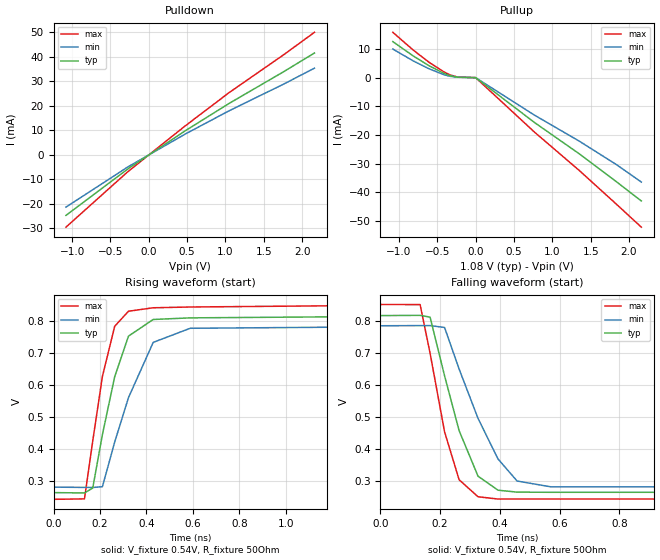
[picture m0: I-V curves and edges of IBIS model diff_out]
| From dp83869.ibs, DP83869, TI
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|   diff_out Model
[Model]   diff_out
Model_type   Output
Polarity   Non-Inverting
Vmeas = 0.54
Vref = 0.54
Cref = 2pF
Rref = 50
|   typ   min   max
C_comp   0.081pF   0.075pF   0.098pF
| Where Nom  PVT is Nominal Process, 1.08V,  27C
|   Fast PVT is Strong Process,  1.09V, -55C
|   Slow PVT is Weak Process,   1.07V, 135C
[Voltage Range]   1.08   1.07   1.09
|Junction Temperature
[Temperature Range]   27   135   -55
[Pullup Reference]   1.08   1.07   1.09
[Pulldown Reference]   0   -0   -0
[Power Clamp Reference]   1.08   1.07   1.09
[GND Clamp Reference]   0   0   0
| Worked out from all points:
|   slope of the pulldown table from 0 to 0.162 V, typ, clamps not added: 48.8 ohm
|   slope of the pullup table from 0 to 0.162 V, typ, clamps not added: 48.7 ohm
|   falling waveform, V_fixture 0.54V, R_fixture 50Ohm: 20-80 % time 100ps typ, 128ps min, 80.9ps max; typ from 0.816 V to 0.265 V
|   rising waveform, V_fixture 0.54V, R_fixture 50Ohm: 20-80 % time 107ps typ, 138ps min, 85.8ps max; typ from 0.265 V to 0.816 V
[Pulldown]
|   Voltage   I(typ)   I(min)   I(max)
-1.08V    -24.73mA   -21.35mA   -29.52mA
-269.8mV  -5.716mA   -4.92mA    -6.83mA
479.9mV   9.828mA    8.49mA     11.85mA
1.046V    20.87mA    17.87mA    25.27mA
1.753V    33.72mA    28.68mA    40.6mA
2.16V     41.43mA    35.26mA    49.86mA
[Pullup]
|   Voltage   I(typ)   I(min)   I(max)
-1.08V    12.65mA    10.05mA    15.9mA
-815.1mV  7.658mA    5.926mA    9.721mA
-607.7mV  4.22mA     3.144mA    5.419mA
-409.5mV  1.486mA    1.026mA    2mA
-333.6mV  729.9uA    520.3uA    998.9uA
-232.6mV  202.8uA    195.3uA    237.1uA
-569.9uV  57.3uA     57.64uA    64.98uA
767mV     -15.63mA   -13.06mA   -18.99mA
1.351V    -26.58mA   -22.15mA   -32.41mA
1.833V    -36.29mA   -30.31mA   -44.14mA
2.16V     -43.07mA   -36.45mA   -52.22mA
[Ramp]
R_load = 50
|   typ   min   max
dV/dt_r   0.330531/1.06843e-10   0.301374/1.36477e-10   0.363763/8.59245e-11
dV/dt_f   0.330531/9.98239e-11   0.301374/1.28638e-10   0.363764/8.10318e-11
[Falling Waveform]
V_fixture = 0.54V
V_fixture_min = 0.533V
V_fixture_max = 0.547V
R_fixture = 50Ohm
C_fixture = 0F
|   Time   V(typ)   V(min)   V(max)
0s        815.8mV    784.2mV    850.3mV
132.9ps   816.5mV    784.6mV    850mV
166.3ps   811mV      784.7mV    698.7mV
214.8ps   628.3mV    778.8mV    454mV
263.5ps   457.7mV    649.4mV    304.9mV
326.8ps   316mV      495.9mV    252mV
393.7ps   272.4mV    369.6mV    244.9mV
457.5ps   266.4mV    301mV      244.9mV
570.4ps   265.9mV    282.9mV    244.9mV
20ns      264.9mV    281.9mV    244mV
[Rising Waveform]
V_fixture = 0.54V
V_fixture_min = 0.533V
V_fixture_max = 0.547V
R_fixture = 50Ohm
C_fixture = 0F
|   Time   V(typ)   V(min)   V(max)
0s        264.9mV    281.9mV    244mV
133.3ps   263.9mV    281.1mV    245.4mV
169ps     279.1mV    280.9mV    426mV
210.6ps   445.5mV    283.3mV    626.5mV
263.5ps   625.5mV    422.3mV    782.5mV
322.9ps   751.9mV    560.4mV    829.4mV
429.4ps   803.7mV    732.4mV    840.1mV
588.8ps   808.7mV    776.3mV    842.5mV
1.596ns   814mV      781.8mV    848.8mV
20ns      815.8mV    784.2mV    850.3mV
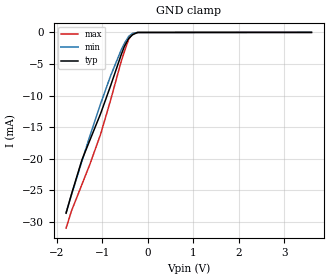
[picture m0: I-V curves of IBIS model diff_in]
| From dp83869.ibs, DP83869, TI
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|   diff_in Model
[Model]   diff_in
Model_type   Input
Vinl = 1.05
Vinh = 1.35
|   typ   min   max
C_comp   0.6913pF   0.5645pF   0.8047pF
| Where Nom  PVT is Nominal Process, 1.8V,  27C
|   Fast PVT is Strong Process,  1.98V, -55C
|   Slow PVT is Weak Process,   1.62V, 135C
[Voltage Range]   1.8   1.62   1.98
|Junction Temperature
[Temperature Range]   27   135   -55
[Power Clamp Reference]   1.8   1.62   1.98
[GND Clamp Reference]   0   0   0
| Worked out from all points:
|   GND clamp passes 1 mA (typ) near -0.43 V on its own axis
[GND Clamp]
|   Voltage   I(typ)   I(min)   I(max)
-1.8V     -28.65mA   -28.51mA   -31.01mA
-1.682V   -25.64mA   -25.76mA   -28.3mA
-1.451V   -20.19mA   -20.38mA   -24.08mA
-1.28V    -17.14mA   -16.49mA   -20.96mA
-1.042V   -12.9mA    -11.33mA   -16.17mA
-820.4mV  -8.452mA   -6.879mA   -10.73mA
-590mV    -3.59mA    -2.819mA   -4.663mA
-518.3mV  -2.241mA   -1.756mA   -3.076mA
-424.8mV  -985.2uA   -662.5uA   -1.126mA
-337.8mV  -382.5uA   -167.5uA   -177uA
-226.8mV  -13.64uA   -22.88uA   -10.64uA
3.6V      0A         0A         0A
[POWER Clamp]
|   Voltage   I(typ)   I(min)   I(max)
-1.8V     0A         0A         0A
0V        0A         0A         0A
3.6V      0A         0A         0A
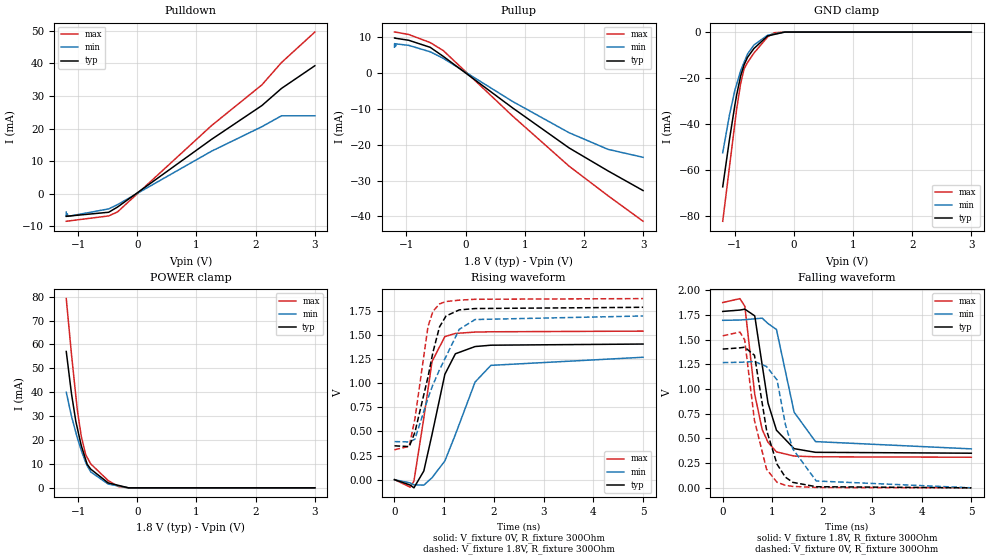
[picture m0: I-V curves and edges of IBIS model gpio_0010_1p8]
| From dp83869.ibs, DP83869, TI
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|   gpio_0010_p8 Model
[Model]   gpio_0010_1p8
Model_type   I/O
Polarity   Non-Inverting
Enable   Active-Low
Vinl = 0.344
Vinh = 1.204
Vmeas = 0.9
Vref = 0
Cref = 2pF
Rref = 100000
|   typ   min   max
C_comp   1.311pF   1.163pF   1.492pF
| Where Nom  PVT is Nominal Process, 1.8V,  27C
|   Fast PVT is Strong Process,  1.89V, -40C
|   Slow PVT is Weak Process,   1.71V, 125C
[Voltage Range]   1.8   1.71   1.89
|Junction Temperature
[Temperature Range]   27   125   -40
[Pullup Reference]   1.8   1.71   1.89
[Pulldown Reference]   0   -0   0
[Power Clamp Reference]   1.8   1.71   1.89
[GND Clamp Reference]   0   0   0
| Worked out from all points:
|   slope of the pulldown table from 0 to 0.27 V, typ, clamps not added: 73.5 ohm
|   slope of the pullup table from 0 to 0.27 V, typ, clamps not added: 80.4 ohm
|   GND clamp passes 1 mA (typ) near -0.32 V on its own axis
|   POWER clamp passes 1 mA (typ) near -0.31 V on its own axis
|   falling waveform, V_fixture 1.8V, R_fixture 300Ohm: 20-80 % time 304ps typ, 372ps min, 261ps max; typ from 1.79 V to 0.351 V
|   rising waveform, V_fixture 0V, R_fixture 300Ohm: 20-80 % time 351ps typ, 556ps min, 255ps max; typ from 0 V to 1.41 V
|   rising waveform, V_fixture 1.8V, R_fixture 300Ohm: 20-80 % time 371ps typ, 611ps min, 256ps max; typ from 0.351 V to 1.79 V
|   falling waveform, V_fixture 0V, R_fixture 300Ohm: 20-80 % time 337ps typ, 409ps min, 287ps max; typ from 1.41 V to 0 V
[Pulldown]
|   Voltage   I(typ)   I(min)   I(max)
-1.2V     -6.882mA   -5.603mA   -8.407mA
-1.2V     -6.882mA   -6.645mA   -8.407mA
-1.199V   -6.881mA   -6.942mA   -8.406mA
-1.18V    -6.847mA   -6.135mA   -8.362mA
-1.177V   -6.842mA   -6.895mA   -8.354mA
-1.163V   -6.817mA   -6.884mA   -8.322mA
-483.5mV  -5.644mA   -4.611mA   -6.772mA
-334.2mV  -4.049mA   -3.307mA   -5.542mA
1.25V     16.65mA    13.04mA    20.86mA
2.105V    27.07mA    20.59mA    33.41mA
2.436V    32.32mA    23.93mA    40.25mA
3V        39.28mA    23.92mA    49.61mA
[GND Clamp]
|   Voltage   I(typ)   I(min)   I(max)
-1.2V     -67.24mA   -52.42mA   -82.2mA
-1.087V   -46.84mA   -36.18mA   -58.78mA
-994.8mV  -31.76mA   -25.29mA   -39.68mA
-965.1mV  -27.37mA   -22.71mA   -33.52mA
-896.4mV  -19mA      -16.77mA   -22.28mA
-837.9mV  -14.15mA   -13.09mA   -15.9mA
-780.3mV  -10.96mA   -9.507mA   -13.2mA
-671.8mV  -7.121mA   -5.608mA   -9.106mA
-441.2mV  -1.683mA   -1.371mA   -2.11mA
-326mV    -1.018mA   -830.8uA   -284.2uA
-149.7mV  -2.225uA   -4.171uA   -2.272uA
3V        0A         0A         0A
[Pullup]
|   Voltage   I(typ)   I(min)   I(max)
-1.2V     9.812mA    7.256mA    11.5mA
-1.2V     9.811mA    8.028mA    11.5mA
-1.199V   9.81mA     8.276mA    11.5mA
-1.18V    9.761mA    7.582mA    11.47mA
-1.176V   9.752mA    8.197mA    11.47mA
-961.2mV  9.21mA     7.789mA    10.82mA
-596.7mV  7.232mA    5.979mA    8.559mA
-375mV    4.688mA    4.146mA    6.315mA
794.3mV   -9.681mA   -7.884mA   -11.95mA
1.75V     -20.88mA   -16.63mA   -25.97mA
2.409V    -27.31mA   -21.28mA   -34.25mA
3V        -32.79mA   -23.5mA    -41.37mA
[POWER Clamp]
|   Voltage   I(typ)   I(min)   I(max)
-1.2V     57.06mA    40.03mA    79.18mA
-1.112V   39.45mA    29.98mA    55.97mA
-1.038V   27.78mA    23.2mA     38.38mA
-1.012V   24.88mA    20.8mA     32.43mA
-946.8mV  17.71mA    15.75mA    21.64mA
-872.4mV  11.86mA    10.61mA    13.9mA
-845.6mV  9.826mA    9.2mA      12.69mA
-786.3mV  7.824mA    6.665mA    10.02mA
-492.1mV  2.079mA    1.585mA    3.05mA
-321.3mV  1.044mA    798.3uA    550.5uA
-149.7mV  3.256uA    7.598uA    3.487uA
3V        0A         0A         0A
[Ramp]
R_load = 300
|   typ   min   max
dV/dt_r   0.843678/3.50311e-10   0.760981/5.54332e-10   0.924201/2.5399e-10
dV/dt_f   0.861703/3.02041e-10   0.781303/3.71472e-10   0.939826/2.58127e-10
[Falling Waveform]
V_fixture = 1.8V
V_fixture_min = 1.71V
V_fixture_max = 1.89V
R_fixture = 300Ohm
C_fixture = 0F
|   Time   V(typ)   V(min)   V(max)
0s        1.787V     1.697V     1.877V
346.1ps   1.801V     1.7V       1.917V
445.4ps   1.81V      1.704V     1.838V
644.3ps   1.742V     1.712V     945.9mV
794.1ps   1.243V     1.719V     590.3mV
911.2ps   858.3mV    1.664V     461.5mV
1.081ns   583.8mV    1.604V     364.2mV
1.436ns   397.1mV    766.7mV    322.1mV
1.866ns   359.9mV    468.4mV    314.5mV
5ns       350.9mV    394.8mV    310.1mV
[Rising Waveform]
V_fixture = 0V
V_fixture_min = 0V
V_fixture_max = 0V
R_fixture = 300Ohm
C_fixture = 0F
|   Time   V(typ)   V(min)   V(max)
0s        142.8uV    347.4uV    103.5uV
314.9ps   -56mV      -33.82mV   -77.08mV
390.9ps   -84.63mV   -53.95mV   -14.92mV
590.1ps   90.29mV    -56.41mV   639.5mV
755.5ps   469.5mV    20.39mV    1.226V
1.013ns   1.092V     194.1mV    1.483V
1.225ns   1.305V     467.7mV    1.516V
1.621ns   1.38V      1.012V     1.53V
1.939ns   1.394V     1.185V     1.533V
5ns       1.406V     1.269V     1.54V
[Rising Waveform]
V_fixture = 1.8V
V_fixture_min = 1.71V
V_fixture_max = 1.89V
R_fixture = 300Ohm
C_fixture = 0F
|   Time   V(typ)   V(min)   V(max)
0s        350.9mV    394.9mV    310.1mV
296.8ps   343mV      391.2mV    345.3mV
411ps     491.2mV    419.6mV    631.7mV
674.3ps   1.066V     845.4mV    1.588V
772.2ps   1.318V     983mV      1.744V
905.7ps   1.584V     1.139V     1.822V
1.037ns   1.697V     1.277V     1.847V
1.303ns   1.76V      1.559V     1.861V
1.621ns   1.774V     1.66V      1.87V
5ns       1.787V     1.697V     1.877V
[Falling Waveform]
|Gnd
V_fixture = 0V
V_fixture_min = 0V
V_fixture_max = 0V
R_fixture = 300Ohm
C_fixture = 0F
|   Time   V(typ)   V(min)   V(max)
0s        1.406V     1.269V     1.54V
344.8ps   1.418V     1.272V     1.578V
441.5ps   1.425V     1.274V     1.499V
638.5ps   1.343V     1.28V      682.3mV
881.7ps   584.1mV    1.229V     188.1mV
1.093ns   239.1mV    1.093V     56.01mV
1.259ns   108.8mV    644.5mV    25.59mV
1.409ns   55.68mV    393.8mV    14.67mV
1.881ns   11.4mV     69.5mV     3.683mV
5ns       142.7uV    344.1uV    103.4uV
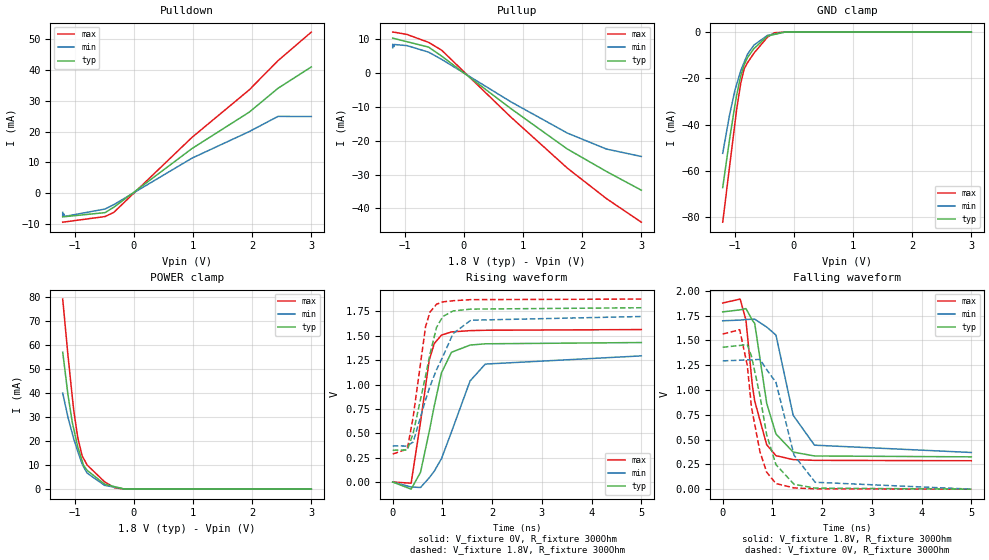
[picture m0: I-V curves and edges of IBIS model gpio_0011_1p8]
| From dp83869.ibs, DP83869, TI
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|   gpio_0011_1p8 Model
[Model]   gpio_0011_1p8
Model_type   I/O
Polarity   Non-Inverting
Enable   Active-Low
Vinl = 0.344
Vinh = 1.204
Vmeas = 0.9
Vref = 0
Cref = 2pF
Rref = 100000
|   typ   min   max
C_comp   1.311pF   1.163pF   1.492pF
| Where Nom  PVT is Nominal Process, 1.8V,  27C
|   Fast PVT is Strong Process,  1.89V, -40C
|   Slow PVT is Weak Process,   1.71V, 125C
[Voltage Range]   1.8   1.71   1.89
|Junction Temperature
[Temperature Range]   27   125   -40
[Pullup Reference]   1.8   1.71   1.89
[Pulldown Reference]   0   -0   0
[Power Clamp Reference]   1.8   1.71   1.89
[GND Clamp Reference]   0   0   0
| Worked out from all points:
|   slope of the pulldown table from 0 to 0.27 V, typ, clamps not added: 66.5 ohm
|   slope of the pullup table from 0 to 0.27 V, typ, clamps not added: 73.4 ohm
|   GND clamp passes 1 mA (typ) near -0.32 V on its own axis
|   POWER clamp passes 1 mA (typ) near -0.31 V on its own axis
|   falling waveform, V_fixture 1.8V, R_fixture 300Ohm: 20-80 % time 310ps typ, 381ps min, 265ps max; typ from 1.79 V to 0.326 V
|   rising waveform, V_fixture 0V, R_fixture 300Ohm: 20-80 % time 349ps typ, 556ps min, 253ps max; typ from 0 V to 1.43 V
|   rising waveform, V_fixture 1.8V, R_fixture 300Ohm: 20-80 % time 366ps typ, 585ps min, 256ps max; typ from 0.326 V to 1.79 V
|   falling waveform, V_fixture 0V, R_fixture 300Ohm: 20-80 % time 345ps typ, 425ps min, 290ps max; typ from 1.43 V to 0 V
[Pulldown]
|   Voltage   I(typ)   I(min)   I(max)
-1.2V     -7.586mA   -6.131mA   -9.305mA
-1.2V     -7.586mA   -7.216mA   -9.305mA
-1.199V   -7.584mA   -7.47mA    -9.302mA
-1.18V    -7.548mA   -6.664mA   -9.254mA
-1.177V   -7.542mA   -7.424mA   -9.246mA
-1.154V   -7.498mA   -7.397mA   -9.187mA
-484.9mV  -6.212mA   -5.046mA   -7.479mA
-335.7mV  -4.459mA   -3.622mA   -6.114mA
983.3mV   14.49mA    11.39mA    18.1mA
1.951V    26.27mA    19.99mA    33.47mA
2.437V    33.98mA    24.89mA    42.91mA
3V        40.89mA    24.85mA    52.15mA
[GND Clamp]
|   Voltage   I(typ)   I(min)   I(max)
-1.2V     -67.24mA   -52.42mA   -82.2mA
-1.087V   -46.86mA   -36.19mA   -58.8mA
-994.9mV  -31.78mA   -25.3mA    -39.7mA
-964.9mV  -27.35mA   -22.7mA    -33.49mA
-896.2mV  -18.98mA   -16.75mA   -22.25mA
-837.6mV  -14.13mA   -13.08mA   -15.89mA
-780.4mV  -10.96mA   -9.512mA   -13.2mA
-671.9mV  -7.122mA   -5.611mA   -9.107mA
-441mV    -1.68mA    -1.371mA   -2.105mA
-326mV    -1.017mA   -831.5uA   -284.7uA
-149.9mV  -2.239uA   -4.739uA   -2.288uA
3V        0A         0A         0A
[Pullup]
|   Voltage   I(typ)   I(min)   I(max)
-1.2V     10.26mA    7.441mA    12.05mA
-1.2V     10.26mA    8.244mA    12.05mA
-1.199V   10.26mA    8.456mA    12.05mA
-1.18V    10.18mA    7.771mA    12.02mA
-1.177V   10.16mA    8.388mA    12.02mA
-960mV    9.218mA    8.065mA    11.36mA
-594.5mV  7.629mA    6.137mA    9.026mA
-371.4mV  4.938mA    3.988mA    6.676mA
799.1mV   -10.56mA   -8.548mA   -13.08mA
1.75V     -22.45mA   -17.74mA   -28.08mA
2.409V    -29.05mA   -22.45mA   -37.06mA
3V        -34.6mA    -24.65mA   -44.04mA
[POWER Clamp]
|   Voltage   I(typ)   I(min)   I(max)
-1.2V     57.06mA    40.03mA    79.18mA
-1.112V   39.47mA    29.99mA    56mA
-1.038V   27.78mA    23.2mA     38.37mA
-1.012V   24.91mA    20.83mA    32.49mA
-946.5mV  17.69mA    15.73mA    21.61mA
-872.7mV  11.88mA    10.62mA    13.93mA
-845.3mV  9.809mA    9.183mA    12.69mA
-786.5mV  7.83mA     6.671mA    10.03mA
-492.1mV  2.077mA    1.586mA    3.051mA
-321.6mV  1.043mA    799.4uA    552.5uA
-149.9mV  3.279uA    8.166uA    3.532uA
3V        0A         0A         0A
[Ramp]
R_load = 300
|   typ   min   max
dV/dt_r   0.858578/3.47247e-10   0.776076/5.53587e-10   0.938429/2.53122e-10
dV/dt_f   0.877046/3.08069e-10   0.796646/3.7984e-10   0.954465/2.62352e-10
[Falling Waveform]
V_fixture = 1.8V
V_fixture_min = 1.71V
V_fixture_max = 1.89V
R_fixture = 300Ohm
C_fixture = 0F
|   Time   V(typ)   V(min)   V(max)
0s        1.788V     1.698V     1.877V
350.9ps   1.808V     1.705V     1.917V
467.2ps   1.821V     1.711V     1.706V
596.9ps   1.703V     1.714V     1.043V
643.9ps   1.671V     1.714V     888.2mV
884.5ps   866.2mV    1.635V     448.2mV
1.071ns   556.7mV    1.554V     337.9mV
1.417ns   374.1mV    745.3mV    297.9mV
1.846ns   334.8mV    443.7mV    290.7mV
5ns       326.1mV    370mV      286.7mV
[Rising Waveform]
V_fixture = 0V
V_fixture_min = 0V
V_fixture_max = 0V
R_fixture = 300Ohm
C_fixture = 0F
|   Time   V(typ)   V(min)   V(max)
0s        132.2uV    322uV      94.76uV
370.5ps   -73.43mV   -51.39mV   -12.32mV
559.2ps   99.21mV    -56.11mV   613.8mV
734.8ps   518.6mV    43.6mV     1.251V
835.7ps   779.6mV    111.1mV    1.421V
980.4ps   1.12V      239.4mV    1.507V
1.182ns   1.331V     513.9mV    1.54V
1.556ns   1.405V     1.037V     1.553V
1.862ns   1.418V     1.21V      1.557V
5ns       1.431V     1.294V     1.564V
[Rising Waveform]
V_fixture = 1.8V
V_fixture_min = 1.71V
V_fixture_max = 1.89V
R_fixture = 300Ohm
C_fixture = 0F
|   Time   V(typ)   V(min)   V(max)
0s        326.1mV    370mV      286.7mV
294.2ps   328.7mV    369.2mV    338.4mV
412.3ps   501mV      411.2mV    670.3mV
660.9ps   1.088V     842.9mV    1.594V
748.9ps   1.311V     980.1mV    1.743V
881.5ps   1.586V     1.152V     1.824V
1.007ns   1.698V     1.286V     1.848V
1.215ns   1.755V     1.523V     1.86V
1.571ns   1.774V     1.66V      1.871V
5ns       1.788V     1.698V     1.877V
[Falling Waveform]
|Gnd
V_fixture = 0V
V_fixture_min = 0V
V_fixture_max = 0V
R_fixture = 300Ohm
C_fixture = 0F
|   Time   V(typ)   V(min)   V(max)
0s        1.431V     1.294V     1.564V
341.4ps   1.449V     1.3V       1.608V
494.2ps   1.457V     1.305V     1.249V
578.3ps   1.341V     1.303V     826.6mV
748.9ps   942.7mV    1.309V     377mV
884.5ps   547.2mV    1.205V     170.7mV
1.071ns   247.3mV    1.077V     56.64mV
1.435ns   49.01mV    342.3mV    12.73mV
1.86ns    10.73mV    69.58mV    3.682mV
5ns       131.9uV    318.6uV    94.58uV
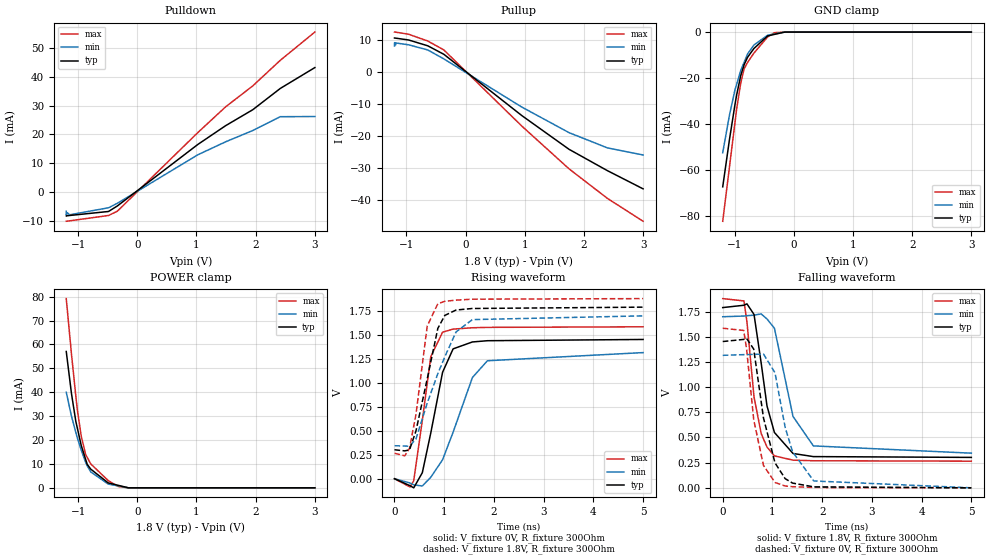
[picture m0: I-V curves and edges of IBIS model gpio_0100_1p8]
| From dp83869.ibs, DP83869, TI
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|   gpio_0100_1p8 Model
[Model]   gpio_0100_1p8
Model_type   I/O
Polarity   Non-Inverting
Enable   Active-Low
Vinl = 0.344
Vinh = 1.204
Vmeas = 0.9
Vref = 0
Cref = 2pF
Rref = 100000
|   typ   min   max
C_comp   1.311pF   1.163pF   1.492pF
| Where Nom  PVT is Nominal Process, 1.8V,  27C
|   Fast PVT is Strong Process,  1.89V, -40C
|   Slow PVT is Weak Process,   1.71V, 125C
[Voltage Range]   1.8   1.71   1.89
|Junction Temperature
[Temperature Range]   27   125   -40
[Pullup Reference]   1.8   1.71   1.89
[Pulldown Reference]   0   0   0
[Power Clamp Reference]   1.8   1.71   1.89
[GND Clamp Reference]   0   0   0
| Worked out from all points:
|   slope of the pulldown table from 0 to 0.27 V, typ, clamps not added: 60.7 ohm
|   slope of the pullup table from 0 to 0.27 V, typ, clamps not added: 68.1 ohm
|   GND clamp passes 1 mA (typ) near -0.32 V on its own axis
|   POWER clamp passes 1 mA (typ) near -0.31 V on its own axis
|   falling waveform, V_fixture 1.8V, R_fixture 300Ohm: 20-80 % time 290ps typ, 366ps min, 244ps max; typ from 1.79 V to 0.302 V
|   rising waveform, V_fixture 0V, R_fixture 300Ohm: 20-80 % time 329ps typ, 541ps min, 234ps max; typ from 0 V to 1.45 V
|   rising waveform, V_fixture 1.8V, R_fixture 300Ohm: 20-80 % time 353ps typ, 585ps min, 238ps max; typ from 0.302 V to 1.79 V
|   falling waveform, V_fixture 0V, R_fixture 300Ohm: 20-80 % time 315ps typ, 396ps min, 263ps max; typ from 1.45 V to 0 V
[Pulldown]
|   Voltage   I(typ)   I(min)   I(max)
-1.2V     -8.344mA   -6.739mA   -10.24mA
-1.2V     -8.343mA   -7.775mA   -10.24mA
-1.199V   -8.341mA   -8.078mA   -10.24mA
-1.18V    -8.301mA   -7.271mA   -10.19mA
-1.144V   -8.225mA   -7.984mA   -10.09mA
-485.8mV  -6.829mA   -5.539mA   -8.224mA
-336.6mV  -4.904mA   -3.978mA   -6.725mA
1.025V    16.53mA    12.92mA    20.68mA
1.492V    23.03mA    17.42mA    29.59mA
1.951V    28.59mA    21.35mA    36.88mA
2.417V    36.01mA    26.17mA    45.81mA
3V        43.26mA    26.21mA    55.63mA
[GND Clamp]
|   Voltage   I(typ)   I(min)   I(max)
-1.2V     -67.24mA   -52.42mA   -82.2mA
-1.087V   -46.85mA   -36.19mA   -58.79mA
-994.8mV  -31.77mA   -25.29mA   -39.69mA
-964.9mV  -27.35mA   -22.7mA    -33.49mA
-896.3mV  -18.98mA   -16.75mA   -22.26mA
-837.7mV  -14.13mA   -13.08mA   -15.89mA
-780.3mV  -10.96mA   -9.509mA   -13.2mA
-671.9mV  -7.12mA    -5.609mA   -9.106mA
-441mV    -1.677mA   -1.371mA   -2.106mA
-326.1mV  -1.016mA   -831.5uA   -284.9uA
-149.5mV  -2.214uA   -4.045uA   -2.26uA
3V        0A         0A         0A
[Pullup]
|   Voltage   I(typ)   I(min)   I(max)
-1.2V     10.74mA    8.24mA     12.6mA
-1.2V     10.74mA    9.03mA     12.6mA
-1.199V   10.74mA    9.282mA    12.59mA
-1.18V    10.69mA    8.576mA    12.57mA
-1.177V   10.68mA    9.188mA    12.56mA
-961.2mV  10.12mA    8.61mA     11.91mA
-637.6mV  8.297mA    6.996mA    9.791mA
-366.1mV  5.643mA    4.204mA    7.004mA
949.3mV   -13.49mA   -10.84mA   -16.77mA
1.749V    -24.06mA   -18.85mA   -30.17mA
2.397V    -30.73mA   -23.62mA   -39.4mA
3V        -36.42mA   -25.83mA   -46.56mA
[POWER Clamp]
|   Voltage   I(typ)   I(min)   I(max)
-1.2V     57.06mA    40.03mA    79.18mA
-1.112V   39.47mA    29.99mA    56.02mA
-1.038V   27.76mA    23.19mA    38.34mA
-1.012V   24.91mA    20.83mA    32.49mA
-946.6mV  17.69mA    15.74mA    21.62mA
-872.7mV  11.89mA    10.63mA    13.93mA
-845.3mV  9.812mA    9.186mA    12.69mA
-786.5mV  7.832mA    6.672mA    10.03mA
-492.1mV  2.078mA    1.585mA    3.051mA
-321.6mV  1.045mA    799.6uA    552.7uA
-149.5mV  3.236uA    7.435uA    3.475uA
3V        0A         0A         0A
[Ramp]
R_load = 300
|   typ   min   max
dV/dt_r   0.871267/3.27771e-10   0.788734/5.38836e-10   0.950576/2.32924e-10
dV/dt_f   0.891835/2.8772e-10   0.812532/3.63371e-10   0.968032/2.42051e-10
[Falling Waveform]
V_fixture = 1.8V
V_fixture_min = 1.71V
V_fixture_max = 1.89V
R_fixture = 300Ohm
C_fixture = 0F
|   Time   V(typ)   V(min)   V(max)
0s        1.789V     1.698V     1.878V
426.8ps   1.812V     1.705V     1.855V
487.1ps   1.826V     1.708V     1.647V
629.6ps   1.721V     1.714V     902.7mV
773.1ps   1.24V      1.726V     539.6mV
890.1ps   813.7mV    1.676V     405.3mV
1.04ns    549.2mV    1.584V     317mV
1.414ns   341mV      708.3mV    274.9mV
1.823ns   310.1mV    416.2mV    268.8mV
5ns       302.1mV    344.1mV    264.8mV
[Rising Waveform]
V_fixture = 0V
V_fixture_min = 0V
V_fixture_max = 0V
R_fixture = 300Ohm
C_fixture = 0F
|   Time   V(typ)   V(min)   V(max)
0s        120.5uV    296.1uV    87.45uV
311.9ps   -72.87mV   -44.38mV   -85.96mV
386.9ps   -95.02mV   -64.21mV   -21.56mV
560ps     62.98mV    -75.57mV   608.7mV
730ps     477.3mV    15.12mV    1.273V
967.2ps   1.11V      197.7mV    1.528V
1.179ns   1.354V     485.1mV    1.56V
1.567ns   1.426V     1.055V     1.574V
1.869ns   1.439V     1.23V      1.578V
5ns       1.452V     1.315V     1.584V
[Rising Waveform]
V_fixture = 1.8V
V_fixture_min = 1.71V
V_fixture_max = 1.89V
R_fixture = 300Ohm
C_fixture = 0F
|   Time   V(typ)   V(min)   V(max)
0s        302.1mV    344.1mV    264.8mV
206.1ps   290.4mV    341mV      239.1mV
301.8ps   300.1mV    338.3mV    316.4mV
431.6ps   497.4mV    414.4mV    668.7mV
658.4ps   1.041V     788mV      1.592V
872ps     1.568V     1.096V     1.825V
1.013ns   1.703V     1.272V     1.85V
1.239ns   1.759V     1.531V     1.862V
1.567ns   1.775V     1.659V     1.872V
5ns       1.789V     1.698V     1.878V
[Falling Waveform]
|Gnd
V_fixture = 0V
V_fixture_min = 0V
V_fixture_max = 0V
R_fixture = 300Ohm
C_fixture = 0F
|   Time   V(typ)   V(min)   V(max)
0s        1.452V     1.315V     1.584V
422.2ps   1.473V     1.322V     1.562V
479.6ps   1.483V     1.322V     1.381V
623.3ps   1.377V     1.325V     674.7mV
819.6ps   694.5mV    1.328V     223.1mV
1.051ns   248.1mV    1.142V     53.2mV
1.256ns   91.25mV    599.4mV    18.38mV
1.405ns   47.1mV     357.7mV    11.53mV
1.831ns   9.793mV    68.2mV     3.539mV
5ns       119.6uV    292.5uV    87.41uV
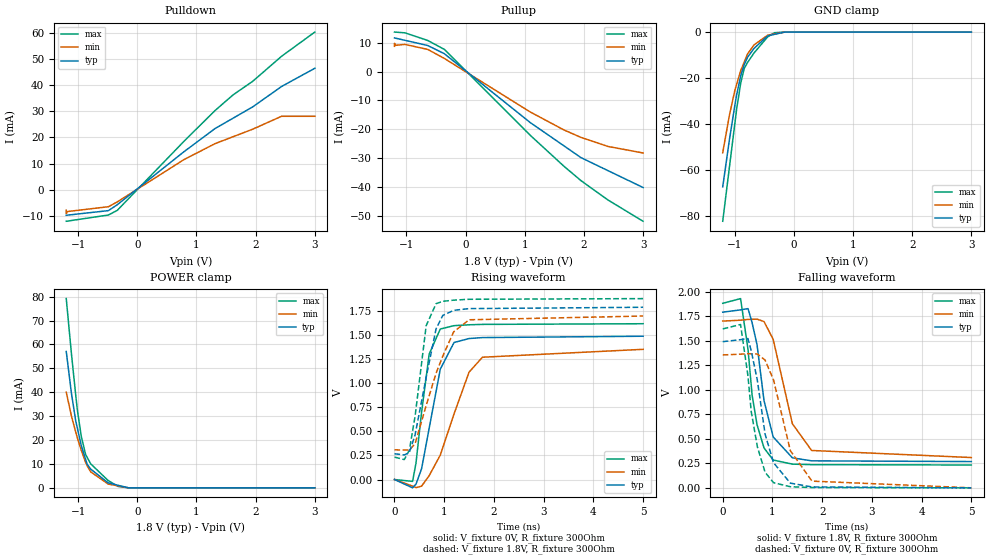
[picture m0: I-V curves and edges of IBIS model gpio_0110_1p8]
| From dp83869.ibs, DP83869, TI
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|   gpio_0110_1p8 Model
[Model]   gpio_0110_1p8
Model_type   I/O
Polarity   Non-Inverting
Enable   Active-Low
Vinl = 0.344
Vinh = 1.204
Vmeas = 0.9
Vref = 0
Cref = 2pF
Rref = 100000
|   typ   min   max
C_comp   1.311pF   1.163pF   1.492pF
| Where Nom  PVT is Nominal Process, 1.8V,  27C
|   Fast PVT is Strong Process,  1.89V, -40C
|   Slow PVT is Weak Process,   1.71V, 125C
[Voltage Range]   1.8   1.71   1.89
|Junction Temperature
[Temperature Range]   27   125   -40
[Pullup Reference]   1.8   1.71   1.89
[Pulldown Reference]   -0   0   -0
[Power Clamp Reference]   1.8   1.71   1.89
[GND Clamp Reference]   0   0   0
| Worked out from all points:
|   slope of the pulldown table from 0 to 0.27 V, typ, clamps not added: 53.5 ohm
|   slope of the pullup table from 0 to 0.27 V, typ, clamps not added: 60.3 ohm
|   GND clamp passes 1 mA (typ) near -0.32 V on its own axis
|   POWER clamp passes 1 mA (typ) near -0.31 V on its own axis
|   falling waveform, V_fixture 1.8V, R_fixture 300Ohm: 20-80 % time 295ps typ, 376ps min, 247ps max; typ from 1.79 V to 0.268 V
|   rising waveform, V_fixture 0V, R_fixture 300Ohm: 20-80 % time 320ps typ, 536ps min, 228ps max; typ from 0 V to 1.49 V
|   rising waveform, V_fixture 1.8V, R_fixture 300Ohm: 20-80 % time 338ps typ, 546ps min, 234ps max; typ from 0.268 V to 1.79 V
|   falling waveform, V_fixture 0V, R_fixture 300Ohm: 20-80 % time 321ps typ, 422ps min, 265ps max; typ from 1.49 V to 0 V
[Pulldown]
|   Voltage   I(typ)   I(min)   I(max)
-1.2V     -9.726mA   -7.769mA   -12.01mA
-1.2V     -9.726mA   -8.965mA   -12.01mA
-1.198V   -9.722mA   -9.107mA   -12.01mA
-1.181V   -9.679mA   -8.301mA   -11.95mA
-488.2mV  -7.948mA   -6.456mA   -9.617mA
-338.6mV  -5.709mA   -4.627mA   -7.852mA
788.9mV   14.53mA    11.53mA    18.51mA
1.315V    23.39mA    17.62mA    30.26mA
1.616V    27.29mA    20.23mA    36.18mA
1.951V    31.65mA    23.13mA    41.41mA
2.437V    39.41mA    28.05mA    50.93mA
3V        46.37mA    28.05mA    60.19mA
[GND Clamp]
|   Voltage   I(typ)   I(min)   I(max)
-1.2V     -67.24mA   -52.42mA   -82.2mA
-1.087V   -46.8mA    -36.15mA   -58.73mA
-994.6mV  -31.73mA   -25.27mA   -39.64mA
-964.9mV  -27.34mA   -22.69mA   -33.48mA
-896.2mV  -18.97mA   -16.75mA   -22.25mA
-837.6mV  -14.13mA   -13.08mA   -15.89mA
-780mV    -10.95mA   -9.494mA   -13.19mA
-671.2mV  -7.103mA   -5.592mA   -9.086mA
-441mV    -1.675mA   -1.368mA   -2.104mA
-326mV    -1.014mA   -829.7uA   -284.5uA
-149.9mV  -2.237uA   -5.374uA   -2.286uA
3V        0A         0A         0A
[Pullup]
|   Voltage   I(typ)   I(min)   I(max)
-1.2V     11.66mA    8.759mA    13.7mA
-1.2V     11.66mA    9.676mA    13.7mA
-1.199V   11.65mA    9.795mA    13.69mA
-1.181V   11.57mA    9.104mA    13.67mA
-1.024V   10.84mA    9.409mA    13.43mA
-638.6mV  9.032mA    7.68mA     10.78mA
-358.1mV  6.195mA    4.551mA    7.687mA
1.093V    -17.69mA   -14.02mA   -22.1mA
1.661V    -25.74mA   -20.23mA   -32.81mA
1.95V     -29.85mA   -22.84mA   -37.82mA
2.407V    -34.37mA   -25.98mA   -44.55mA
3V        -40.22mA   -28.24mA   -51.93mA
[POWER Clamp]
|   Voltage   I(typ)   I(min)   I(max)
-1.2V     57.06mA    40.03mA    79.18mA
-1.112V   39.46mA    29.98mA    55.99mA
-1.038V   27.76mA    23.19mA    38.34mA
-1.012V   24.9mA     20.83mA    32.48mA
-946.5mV  17.68mA    15.73mA    21.61mA
-872.7mV  11.88mA    10.63mA    13.92mA
-845.2mV  9.806mA    9.182mA    12.68mA
-786.5mV  7.83mA     6.673mA    10.03mA
-492.1mV  2.077mA    1.586mA    3.05mA
-321.5mV  1.043mA    799.8uA    552.3uA
-149.9mV  3.275uA    8.764uA    3.528uA
3V        0A         0A         0A
[Ramp]
R_load = 300
|   typ   min   max
dV/dt_r   0.893424/3.18195e-10   0.81186/5.33659e-10   0.971265/2.27143e-10
dV/dt_f   0.913151/2.92741e-10   0.834389/3.73963e-10   0.988038/2.43813e-10
[Falling Waveform]
V_fixture = 1.8V
V_fixture_min = 1.71V
V_fixture_max = 1.89V
R_fixture = 300Ohm
C_fixture = 0F
|   Time   V(typ)   V(min)   V(max)
0s        1.79V      1.699V     1.88V
358.8ps   1.813V     1.708V     1.928V
509ps     1.826V     1.716V     1.409V
591.6ps   1.681V     1.717V     943.3mV
690.1ps   1.458V     1.719V     643.5mV
830.7ps   888.2mV    1.694V     406.4mV
1.015ns   518.5mV    1.513V     283.5mV
1.401ns   305.9mV    653mV      241.6mV
1.788ns   275mV      380.7mV    236.3mV
5ns       267.8mV    308.8mV    232.8mV
[Rising Waveform]
V_fixture = 0V
V_fixture_min = 0V
V_fixture_max = 0V
R_fixture = 300Ohm
C_fixture = 0F
|   Time   V(typ)   V(min)   V(max)
0s        105.5uV    261.5uV    75.99uV
363.5ps   -86.25mV   -68.14mV   -19.38mV
432.7ps   -47.7mV    -84.3mV    171.1mV
545.1ps   112.1mV    -68.47mV   700.2mV
697.7ps   533.3mV    40.17mV    1.304V
921.2ps   1.147V     254.1mV    1.564V
1.198ns   1.424V     682.1mV    1.599V
1.5ns     1.465V     1.116V     1.608V
1.769ns   1.475V     1.271V     1.612V
5ns       1.489V     1.353V     1.619V
[Rising Waveform]
V_fixture = 1.8V
V_fixture_min = 1.71V
V_fixture_max = 1.89V
R_fixture = 300Ohm
C_fixture = 0F
|   Time   V(typ)   V(min)   V(max)
0s        267.8mV    308.8mV    232.8mV
196.7ps   255.5mV    306.1mV    207.4mV
298.5ps   280.1mV    306.6mV    304.4mV
413.6ps   462.7mV    370.9mV    654.4mV
637.5ps   1.062V     769.9mV    1.599V
836.2ps   1.566V     1.104V     1.827V
972.7ps   1.706V     1.284V     1.852V
1.191ns   1.758V     1.535V     1.864V
1.5ns     1.776V     1.66V      1.873V
5ns       1.79V      1.699V     1.88V
[Falling Waveform]
|Gnd
V_fixture = 0V
V_fixture_min = 0V
V_fixture_max = 0V
R_fixture = 300Ohm
C_fixture = 0F
|   Time   V(typ)   V(min)   V(max)
0s        1.489V     1.354V     1.619V
358.8ps   1.51V      1.362V     1.664V
506.4ps   1.521V     1.367V     1.144V
573.6ps   1.396V     1.366V     777mV
697.7ps   1.092V     1.364V     416.5mV
852.5ps   546.2mV    1.301V     158.6mV
1.022ns   255.8mV    1.1V       52.45mV
1.36ns    47.9mV     378.3mV    11.25mV
1.795ns   9.089mV    68.42mV    3.12mV
5ns       105uV      258.1uV    75.94uV
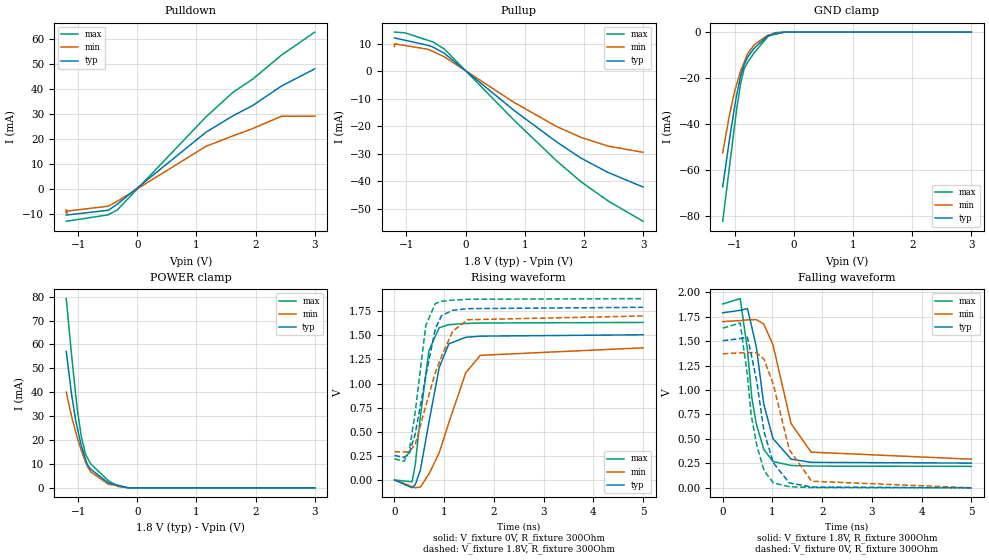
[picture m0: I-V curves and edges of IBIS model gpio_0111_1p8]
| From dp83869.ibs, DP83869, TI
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|   gpio_0111_1p8 Model
[Model]   gpio_0111_1p8
Model_type   I/O
Polarity   Non-Inverting
Enable   Active-Low
Vinl = 0.344
Vinh = 1.204
Vmeas = 0.9
Vref = 0
Cref = 2pF
Rref = 100000
|   typ   min   max
C_comp   1.311pF   1.163pF   1.492pF
| Where Nom  PVT is Nominal Process, 1.8V,  27C
|   Fast PVT is Strong Process,  1.89V, -40C
|   Slow PVT is Weak Process,   1.71V, 125C
[Voltage Range]   1.8   1.71   1.89
|Junction Temperature
[Temperature Range]   27   125   -40
[Pullup Reference]   1.8   1.71   1.89
[Pulldown Reference]   0   0   0
[Power Clamp Reference]   1.8   1.71   1.89
[GND Clamp Reference]   0   0   0
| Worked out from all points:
|   slope of the pulldown table from 0 to 0.27 V, typ, clamps not added: 50.2 ohm
|   slope of the pullup table from 0 to 0.27 V, typ, clamps not added: 56.9 ohm
|   GND clamp passes 1 mA (typ) near -0.32 V on its own axis
|   POWER clamp passes 1 mA (typ) near -0.31 V on its own axis
|   falling waveform, V_fixture 1.8V, R_fixture 300Ohm: 20-80 % time 306ps typ, 396ps min, 254ps max; typ from 1.79 V to 0.253 V
|   rising waveform, V_fixture 0V, R_fixture 300Ohm: 20-80 % time 316ps typ, 528ps min, 228ps max; typ from 0 V to 1.5 V
|   rising waveform, V_fixture 1.8V, R_fixture 300Ohm: 20-80 % time 331ps typ, 525ps min, 233ps max; typ from 0.253 V to 1.79 V
|   falling waveform, V_fixture 0V, R_fixture 300Ohm: 20-80 % time 335ps typ, 461ps min, 272ps max; typ from 1.5 V to 0 V
[Pulldown]
|   Voltage   I(typ)   I(min)   I(max)
-1.2V     -10.43mA   -8.298mA   -12.91mA
-1.2V     -10.43mA   -9.44mA    -12.91mA
-1.2V     -10.43mA   -9.632mA   -12.91mA
-1.187V   -10.4mA    -9.619mA   -12.86mA
-1.181V   -10.38mA   -8.829mA   -12.84mA
-489.5mV  -8.521mA   -6.903mA   -10.33mA
-339.1mV  -6.112mA   -4.94mA    -8.42mA
1.157V    22.56mA    16.95mA    28.64mA
1.613V    29.12mA    21.14mA    38.47mA
1.951V    33.29mA    24.08mA    43.83mA
2.436V    41.04mA    29mA       53.38mA
3V        47.92mA    29.01mA    62.58mA
[GND Clamp]
|   Voltage   I(typ)   I(min)   I(max)
-1.2V     -67.24mA   -52.42mA   -82.2mA
-1.087V   -46.79mA   -36.15mA   -58.72mA
-994.6mV  -31.73mA   -25.27mA   -39.64mA
-964.9mV  -27.35mA   -22.7mA    -33.49mA
-896.3mV  -18.98mA   -16.76mA   -22.26mA
-837.7mV  -14.14mA   -13.09mA   -15.89mA
-780mV    -10.94mA   -9.493mA   -13.18mA
-671.2mV  -7.104mA   -5.592mA   -9.087mA
-441.1mV  -1.681mA   -1.368mA   -2.107mA
-326.1mV  -1.018mA   -830.1uA   -285.3uA
-149.6mV  -2.223uA   -4.071uA   -2.264uA
3V        0A         0A         0A
[Pullup]
|   Voltage   I(typ)   I(min)   I(max)
-1.2V     12.11mA    8.943mA    14.25mA
-1.2V     12.11mA    9.861mA    14.25mA
-1.199V   12.1mA     9.976mA    14.24mA
-1.021V   11.26mA    9.352mA    13.96mA
-638.6mV  9.442mA    8.012mA    11.26mA
-545.5mV  8.769mA    7.186mA    10.61mA
-354.1mV  6.463mA    5.205mA    8.021mA
825.2mV   -14.3mA    -11.38mA   -17.87mA
1.54V     -25.67mA   -20.07mA   -32.55mA
1.951V    -31.54mA   -24mA      -40.11mA
2.407V    -36.73mA   -27.16mA   -47.07mA
3V        -42.03mA   -29.43mA   -54.47mA
[POWER Clamp]
|   Voltage   I(typ)   I(min)   I(max)
-1.2V     57.06mA    40.03mA    79.18mA
-1.112V   39.46mA    29.99mA    56mA
-1.038V   27.77mA    23.2mA     38.37mA
-1.012V   24.91mA    20.83mA    32.49mA
-946.6mV  17.7mA     15.74mA    21.63mA
-872.8mV  11.89mA    10.63mA    13.93mA
-845.2mV  9.808mA    9.184mA    12.69mA
-786.2mV  7.82mA     6.665mA    10.02mA
-491.4mV  2.072mA    1.582mA    3.036mA
-321.2mV  1.041mA    798.4uA    549.5uA
-149.6mV  3.246uA    7.478uA    3.484uA
3V        0A         0A         0A
[Ramp]
R_load = 300
|   typ   min   max
dV/dt_r   0.902938/3.14249e-10   0.821981/5.26547e-10   0.980021/2.26343e-10
dV/dt_f   0.922308/3.03975e-10   0.844022/3.93294e-10   0.996494/2.51243e-10
[Falling Waveform]
V_fixture = 1.8V
V_fixture_min = 1.71V
V_fixture_max = 1.89V
R_fixture = 300Ohm
C_fixture = 0F
|   Time   V(typ)   V(min)   V(max)
0s        1.79V      1.7V       1.88V
351.9ps   1.815V     1.71V      1.935V
497ps     1.834V     1.718V     1.412V
586.6ps   1.64V      1.719V     915.9mV
675.2ps   1.442V     1.72V      655.1mV
825.9ps   854.2mV    1.675V     393.3mV
1.011ns   503.2mV    1.462V     268.8mV
1.375ns   293.6mV    656.8mV    228.5mV
1.779ns   260.6mV    365mV      222.6mV
5ns       253.1mV    293.2mV    219.3mV
[Rising Waveform]
V_fixture = 0V
V_fixture_min = 0V
V_fixture_max = 0V
R_fixture = 300Ohm
C_fixture = 0F
|   Time   V(typ)   V(min)   V(max)
0s        99.55uV    247uV      71.36uV
353.8ps   -80.74mV   -68.81mV   -19.52mV
418.1ps   -48.56mV   -81.52mV   160.2mV
520.9ps   102.5mV    -73.61mV   657mV
692.3ps   596.8mV    61.18mV    1.34V
899.7ps   1.166V     282.1mV    1.578V
1.094ns   1.411V     594.4mV    1.61V
1.432ns   1.479V     1.11V      1.622V
1.726ns   1.491V     1.292V     1.627V
5ns       1.505V     1.37V      1.633V
[Rising Waveform]
V_fixture = 1.8V
V_fixture_min = 1.71V
V_fixture_max = 1.89V
R_fixture = 300Ohm
C_fixture = 0F
|   Time   V(typ)   V(min)   V(max)
0s        253.1mV    293.2mV    219.3mV
192.7ps   234.9mV    290mV      193.7mV
295ps     269.5mV    292.3mV    296.4mV
416.9ps   476.7mV    368.6mV    701.6mV
628.8ps   1.077V     766.5mV    1.601V
821.5ps   1.568V     1.113V     1.829V
947.2ps   1.704V     1.285V     1.852V
1.17ns    1.759V     1.541V     1.864V
1.467ns   1.776V     1.661V     1.873V
5ns       1.79V      1.7V       1.88V
[Falling Waveform]
|Gnd
V_fixture = 0V
V_fixture_min = 0V
V_fixture_max = 0V
R_fixture = 300Ohm
C_fixture = 0F
|   Time   V(typ)   V(min)   V(max)
0s        1.505V     1.371V     1.633V
351.9ps   1.526V     1.38V      1.685V
495.7ps   1.542V     1.384V     1.153V
573.2ps   1.364V     1.383V     744mV
684.5ps   1.088V     1.38V      435.9mV
832.7ps   569.9mV    1.314V     174.4mV
1.019ns   255.2mV    1.055V     51.04mV
1.339ns   50.14mV    390.2mV    11.54mV
1.788ns   8.181mV    67.79mV    2.938mV
5ns       99.75uV    243.1uV    71.19uV
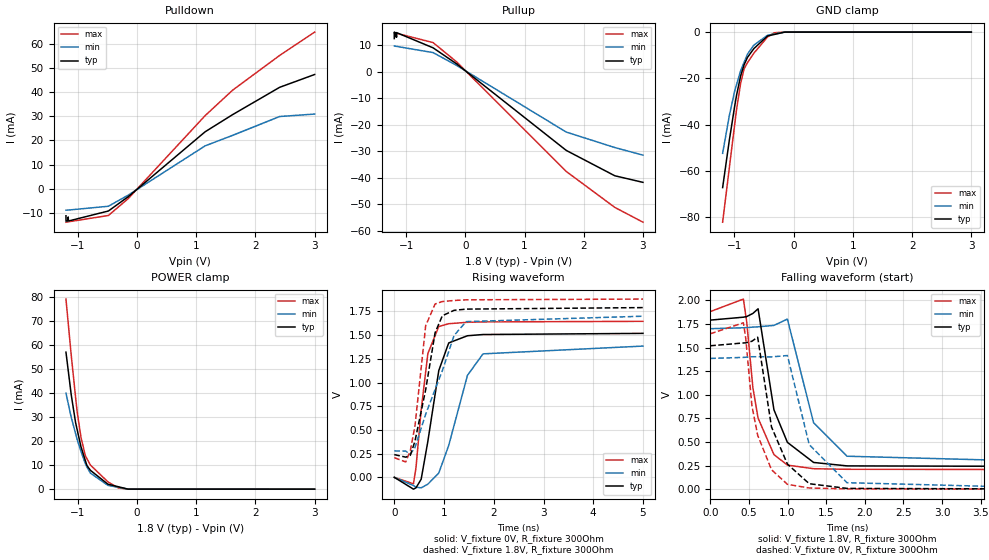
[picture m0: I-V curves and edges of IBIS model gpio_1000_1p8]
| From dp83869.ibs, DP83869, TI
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|   gpio_1000_1p8 Model
[Model]   gpio_1000_1p8
Model_type   I/O
Polarity   Non-Inverting
Enable   Active-Low
Vinl = 0.344
Vinh = 1.204
Vmeas = 0.9
Vref = 0
Cref = 2pF
Rref = 100000
|   typ   min   max
C_comp   1.311pF   1.163pF   1.492pF
| Where Nom  PVT is Nominal Process, 1.8V,  27C
|   Fast PVT is Strong Process,  1.89V, -40C
|   Slow PVT is Weak Process,   1.71V, 125C
[Voltage Range]   1.8   1.71   1.89
|Junction Temperature
[Temperature Range]   27   125   -40
[Pullup Reference]   1.8   1.71   1.89
[Pulldown Reference]   0   0   -0
[Power Clamp Reference]   1.8   1.71   1.89
[GND Clamp Reference]   0   0   0
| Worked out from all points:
|   slope of the pulldown table from 0 to 0.27 V, typ, clamps not added: 47.3 ohm
|   slope of the pullup table from 0 to 0.27 V, typ, clamps not added: 54 ohm
|   GND clamp passes 1 mA (typ) near -0.32 V on its own axis
|   POWER clamp passes 1 mA (typ) near -0.31 V on its own axis
|   falling waveform, V_fixture 1.8V, R_fixture 300Ohm: 20-80 % time 248ps typ, 310ps min, 211ps max; typ from 1.79 V to 0.24 V
|   rising waveform, V_fixture 0V, R_fixture 300Ohm: 20-80 % time 275ps typ, 430ps min, 201ps max; typ from 0 V to 1.52 V
|   rising waveform, V_fixture 1.8V, R_fixture 300Ohm: 20-80 % time 304ps typ, 578ps min, 199ps max; typ from 0.24 V to 1.79 V
|   falling waveform, V_fixture 0V, R_fixture 300Ohm: 20-80 % time 277ps typ, 340ps min, 231ps max; typ from 1.52 V to 0 V
[Pulldown]
|   Voltage   I(typ)   I(min)   I(max)
-1.2V     -11.13mA   -8.839mA   -13.79mA
-1.199V   -13.31mA   -8.837mA   -13.78mA
-1.172V   -13.25mA   -8.788mA   -13.68mA
-1.162V   -11.63mA   -8.768mA   -13.64mA
-1.159V   -13.22mA   -8.764mA   -13.63mA
-1.133V   -13.15mA   -8.715mA   -13.53mA
-483.5mV  -9.168mA   -7.199mA   -11.02mA
-149.8mV  -3.275mA   -2.624mA   -4.066mA
1.15V     23.58mA    17.76mA    30.25mA
1.614V    30.67mA    22.1mA     40.78mA
2.409V    41.97mA    29.9mA     55.15mA
3V        47.27mA    30.91mA    64.8mA
[GND Clamp]
|   Voltage   I(typ)   I(min)   I(max)
-1.2V     -67.24mA   -52.42mA   -82.2mA
-1.087V   -46.79mA   -36.14mA   -58.72mA
-994.6mV  -31.72mA   -25.27mA   -39.63mA
-965mV    -27.36mA   -22.7mA    -33.5mA
-896.4mV  -19mA      -16.77mA   -22.28mA
-837.5mV  -14.12mA   -13.07mA   -15.88mA
-780.1mV  -10.95mA   -9.497mA   -13.19mA
-671.2mV  -7.105mA   -5.592mA   -9.084mA
-440.9mV  -1.679mA   -1.367mA   -2.102mA
-325.9mV  -1.016mA   -828.5uA   -283.5uA
-149.8mV  -2.234uA   -4.072uA   -2.282uA
3V        0A         0A         0A
[Pullup]
|   Voltage   I(typ)   I(min)   I(max)
-1.2V     12.58mA    9.738mA    14.79mA
-1.2V     14.69mA    9.737mA    14.79mA
-1.198V   15.04mA    9.734mA    14.78mA
-1.173V   13.27mA    9.664mA    14.64mA
-1.172V   14.9mA     9.661mA    14.63mA
-1.162V   13.09mA    9.633mA    14.57mA
-1.159V   14.81mA    9.624mA    14.56mA
-545.1mV  9.098mA    7.293mA    11.08mA
-149.8mV  3.07mA     2.479mA    3.818mA
1.704V    -29.66mA   -22.73mA   -37.61mA
2.524V    -39.24mA   -28.58mA   -51.19mA
3V        -41.73mA   -31.45mA   -56.78mA
[POWER Clamp]
|   Voltage   I(typ)   I(min)   I(max)
-1.2V     57.06mA    40.03mA    79.18mA
-1.112V   39.49mA    30mA       56.04mA
-1.038V   27.79mA    23.21mA    38.39mA
-1.012V   24.88mA    20.81mA    32.44mA
-946.5mV  17.67mA    15.73mA    21.6mA
-873.1mV  11.91mA    10.65mA    13.96mA
-845.4mV  9.817mA    9.192mA    12.7mA
-786.4mV  7.83mA     6.672mA    10.03mA
-492mV    2.077mA    1.584mA    3.048mA
-321.4mV  1.043mA    798.3uA    551.2uA
-149.8mV  3.271uA    7.517uA    3.516uA
3V        0A         0A         0A
[Ramp]
R_load = 300
|   typ   min   max
dV/dt_r   0.911232/2.74642e-10   0.830825/4.2935e-10   0.987648/2.0096e-10
dV/dt_f   0.930418/2.47277e-10   0.85287/3.09756e-10   1.00387/2.10443e-10
[Falling Waveform]
V_fixture = 1.8V
V_fixture_min = 1.71V
V_fixture_max = 1.89V
R_fixture = 300Ohm
C_fixture = 0F
|   Time   V(typ)   V(min)   V(max)
0s        1.791V     1.7V       1.881V
429.3ps   1.822V     1.71V      2.014V
473ps     1.829V     1.712V     1.768V
552.4ps   1.862V     1.717V     1.073V
619.4ps   1.911V     1.72V      752.9mV
824.5ps   841mV      1.735V     366.2mV
998.6ps   495.8mV    1.802V     255.1mV
1.337ns   283.1mV    705mV      216.8mV
1.769ns   246.7mV    349.1mV    210.5mV
5ns       240mV      278.9mV    207.5mV
[Rising Waveform]
V_fixture = 0V
V_fixture_min = 0V
V_fixture_max = 0V
R_fixture = 300Ohm
C_fixture = 0F
|   Time   V(typ)   V(min)   V(max)
0s        93.16uV    233.5uV    66.63uV
385.7ps   -124.6mV   -86.82mV   -68.24mV
436.5ps   -110mV     -103.9mV   104.1mV
540.3ps   -19.93mV   -110.6mV   711.3mV
674.8ps   380.3mV    -71.89mV   1.306V
894.1ps   1.126V     45.44mV    1.591V
1.094ns   1.418V     336.6mV    1.621V
1.471ns   1.494V     1.076V     1.636V
1.784ns   1.507V     1.303V     1.64V
5ns       1.519V     1.385V     1.646V
[Rising Waveform]
V_fixture = 1.8V
V_fixture_min = 1.71V
V_fixture_max = 1.89V
R_fixture = 300Ohm
C_fixture = 0F
|   Time   V(typ)   V(min)   V(max)
0s        240mV      278.9mV    207.5mV
229.7ps   213.1mV    276.7mV    162.3mV
321.9ps   233.2mV    243.6mV    281.1mV
415.9ps   382.4mV    315.2mV    543.1mV
630.8ps   924.5mV    665.7mV    1.599V
820.3ps   1.526V     928mV      1.829V
965.7ps   1.705V     1.124V     1.855V
1.201ns   1.762V     1.496V     1.866V
1.444ns   1.775V     1.643V     1.873V
5ns       1.791V     1.7V       1.881V
[Falling Waveform]
|Gnd
V_fixture = 0V
V_fixture_min = 0V
V_fixture_max = 0V
R_fixture = 300Ohm
C_fixture = 0F
|   Time   V(typ)   V(min)   V(max)
0s        1.519V     1.385V     1.646V
429.3ps   1.549V     1.396V     1.763V
459.6ps   1.55V      1.398V     1.6V
539.4ps   1.567V     1.403V     885mV
613.9ps   1.61V      1.403V     571.3mV
792.7ps   659.3mV    1.401V     206.1mV
998.6ps   265.6mV    1.416V     51.37mV
1.281ns   57.87mV    471.6mV    12.49mV
1.769ns   8.251mV    68.61mV    2.895mV
5ns       92.61uV    230.5uV    66.79uV
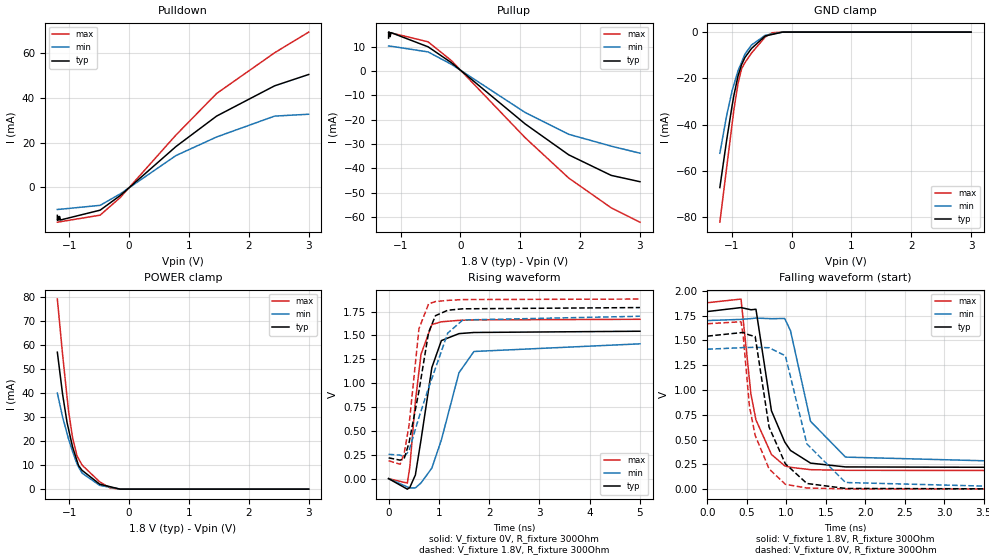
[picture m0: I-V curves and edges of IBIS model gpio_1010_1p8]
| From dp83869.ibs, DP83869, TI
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|   gpio_1010_1p8 Model
[Model]   gpio_1010_1p8
Model_type   I/O
Polarity   Non-Inverting
Enable   Active-Low
Vinl = 0.344
Vinh = 1.204
Vmeas = 0.9
Vref = 0
Cref = 2pF
Rref = 100000
|   typ   min   max
C_comp   1.311pF   1.163pF   1.492pF
| Where Nom  PVT is Nominal Process, 1.8V,  27C
|   Fast PVT is Strong Process,  1.89V, -40C
|   Slow PVT is Weak Process,   1.71V, 125C
[Voltage Range]   1.8   1.71   1.89
|Junction Temperature
[Temperature Range]   27   125   -40
[Pullup Reference]   1.8   1.71   1.89
[Pulldown Reference]   0   0   -0
[Power Clamp Reference]   1.8   1.71   1.89
[GND Clamp Reference]   0   0   0
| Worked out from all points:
|   slope of the pulldown table from 0 to 0.27 V, typ, clamps not added: 41.5 ohm
|   slope of the pullup table from 0 to 0.27 V, typ, clamps not added: 47.6 ohm
|   GND clamp passes 1 mA (typ) near -0.32 V on its own axis
|   POWER clamp passes 1 mA (typ) near -0.31 V on its own axis
|   falling waveform, V_fixture 1.8V, R_fixture 300Ohm: 20-80 % time 246ps typ, 310ps min, 208ps max; typ from 1.79 V to 0.218 V
|   rising waveform, V_fixture 0V, R_fixture 300Ohm: 20-80 % time 268ps typ, 424ps min, 197ps max; typ from 0 V to 1.54 V
|   rising waveform, V_fixture 1.8V, R_fixture 300Ohm: 20-80 % time 299ps typ, 540ps min, 197ps max; typ from 0.218 V to 1.79 V
|   falling waveform, V_fixture 0V, R_fixture 300Ohm: 20-80 % time 274ps typ, 340ps min, 227ps max; typ from 1.54 V to 0 V
[Pulldown]
|   Voltage   I(typ)   I(min)   I(max)
-1.2V     -12.51mA   -9.869mA   -15.55mA
-1.199V   -14.7mA    -9.867mA   -15.55mA
-1.175V   -13.03mA   -9.819mA   -15.44mA
-1.173V   -14.63mA   -9.814mA   -15.43mA
-1.162V   -13.01mA   -9.792mA   -15.39mA
-1.147V   -14.56mA   -9.762mA   -15.32mA
-484.9mV  -10.18mA   -8.031mA   -12.41mA
-149.5mV  -3.654mA   -2.913mA   -4.549mA
782.8mV   18.23mA    14.2mA     23.37mA
1.462V    31.82mA    22.49mA    41.9mA
2.43V     45.31mA    31.8mA     60.06mA
3V        50.38mA    32.64mA    69.3mA
[GND Clamp]
|   Voltage   I(typ)   I(min)   I(max)
-1.2V     -67.24mA   -52.42mA   -82.2mA
-1.087V   -46.84mA   -36.18mA   -58.77mA
-994.8mV  -31.76mA   -25.29mA   -39.68mA
-964.7mV  -27.32mA   -22.68mA   -33.44mA
-896.6mV  -19.01mA   -16.78mA   -22.3mA
-837.6mV  -14.13mA   -13.08mA   -15.89mA
-780.3mV  -10.96mA   -9.506mA   -13.2mA
-671.4mV  -7.108mA   -5.597mA   -9.091mA
-441mV    -1.677mA   -1.369mA   -2.104mA
-326mV    -1.015mA   -830.6uA   -284.3uA
-149.5mV  -2.217uA   -4.045uA   -2.26uA
3V        0A         0A         0A
[Pullup]
|   Voltage   I(typ)   I(min)   I(max)
-1.2V     13.5mA     10.26mA    15.89mA
-1.199V   15.97mA    10.25mA    15.88mA
-1.187V   14.25mA    10.22mA    15.81mA
-1.186V   15.91mA    10.22mA    15.8mA
-1.175V   14.06mA    10.19mA    15.74mA
-1.16V    15.75mA    10.16mA    15.65mA
-539.8mV  9.924mA    7.824mA    11.98mA
-149.5mV  3.386mA    2.723mA    4.219mA
1.083V    -21.76mA   -17.07mA   -27.43mA
1.81V     -34.44mA   -26mA      -43.97mA
2.52V     -42.88mA   -30.87mA   -56.2mA
3V        -45.47mA   -33.76mA   -62.1mA
[POWER Clamp]
|   Voltage   I(typ)   I(min)   I(max)
-1.2V     57.06mA    40.03mA    79.18mA
-1.112V   39.49mA    30mA       56.03mA
-1.038V   27.79mA    23.21mA    38.39mA
-1.012V   24.89mA    20.82mA    32.46mA
-946.6mV  17.69mA    15.74mA    21.62mA
-873.2mV  11.92mA    10.66mA    13.97mA
-845.4mV  9.817mA    9.193mA    12.7mA
-786.6mV  7.832mA    6.674mA    10.03mA
-492.1mV  2.077mA    1.585mA    3.05mA
-321.5mV  1.043mA    799.2uA    552.2uA
-149.5mV  3.239uA    7.462uA    3.472uA
3V        0A         0A         0A
[Ramp]
R_load = 300
|   typ   min   max
dV/dt_r   0.926118/2.67683e-10   0.846914/4.23556e-10   1.00119/1.9663e-10
dV/dt_f   0.944256/2.45414e-10   0.86764/3.0853e-10   1.01652/2.08029e-10
[Falling Waveform]
V_fixture = 1.8V
V_fixture_min = 1.71V
V_fixture_max = 1.89V
R_fixture = 300Ohm
C_fixture = 0F
|   Time   V(typ)   V(min)   V(max)
0s        1.792V     1.701V     1.881V
427.4ps   1.832V     1.713V     1.918V
553.7ps   1.81V      1.721V     954.4mV
616.6ps   1.815V     1.726V     698.7mV
812.6ps   791.3mV    1.72V      350.6mV
980.7ps   476.6mV    1.722V     235.4mV
1.054ns   390.7mV    1.599V     220.7mV
1.308ns   262.9mV    684.8mV    196.6mV
1.751ns   224.5mV    323.5mV    190.1mV
5ns       217.8mV    255mV      187.3mV
[Rising Waveform]
V_fixture = 0V
V_fixture_min = 0V
V_fixture_max = 0V
R_fixture = 300Ohm
C_fixture = 0F
|   Time   V(typ)   V(min)   V(max)
0s        84.29uV    211.4uV    59.91uV
373ps     -110.3mV   -87.03mV   -46.47mV
421.7ps   -92.9mV    -97mV      119.7mV
532.6ps   37.75mV    -97.03mV   808.9mV
645.4ps   406.9mV    -44.76mV   1.304V
860.9ps   1.164V     110.9mV    1.614V
1.05ns    1.446V     405.8mV    1.643V
1.4ns     1.519V     1.109V     1.658V
1.698ns   1.531V     1.332V     1.663V
5ns       1.544V     1.412V     1.669V
[Rising Waveform]
V_fixture = 1.8V
V_fixture_min = 1.71V
V_fixture_max = 1.89V
R_fixture = 300Ohm
C_fixture = 0F
|   Time   V(typ)   V(min)   V(max)
0s        217.8mV    255mV      187.3mV
228.7ps   193.6mV    246.2mV    150.5mV
309.7ps   209.8mV    230.3mV    263.6mV
404.9ps   371.8mV    289.4mV    549.9mV
604ps     917.5mV    642.3mV    1.57V
795.5ps   1.533V     950mV      1.831V
932.8ps   1.707V     1.157V     1.855V
1.177ns   1.764V     1.525V     1.867V
1.477ns   1.779V     1.662V     1.876V
5ns       1.792V     1.701V     1.881V
[Falling Waveform]
|Gnd
V_fixture = 0V
V_fixture_min = 0V
V_fixture_max = 0V
R_fixture = 300Ohm
C_fixture = 0F
|   Time   V(typ)   V(min)   V(max)
0s        1.544V     1.412V     1.669V
427.4ps   1.579V     1.427V     1.689V
453.9ps   1.581V     1.429V     1.558V
533.6ps   1.555V     1.43V      839.7mV
606.6ps   1.541V     1.431V     543.1mV
782.7ps   626.3mV    1.427V     204.6mV
989.1ps   255.9mV    1.346V     48.95mV
1.262ns   57.35mV    456.2mV    11.99mV
1.751ns   7.51mV     67.24mV    2.73mV
5ns       83.67uV    208.5uV    59.61uV
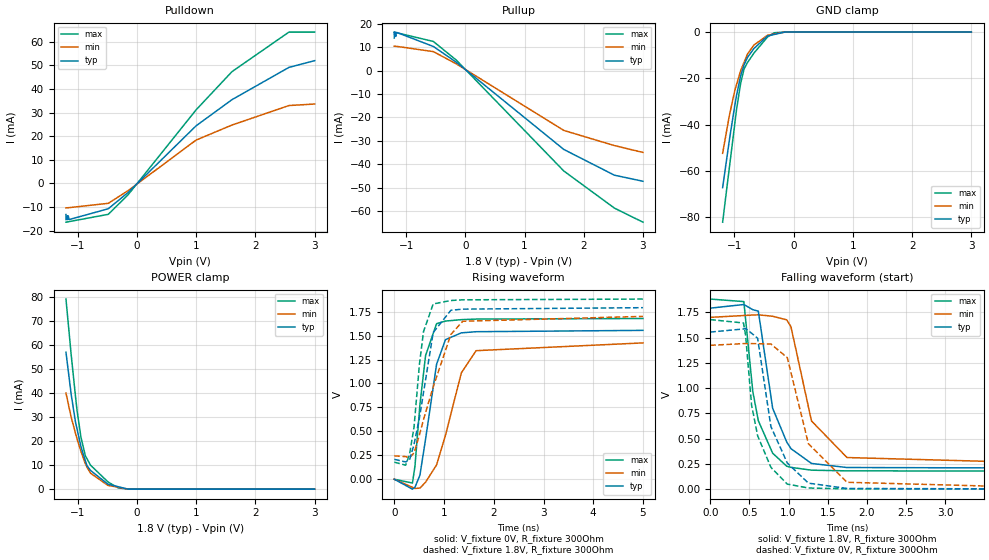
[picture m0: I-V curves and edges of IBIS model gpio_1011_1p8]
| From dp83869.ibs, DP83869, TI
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|   gpio_1011_1p8 Model
[Model]   gpio_1011_1p8
Model_type   I/O
Polarity   Non-Inverting
Enable   Active-Low
Vinl = 0.344
Vinh = 1.204
Vmeas = 0.9
Vref = 0
Cref = 2pF
Rref = 100000
|   typ   min   max
C_comp   1.311pF   1.163pF   1.492pF
| Where Nom  PVT is Nominal Process, 1.8V,  27C
|   Fast PVT is Strong Process,  1.89V, -40C
|   Slow PVT is Weak Process,   1.71V, 125C
[Voltage Range]   1.8   1.71   1.89
|Junction Temperature
[Temperature Range]   27   125   -40
[Pullup Reference]   1.8   1.71   1.89
[Pulldown Reference]   0   -0   -0
[Power Clamp Reference]   1.8   1.71   1.89
[GND Clamp Reference]   0   0   0
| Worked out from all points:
|   slope of the pulldown table from 0 to 0.27 V, typ, clamps not added: 40.4 ohm
|   slope of the pullup table from 0 to 0.27 V, typ, clamps not added: 46.3 ohm
|   GND clamp passes 1 mA (typ) near -0.32 V on its own axis
|   POWER clamp passes 1 mA (typ) near -0.31 V on its own axis
|   falling waveform, V_fixture 1.8V, R_fixture 300Ohm: 20-80 % time 250ps typ, 315ps min, 212ps max; typ from 1.79 V to 0.208 V
|   rising waveform, V_fixture 0V, R_fixture 300Ohm: 20-80 % time 266ps typ, 422ps min, 197ps max; typ from 0 V to 1.55 V
|   rising waveform, V_fixture 1.8V, R_fixture 300Ohm: 20-80 % time 295ps typ, 518ps min, 196ps max; typ from 0.208 V to 1.79 V
|   falling waveform, V_fixture 0V, R_fixture 300Ohm: 20-80 % time 279ps typ, 347ps min, 230ps max; typ from 1.55 V to 0 V
[Pulldown]
|   Voltage   I(typ)   I(min)   I(max)
-1.2V     -13.21mA   -10.4mA    -16.45mA
-1.199V   -15.44mA   -10.39mA   -16.45mA
-1.174V   -13.8mA    -10.34mA   -16.33mA
-1.172V   -15.37mA   -10.34mA   -16.32mA
-1.161V   -13.78mA   -10.31mA   -16.27mA
-1.146V   -15.33mA   -10.28mA   -16.2mA
-485.4mV  -10.76mA   -8.468mA   -13.12mA
-149.7mV  -3.855mA   -3.066mA   -4.804mA
997.6mV   24.37mA    18.33mA    31.13mA
1.604V    35.45mA    24.7mA     47.32mA
2.566V    49.12mA    32.96mA    64.07mA
3V        51.97mA    33.6mA     64.07mA
[GND Clamp]
|   Voltage   I(typ)   I(min)   I(max)
-1.2V     -67.24mA   -52.42mA   -82.2mA
-1.087V   -46.83mA   -36.17mA   -58.77mA
-994.8mV  -31.76mA   -25.29mA   -39.68mA
-964.8mV  -27.33mA   -22.69mA   -33.47mA
-896.3mV  -18.98mA   -16.76mA   -22.26mA
-837.8mV  -14.14mA   -13.09mA   -15.9mA
-780.3mV  -10.96mA   -9.506mA   -13.19mA
-671.4mV  -7.109mA   -5.597mA   -9.093mA
-441.1mV  -1.679mA   -1.37mA    -2.107mA
-326.1mV  -1.017mA   -831.2uA   -285.3uA
-149.7mV  -2.225uA   -4.33uA    -2.27uA
3V        0A         0A         0A
[Pullup]
|   Voltage   I(typ)   I(min)   I(max)
-1.2V     13.95mA    10.44mA    16.44mA
-1.199V   16.47mA    10.44mA    16.43mA
-1.189V   14.66mA    10.42mA    16.37mA
-1.186V   16.41mA    10.41mA    16.35mA
-1.175V   14.61mA    10.39mA    16.29mA
-1.172V   16.33mA    10.38mA    16.27mA
-1.146V   16.21mA    10.32mA    16.11mA
-539.9mV  10.32mA    8.123mA    12.46mA
-149.7mV  3.55mA     2.85mA     4.427mA
1.663V    -33.68mA   -25.55mA   -42.89mA
2.518V    -44.68mA   -32.03mA   -58.75mA
3V        -47.27mA   -34.95mA   -64.76mA
[POWER Clamp]
|   Voltage   I(typ)   I(min)   I(max)
-1.2V     57.06mA    40.03mA    79.18mA
-1.112V   39.5mA     30mA       56.05mA
-1.038V   27.79mA    23.21mA    38.4mA
-1.011V   24.86mA    20.79mA    32.41mA
-946.3mV  17.66mA    15.72mA    21.58mA
-872.3mV  11.85mA    10.6mA     13.9mA
-845.4mV  9.819mA    9.194mA    12.69mA
-785.8mV  7.808mA    6.656mA    10.01mA
-491.8mV  2.079mA    1.583mA    3.045mA
-321.3mV  1.043mA    797.9uA    549.8uA
-149.7mV  3.255uA    7.722uA    3.492uA
3V        0A         0A         0A
[Ramp]
R_load = 300
|   typ   min   max
dV/dt_r   0.932702/2.65029e-10   0.854128/4.20899e-10   1.00711/1.95731e-10
dV/dt_f   0.9504/2.49118e-10   0.874317/3.13461e-10   1.02206/2.10931e-10
[Falling Waveform]
V_fixture = 1.8V
V_fixture_min = 1.71V
V_fixture_max = 1.89V
R_fixture = 300Ohm
C_fixture = 0F
|   Time   V(typ)   V(min)   V(max)
0s        1.792V     1.701V     1.882V
429.4ps   1.828V     1.719V     1.857V
543.7ps   1.777V     1.724V     968mV
614.5ps   1.762V     1.726V     677.1mV
797.5ps   800.4mV    1.712V     356mV
976.9ps   467.1mV    1.676V     227.5mV
1.031ns   401.1mV    1.608V     215.8mV
1.293ns   254.6mV    675.6mV    188.1mV
1.746ns   214.4mV    313.1mV    181.3mV
5ns       207.9mV    244.3mV    178.4mV
[Rising Waveform]
V_fixture = 0V
V_fixture_min = 0V
V_fixture_max = 0V
R_fixture = 300Ohm
C_fixture = 0F
|   Time   V(typ)   V(min)   V(max)
0s        80.79uV    202uV      56.56uV
365.2ps   -103.8mV   -84.58mV   -39.87mV
416ps     -83.53mV   -96.47mV   138.3mV
515.3ps   42.14mV    -92.44mV   778.5mV
628.9ps   418.9mV    -31.02mV   1.292V
850.4ps   1.201V     150.1mV    1.625V
1.029ns   1.458V     458.9mV    1.652V
1.348ns   1.529V     1.111V     1.667V
1.645ns   1.541V     1.343V     1.673V
5ns       1.555V     1.424V     1.679V
[Rising Waveform]
V_fixture = 1.8V
V_fixture_min = 1.71V
V_fixture_max = 1.89V
R_fixture = 300Ohm
C_fixture = 0F
|   Time   V(typ)   V(min)   V(max)
0s        207.9mV    244.3mV    178.4mV
228.2ps   180.5mV    236.3mV    146.5mV
306.4ps   202.8mV    223.7mV    261.1mV
397.1ps   363.7mV    274.6mV    546mV
505ps     638.5mV    461.7mV    1.198V
587.8ps   906.8mV    624.5mV    1.543V
782.3ps   1.533V     964.4mV    1.831V
1.138ns   1.765V     1.513V     1.867V
1.377ns   1.777V     1.65V      1.874V
5ns       1.792V     1.701V     1.882V
[Falling Waveform]
|Gnd
V_fixture = 0V
V_fixture_min = 0V
V_fixture_max = 0V
R_fixture = 300Ohm
C_fixture = 0F
|   Time   V(typ)   V(min)   V(max)
0s        1.555V     1.424V     1.679V
425ps     1.586V     1.441V     1.645V
451.9ps   1.589V     1.441V     1.523V
528.1ps   1.544V     1.441V     834.4mV
605.2ps   1.494V     1.44V      529.9mV
775.1ps   619.3mV    1.437V     215.9mV
984.2ps   259.4mV    1.302V     50.23mV
1.254ns   59.57mV    449.1mV    11.58mV
1.746ns   7.214mV    68.09mV    2.779mV
5ns       80.24uV    199.1uV    56.7uV
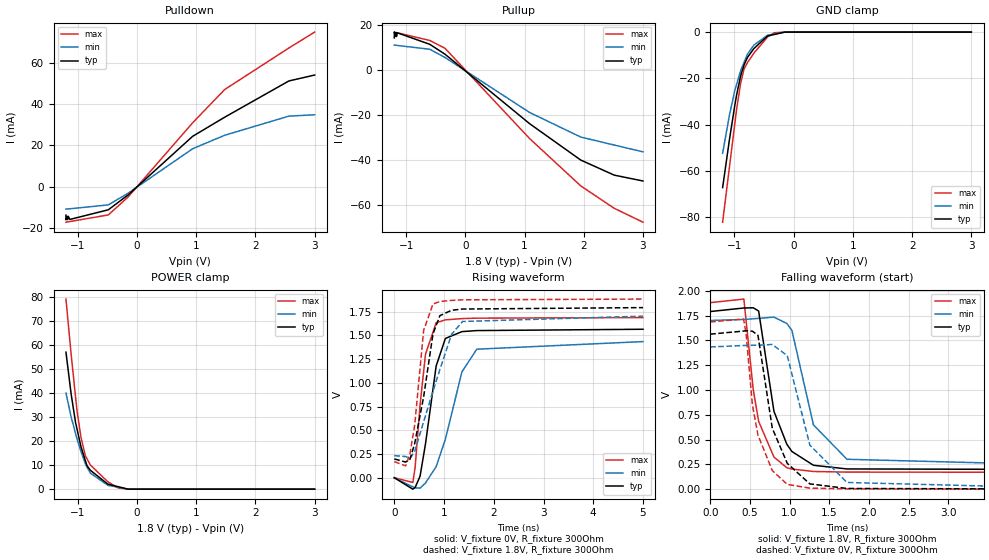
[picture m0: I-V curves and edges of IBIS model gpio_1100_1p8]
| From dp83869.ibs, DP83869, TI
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|   gpio_1100_1p8 Model
[Model]   gpio_1100_1p8
Model_type   I/O
Polarity   Non-Inverting
Enable   Active-Low
Vinl = 0.344
Vinh = 1.204
Vmeas = 0.9
Vref = 0
Cref = 2pF
Rref = 100000
|   typ   min   max
C_comp   1.311pF   1.163pF   1.492pF
| Where Nom  PVT is Nominal Process, 1.8V,  27C
|   Fast PVT is Strong Process,  1.89V, -40C
|   Slow PVT is Weak Process,   1.71V, 125C
[Voltage Range]   1.8   1.71   1.89
|Junction Temperature
[Temperature Range]   27   125   -40
[Pullup Reference]   1.8   1.71   1.89
[Pulldown Reference]   -0   -0   0
[Power Clamp Reference]   1.8   1.71   1.89
[GND Clamp Reference]   0   0   0
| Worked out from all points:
|   slope of the pulldown table from 0 to 0.27 V, typ, clamps not added: 37.2 ohm
|   slope of the pullup table from 0 to 0.27 V, typ, clamps not added: 43.2 ohm
|   GND clamp passes 1 mA (typ) near -0.32 V on its own axis
|   POWER clamp passes 1 mA (typ) near -0.31 V on its own axis
|   falling waveform, V_fixture 1.8V, R_fixture 300Ohm: 20-80 % time 239ps typ, 306ps min, 201ps max; typ from 1.79 V to 0.198 V
|   rising waveform, V_fixture 0V, R_fixture 300Ohm: 20-80 % time 255ps typ, 413ps min, 186ps max; typ from 0 V to 1.56 V
|   rising waveform, V_fixture 1.8V, R_fixture 300Ohm: 20-80 % time 285ps typ, 521ps min, 186ps max; typ from 0.198 V to 1.79 V
|   falling waveform, V_fixture 0V, R_fixture 300Ohm: 20-80 % time 262ps typ, 329ps min, 216ps max; typ from 1.56 V to 0 V
[Pulldown]
|   Voltage   I(typ)   I(min)   I(max)
-1.2V     -13.97mA   -11mA      -17.39mA
-1.199V   -16.24mA   -11mA      -17.38mA
-1.176V   -14.57mA   -10.95mA   -17.27mA
-1.173V   -16.12mA   -10.94mA   -17.25mA
-1.161V   -14.53mA   -10.92mA   -17.2mA
-1.133V   -16.04mA   -10.85mA   -17.06mA
-485.2mV  -11.35mA   -8.952mA   -13.86mA
-149.8mV  -4.077mA   -3.245mA   -5.079mA
939.1mV   24.47mA    18.41mA    31.06mA
1.481V    33.8mA     24.99mA    47.29mA
2.565V    51.47mA    34.32mA    67.54mA
3V        54.35mA    34.97mA    75.29mA
[GND Clamp]
|   Voltage   I(typ)   I(min)   I(max)
-1.2V     -67.24mA   -52.42mA   -82.2mA
-1.087V   -46.85mA   -36.19mA   -58.79mA
-994.9mV  -31.78mA   -25.3mA    -39.71mA
-965mV    -27.35mA   -22.7mA    -33.5mA
-896.4mV  -19mA      -16.77mA   -22.28mA
-837.9mV  -14.15mA   -13.1mA    -15.91mA
-780.4mV  -10.96mA   -9.514mA   -13.2mA
-671.6mV  -7.113mA   -5.601mA   -9.098mA
-441.5mV  -1.681mA   -1.373mA   -2.116mA
-326.3mV  -1.017mA   -832.4uA   -286.5uA
-149.8mV  -2.231uA   -4.067uA   -2.278uA
3V        0A         0A         0A
[Pullup]
|   Voltage   I(typ)   I(min)   I(max)
-1.2V     14.43mA    11.24mA    16.98mA
-1.199V   17.01mA    11.24mA    16.98mA
-1.176V   15.09mA    11.16mA    16.83mA
-1.173V   16.82mA    11.16mA    16.82mA
-1.163V   15.05mA    11.12mA    16.75mA
-1.147V   16.69mA    11.07mA    16.66mA
-601.3mV  11.58mA    9.378mA    13.3mA
-343.6mV  7.189mA    5.725mA    9.808mA
1.085V    -23.69mA   -18.72mA   -30.31mA
1.949V    -39.87mA   -29.64mA   -51.35mA
2.514V    -46.56mA   -33.19mA   -61.3mA
3V        -49.17mA   -36.22mA   -67.48mA
[POWER Clamp]
|   Voltage   I(typ)   I(min)   I(max)
-1.2V     57.06mA    40.03mA    79.18mA
-1.112V   39.49mA    30mA       56.04mA
-1.038V   27.79mA    23.21mA    38.39mA
-1.012V   24.88mA    20.81mA    32.44mA
-946.5mV  17.67mA    15.73mA    21.6mA
-873.1mV  11.91mA    10.65mA    13.96mA
-845.4mV  9.818mA    9.192mA    12.7mA
-786.4mV  7.828mA    6.67mA     10.03mA
-492mV    2.077mA    1.585mA    3.048mA
-321.4mV  1.043mA    798.6uA    551.2uA
-149.8mV  3.263uA    7.48uA     3.505uA
3V        0A         0A         0A
[Ramp]
R_load = 300
|   typ   min   max
dV/dt_r   0.938444/2.54378e-10   0.860272/4.12767e-10   1.01235/1.8468e-10
dV/dt_f   0.956599/2.38603e-10   0.88146/3.0254e-10   1.02749/2.00954e-10
[Falling Waveform]
V_fixture = 1.8V
V_fixture_min = 1.71V
V_fixture_max = 1.89V
R_fixture = 300Ohm
C_fixture = 0F
|   Time   V(typ)   V(min)   V(max)
0s        1.792V     1.702V     1.882V
423.7ps   1.828V     1.712V     1.918V
542ps     1.83V      1.719V     1.004V
609.9ps   1.797V     1.723V     684.2mV
802.6ps   785.5mV    1.736V     323.9mV
964.8ps   453.2mV    1.672V     216.5mV
1.029ns   380mV      1.601V     203.4mV
1.3ns     241.1mV    648.5mV    178.3mV
1.722ns   204.1mV    301.6mV    172.4mV
5ns       197.9mV    232.6mV    169.7mV
[Rising Waveform]
V_fixture = 0V
V_fixture_min = 0V
V_fixture_max = 0V
R_fixture = 300Ohm
C_fixture = 0F
|   Time   V(typ)   V(min)   V(max)
0s        76.16uV    191.2uV    53.97uV
372.7ps   -120.4mV   -96.34mV   -49.83mV
419.7ps   -102.4mV   -106.3mV   112.9mV
518.2ps   16.38mV    -109.5mV   767.7mV
627.2ps   356.2mV    -55.57mV   1.3V
842.2ps   1.178V     117.3mV    1.633V
1.027ns   1.467V     406.2mV    1.663V
1.36ns    1.539V     1.115V     1.676V
1.658ns   1.55V      1.354V     1.681V
5ns       1.564V     1.434V     1.687V
[Rising Waveform]
V_fixture = 1.8V
V_fixture_min = 1.71V
V_fixture_max = 1.89V
R_fixture = 300Ohm
C_fixture = 0F
|   Time   V(typ)   V(min)   V(max)
0s        197.9mV    232.6mV    169.7mV
228.8ps   165mV      223.2mV    125.5mV
315.8ps   195.1mV    202.9mV    255.8mV
410.3ps   360.7mV    277.2mV    555.1mV
590.3ps   854.5mV    590.9mV    1.552V
778ps     1.515V     910.9mV    1.831V
916.1ps   1.707V     1.139V     1.856V
1.151ns   1.764V     1.51V      1.868V
1.372ns   1.777V     1.646V     1.874V
5ns       1.792V     1.702V     1.882V
[Falling Waveform]
|Gnd
V_fixture = 0V
V_fixture_min = 0V
V_fixture_max = 0V
R_fixture = 300Ohm
C_fixture = 0F
|   Time   V(typ)   V(min)   V(max)
0s        1.564V     1.435V     1.687V
420.3ps   1.595V     1.449V     1.717V
451.5ps   1.598V     1.451V     1.569V
531.2ps   1.594V     1.452V     851.2mV
601.6ps   1.552V     1.452V     545.1mV
781.9ps   614.4mV    1.46V      186.9mV
970.5ps   260.3mV    1.347V     48.03mV
1.254ns   53.35mV    445.8mV    10.68mV
1.722ns   7.105mV    67.59mV    2.653mV
5ns       75.69uV    188.3uV    53.95uV
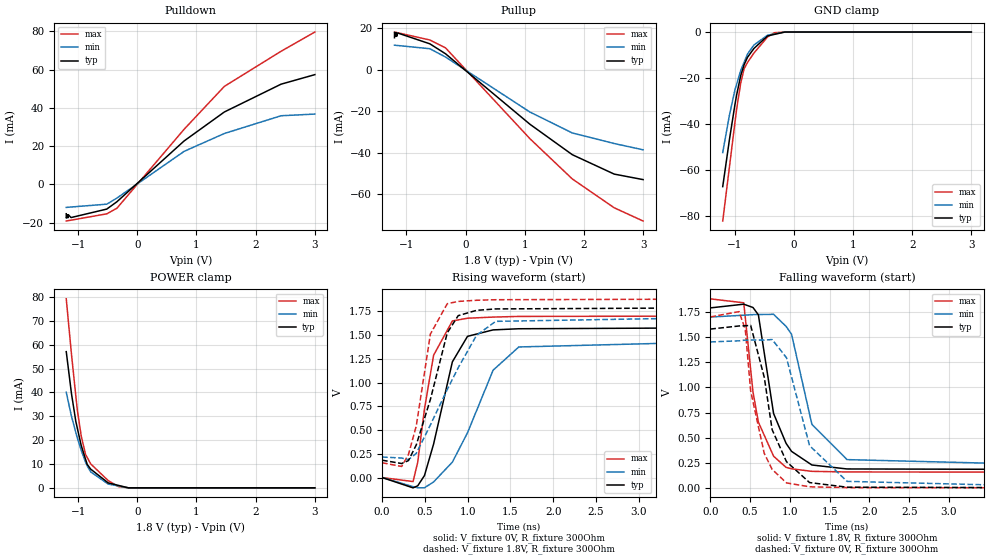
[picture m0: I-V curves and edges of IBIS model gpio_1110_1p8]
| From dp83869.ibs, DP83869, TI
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|   gpio_1110_1p8 Model
[Model]   gpio_1110_1p8
Model_type   I/O
Polarity   Non-Inverting
Enable   Active-Low
Vinl = 0.344
Vinh = 1.204
Vmeas = 0.9
Vref = 0
Cref = 2pF
Rref = 100000
|   typ   min   max
C_comp   1.311pF   1.163pF   1.492pF
| Where Nom  PVT is Nominal Process, 1.8V,  27C
|   Fast PVT is Strong Process,  1.89V, -40C
|   Slow PVT is Weak Process,   1.71V, 125C
[Voltage Range]   1.8   1.71   1.89
|Junction Temperature
[Temperature Range]   27   125   -40
[Pullup Reference]   1.8   1.71   1.89
[Pulldown Reference]   0   0   0
[Power Clamp Reference]   1.8   1.71   1.89
[GND Clamp Reference]   0   0   0
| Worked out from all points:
|   slope of the pulldown table from 0 to 0.27 V, typ, clamps not added: 34.1 ohm
|   slope of the pullup table from 0 to 0.27 V, typ, clamps not added: 39.6 ohm
|   GND clamp passes 1 mA (typ) near -0.32 V on its own axis
|   POWER clamp passes 1 mA (typ) near -0.31 V on its own axis
|   falling waveform, V_fixture 1.8V, R_fixture 300Ohm: 20-80 % time 241ps typ, 305ps min, 201ps max; typ from 1.79 V to 0.182 V
|   rising waveform, V_fixture 0V, R_fixture 300Ohm: 20-80 % time 248ps typ, 408ps min, 181ps max; typ from 0 V to 1.58 V
|   rising waveform, V_fixture 1.8V, R_fixture 300Ohm: 20-80 % time 275ps typ, 490ps min, 181ps max; typ from 0.182 V to 1.79 V
|   falling waveform, V_fixture 0V, R_fixture 300Ohm: 20-80 % time 259ps typ, 334ps min, 214ps max; typ from 1.58 V to 0 V
[Pulldown]
|   Voltage   I(typ)   I(min)   I(max)
-1.2V     -15.35mA   -12.04mA   -19.16mA
-1.199V   -17.62mA   -12.03mA   -19.15mA
-1.176V   -15.94mA   -11.98mA   -19.02mA
-1.173V   -17.5mA    -11.97mA   -19.01mA
-1.163V   -15.91mA   -11.94mA   -18.95mA
-1.12V    -17.36mA   -11.84mA   -18.72mA
-515.7mV  -12.92mA   -10.35mA   -15.41mA
-343.5mV  -9.068mA   -7.147mA   -12.45mA
791.1mV   22.72mA    17.27mA    28.83mA
1.471V    37.88mA    26.62mA    51.27mA
2.429V    52.42mA    35.9mA     69.64mA
3V        57.41mA    36.78mA    79.7mA
[GND Clamp]
|   Voltage   I(typ)   I(min)   I(max)
-1.2V     -67.24mA   -52.42mA   -82.2mA
-1.087V   -46.85mA   -36.19mA   -58.79mA
-994.9mV  -31.78mA   -25.3mA    -39.7mA
-964.9mV  -27.35mA   -22.7mA    -33.49mA
-896.4mV  -18.99mA   -16.76mA   -22.28mA
-837.9mV  -14.15mA   -13.1mA    -15.91mA
-780.4mV  -10.96mA   -9.513mA   -13.2mA
-672mV    -7.123mA   -5.611mA   -9.111mA
-441.4mV  -1.681mA   -1.374mA   -2.115mA
-326.2mV  -1.017mA   -832.4uA   -286.2uA
-149.7mV  -2.231uA   -4.065uA   -2.275uA
3V        0A         0A         0A
[Pullup]
|   Voltage   I(typ)   I(min)   I(max)
-1.2V     15.34mA    11.76mA    18.08mA
-1.199V   17.95mA    11.76mA    18.08mA
-1.176V   16.03mA    11.69mA    17.93mA
-1.173V   17.75mA    11.68mA    17.91mA
-1.163V   15.99mA    11.65mA    17.84mA
-1.147V   17.62mA    11.61mA    17.74mA
-603mV    12.42mA    10.06mA    14.26mA
-338.2mV  7.636mA    6.068mA    10.48mA
1.088V    -26.25mA   -20.38mA   -33.2mA
1.804V    -40.89mA   -30.45mA   -52.55mA
2.512V    -50.22mA   -35.52mA   -66.42mA
3V        -52.87mA   -38.54mA   -72.78mA
[POWER Clamp]
|   Voltage   I(typ)   I(min)   I(max)
-1.2V     57.06mA    40.03mA    79.18mA
-1.112V   39.5mA     30mA       56.04mA
-1.038V   27.79mA    23.21mA    38.4mA
-1.012V   24.88mA    20.8mA     32.43mA
-946.4mV  17.67mA    15.72mA    21.6mA
-873.1mV  11.91mA    10.64mA    13.95mA
-845.4mV  9.819mA    9.193mA    12.7mA
-786.4mV  7.826mA    6.668mA    10.02mA
-491.9mV  2.08mA     1.585mA    3.047mA
-321.4mV  1.044mA    798.4uA    550.8uA
-149.7mV  3.259uA    7.49uA     3.5uA
3V        0A         0A         0A
[Ramp]
R_load = 300
|   typ   min   max
dV/dt_r   0.949118/2.46752e-10   0.872091/4.07707e-10   1.02188/1.79398e-10
dV/dt_f   0.966196/2.38866e-10   0.891937/3.04372e-10   1.03613/2.00295e-10
[Falling Waveform]
V_fixture = 1.8V
V_fixture_min = 1.71V
V_fixture_max = 1.89V
R_fixture = 300Ohm
C_fixture = 0F
|   Time   V(typ)   V(min)   V(max)
0s        1.793V     1.702V     1.883V
420.6ps   1.83V      1.72V      1.844V
536.7ps   1.797V     1.726V     956.1mV
604.6ps   1.724V     1.727V     655mV
795.6ps   741.1mV    1.729V     315.5mV
952.6ps   443.8mV    1.609V     204mV
1.022ns   363.1mV    1.53V      189.9mV
1.277ns   227.8mV    633.4mV    164.5mV
1.719ns   188.3mV    281.4mV    158.4mV
5ns       182.5mV    215.7mV    155.9mV
[Rising Waveform]
V_fixture = 0V
V_fixture_min = 0V
V_fixture_max = 0V
R_fixture = 300Ohm
C_fixture = 0F
|   Time   V(typ)   V(min)   V(max)
0s        70.36uV    176.2uV    49.34uV
362ps     -108.9mV   -96.32mV   -42.86mV
416.5ps   -87.44mV   -108.5mV   160.6mV
495.1ps   20.2mV     -108.3mV   721.1mV
602ps     352.9mV    -46.49mV   1.289V
821.1ps   1.219V     162mV      1.65V
998ps     1.488V     471.6mV    1.679V
1.297ns   1.556V     1.131V     1.691V
1.597ns   1.568V     1.376V     1.698V
5ns       1.582V     1.454V     1.703V
[Rising Waveform]
V_fixture = 1.8V
V_fixture_min = 1.71V
V_fixture_max = 1.89V
R_fixture = 300Ohm
C_fixture = 0F
|   Time   V(typ)   V(min)   V(max)
0s        182.5mV    215.7mV    155.9mV
228.5ps   147.6mV    205.4mV    116.7mV
308.4ps   178.4mV    188.4mV    242.8mV
399.6ps   343.5mV    253.5mV    543mV
564.4ps   822.9mV    553.9mV    1.512V
761.7ps   1.525V     927.9mV    1.832V
889.3ps   1.706V     1.157V     1.856V
1.103ns   1.762V     1.498V     1.868V
1.327ns   1.777V     1.646V     1.874V
5ns       1.793V     1.702V     1.883V
[Falling Waveform]
|Gnd
V_fixture = 0V
V_fixture_min = 0V
V_fixture_max = 0V
R_fixture = 300Ohm
C_fixture = 0F
|   Time   V(typ)   V(min)   V(max)
0s        1.582V     1.454V     1.703V
362ps     1.613V     1.465V     1.756V
440.1ps   1.615V     1.472V     1.577V
507.6ps   1.619V     1.473V     964.9mV
678.6ps   1.101V     1.472V     342.9mV
777.6ps   579.1mV    1.478V     184.1mV
957.6ps   261.3mV    1.297V     49.4mV
1.248ns   52.6mV     420.3mV    10.35mV
1.719ns   6.547mV    64.78mV    2.459mV
5ns       69.84uV    173.4uV    49.36uV
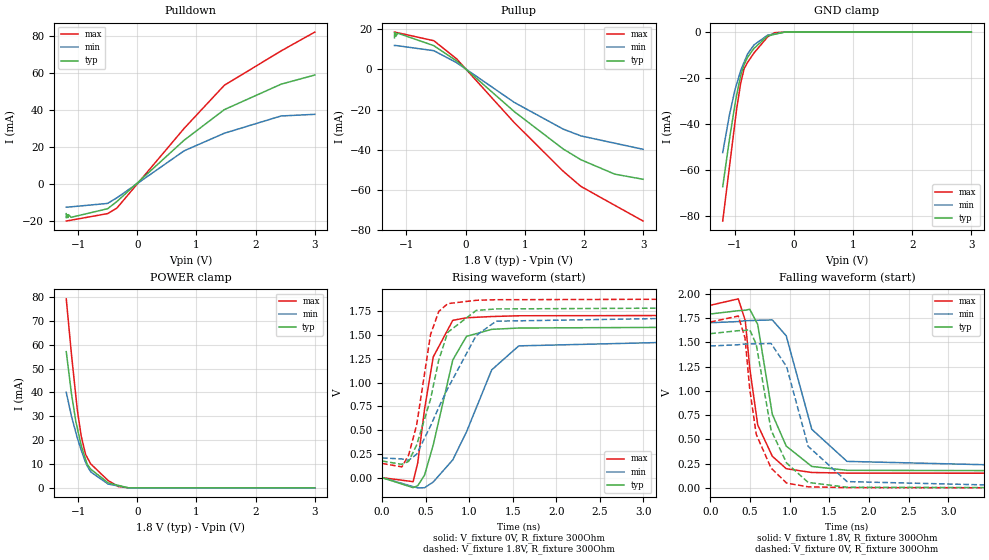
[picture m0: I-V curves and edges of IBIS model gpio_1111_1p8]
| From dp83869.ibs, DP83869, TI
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|   gpio_1111_1p8 Model
[Model]   gpio_1111_1p8
Model_type   I/O
Polarity   Non-Inverting
Enable   Active-Low
Vinl = 0.344
Vinh = 1.204
Vmeas = 0.9
Vref = 0
Cref = 2pF
Rref = 100000
|   typ   min   max
C_comp   1.311pF   1.163pF   1.492pF
| Where Nom  PVT is Nominal Process, 1.8V,  27C
|   Fast PVT is Strong Process,  1.89V, -40C
|   Slow PVT is Weak Process,   1.71V, 125C
[Voltage Range]   1.8   1.71   1.89
|Junction Temperature
[Temperature Range]   27   125   -40
[Pullup Reference]   1.8   1.71   1.89
[Pulldown Reference]   0   0   -0
[Power Clamp Reference]   1.8   1.71   1.89
[GND Clamp Reference]   0   0   0
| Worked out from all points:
|   slope of the pulldown table from 0 to 0.27 V, typ, clamps not added: 32.7 ohm
|   slope of the pullup table from 0 to 0.27 V, typ, clamps not added: 38.1 ohm
|   GND clamp passes 1 mA (typ) near -0.32 V on its own axis
|   POWER clamp passes 1 mA (typ) near -0.31 V on its own axis
|   falling waveform, V_fixture 1.8V, R_fixture 300Ohm: 20-80 % time 244ps typ, 314ps min, 205ps max; typ from 1.79 V to 0.175 V
|   rising waveform, V_fixture 0V, R_fixture 300Ohm: 20-80 % time 245ps typ, 403ps min, 179ps max; typ from 0 V to 1.59 V
|   rising waveform, V_fixture 1.8V, R_fixture 300Ohm: 20-80 % time 270ps typ, 473ps min, 180ps max; typ from 0.175 V to 1.79 V
|   falling waveform, V_fixture 0V, R_fixture 300Ohm: 20-80 % time 266ps typ, 346ps min, 218ps max; typ from 1.59 V to 0 V
[Pulldown]
|   Voltage   I(typ)   I(min)   I(max)
-1.2V     -16.06mA   -12.56mA   -20.05mA
-1.199V   -18.32mA   -12.56mA   -20.05mA
-1.175V   -16.65mA   -12.5mA    -19.91mA
-1.173V   -18.2mA    -12.49mA   -19.9mA
-1.162V   -16.61mA   -12.47mA   -19.84mA
-1.119V   -18.06mA   -12.36mA   -19.59mA
-501mV    -13.39mA   -10.52mA   -16.04mA
-343.6mV  -9.476mA   -7.459mA   -13.02mA
791.5mV   23.72mA    17.98mA    30.13mA
1.471V    40.3mA     27.5mA     53.49mA
2.43V     54.08mA    36.86mA    72.1mA
3V        59.05mA    37.75mA    82.33mA
[GND Clamp]
|   Voltage   I(typ)   I(min)   I(max)
-1.2V     -67.24mA   -52.42mA   -82.2mA
-1.087V   -46.78mA   -36.14mA   -58.71mA
-994.6mV  -31.72mA   -25.26mA   -39.63mA
-964.6mV  -27.31mA   -22.67mA   -33.43mA
-896.5mV  -19mA      -16.78mA   -22.29mA
-837.6mV  -14.12mA   -13.07mA   -15.88mA
-780mV    -10.95mA   -9.495mA   -13.19mA
-671.2mV  -7.103mA   -5.591mA   -9.084mA
-440.9mV  -1.683mA   -1.365mA   -2.103mA
-325.9mV  -1.019mA   -827.6uA   -284uA
-149.4mV  -2.21uA    -4.037uA   -2.253uA
3V        0A         0A         0A
[Pullup]
|   Voltage   I(typ)   I(min)   I(max)
-1.2V     15.79mA    11.94mA    18.63mA
-1.199V   18.39mA    11.94mA    18.63mA
-1.186V   18.34mA    11.91mA    18.54mA
-1.176V   16.49mA    11.88mA    18.47mA
-1.147V   18.08mA    11.8mA     18.28mA
-535.9mV  11.85mA    9.345mA    14.31mA
-149.4mV  4.188mA    3.345mA    5.236mA
825.6mV   -21.05mA   -16.46mA   -26.55mA
1.651V    -39.64mA   -29.74mA   -50.74mA
1.95V     -44.99mA   -33.11mA   -58.28mA
2.521V    -52.16mA   -36.75mA   -67.68mA
3V        -54.72mA   -39.78mA   -75.51mA
[POWER Clamp]
|   Voltage   I(typ)   I(min)   I(max)
-1.2V     57.06mA    40.03mA    79.18mA
-1.112V   39.44mA    29.98mA    55.96mA
-1.038V   27.81mA    23.22mA    38.42mA
-1.012V   24.89mA    20.81mA    32.45mA
-946.5mV  17.68mA    15.73mA    21.61mA
-873.2mV  11.92mA    10.65mA    13.96mA
-845.5mV  9.825mA    9.199mA    12.71mA
-786.5mV  7.83mA     6.671mA    10.03mA
-492mV    2.081mA    1.584mA    3.049mA
-321.5mV  1.046mA    798.6uA    551.8uA
-149.4mV  3.227uA    7.432uA    3.467uA
3V        0A         0A         0A
[Ramp]
R_load = 300
|   typ   min   max
dV/dt_r   0.95394/2.43354e-10   0.877488/4.02334e-10   1.02615/1.77767e-10
dV/dt_f   0.970554/2.43816e-10   0.896767/3.11317e-10   1.04001/2.04131e-10
[Falling Waveform]
V_fixture = 1.8V
V_fixture_min = 1.71V
V_fixture_max = 1.89V
R_fixture = 300Ohm
C_fixture = 0F
|   Time   V(typ)   V(min)   V(max)
0s        1.793V     1.703V     1.883V
352.6ps   1.827V     1.715V     1.949V
440.7ps   1.832V     1.724V     1.726V
497.5ps   1.842V     1.725V     1.232V
597.6ps   1.685V     1.728V     649.1mV
781.6ps   759.5mV    1.732V     326.1mV
956.8ps   431mV      1.568V     197.3mV
1.279ns   220.7mV    603.8mV    158.4mV
1.723ns   181mV      272.9mV    152.1mV
5ns       175.5mV    208mV      149.7mV
[Rising Waveform]
V_fixture = 0V
V_fixture_min = 0V
V_fixture_max = 0V
R_fixture = 300Ohm
C_fixture = 0F
|   Time   V(typ)   V(min)   V(max)
0s        68.58uV    169.8uV    47.12uV
356.5ps   -105.3mV   -94.7mV    -42.14mV
409.6ps   -84.75mV   -107.2mV   156.4mV
487.8ps   27.84mV    -106mV     724.1mV
587ps     344mV      -46.04mV   1.271V
811.7ps   1.24V      187.8mV    1.657V
968.9ps   1.488V     481.9mV    1.684V
1.258ns   1.562V     1.135V     1.697V
1.569ns   1.576V     1.388V     1.705V
5ns       1.59V      1.463V     1.71V
[Rising Waveform]
V_fixture = 1.8V
V_fixture_min = 1.71V
V_fixture_max = 1.89V
R_fixture = 300Ohm
C_fixture = 0F
|   Time   V(typ)   V(min)   V(max)
0s        175.5mV    208mV      149.7mV
227.9ps   140.5mV    197.2mV    113.9mV
304.7ps   171.7mV    183mV      236.6mV
397ps     343.4mV    246.6mV    554.2mV
555.9ps   825.4mV    544.1mV    1.506V
650.2ps   1.237V     739.1mV    1.75V
754.1ps   1.531V     940.5mV    1.833V
1.08ns    1.761V     1.497V     1.868V
1.309ns   1.777V     1.648V     1.874V
5ns       1.793V     1.703V     1.883V
[Falling Waveform]
|Gnd
V_fixture = 0V
V_fixture_min = 0V
V_fixture_max = 0V
R_fixture = 300Ohm
C_fixture = 0F
|   Time   V(typ)   V(min)   V(max)
0s        1.59V      1.463V     1.71V
352.6ps   1.621V     1.476V     1.772V
437.5ps   1.623V     1.483V     1.548V
495.7ps   1.633V     1.484V     1.027V
578.6ps   1.481V     1.485V     552.2mV
766ps     595mV      1.489V     203.8mV
961.7ps   256.3mV    1.25V      48.98mV
1.233ns   55.95mV    428.7mV    10.51mV
1.723ns   6.158mV    64.55mV    2.374mV
5ns       67.61uV    167uV      47.18uV
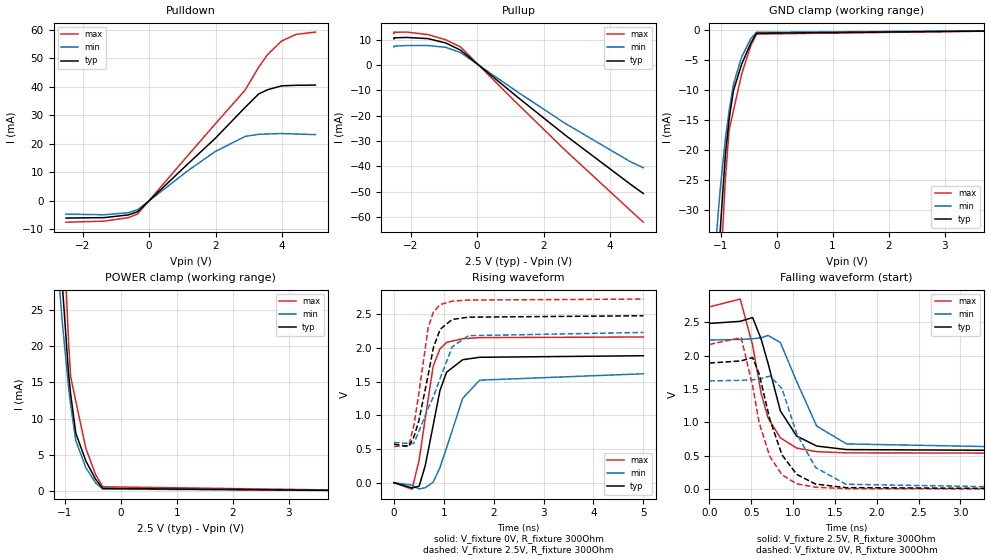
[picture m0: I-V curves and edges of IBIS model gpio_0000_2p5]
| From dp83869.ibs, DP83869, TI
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|   gpio_0000_2p5 Model
[Model]   gpio_0000_2p5
Model_type   I/O
Polarity   Non-Inverting
Enable   Active-Low
Vinl = 0.7
Vinh = 1.7
Vmeas = 1.25
Vref = 0
Cref = 2pF
Rref = 100000
|   typ   min   max
C_comp   1.246pF   1.092pF   1.323pF
| Where Nom  PVT is Nominal Process, 2.5V,  27C
|   Fast PVT is Strong Process,  2.75V, -40C
|   Slow PVT is Weak Process,   2.25V, 125C
[Voltage Range]   2.5   2.25   2.75
|Junction Temperature
[Temperature Range]   27   125   -40
[Pullup Reference]   2.5   2.25   2.75
[Pulldown Reference]   -0   -0   0
[Power Clamp Reference]   2.5   2.25   2.75
[GND Clamp Reference]   0   0   0
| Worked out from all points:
|   slope of the pulldown table from 0 to 0.375 V, typ, clamps not added: 88.9 ohm
|   slope of the pullup table from 0 to 0.375 V, typ, clamps not added: 93.1 ohm
|   GND clamp passes 1 mA (typ) near -0.39 V on its own axis
|   POWER clamp passes 1 mA (typ) near -0.39 V on its own axis
|   falling waveform, V_fixture 2.5V, R_fixture 300Ohm: 20-80 % time 282ps typ, 341ps min, 239ps max; typ from 2.48 V to 0.572 V
|   rising waveform, V_fixture 0V, R_fixture 300Ohm: 20-80 % time 314ps typ, 439ps min, 262ps max; typ from 0 V to 1.89 V
|   rising waveform, V_fixture 2.5V, R_fixture 300Ohm: 20-80 % time 313ps typ, 509ps min, 255ps max; typ from 0.572 V to 2.48 V
|   falling waveform, V_fixture 0V, R_fixture 300Ohm: 20-80 % time 290ps typ, 338ps min, 255ps max; typ from 1.89 V to 0 V
[Pulldown]
|   Voltage   I(typ)   I(min)   I(max)
-2.5V     -6.014mA   -4.648mA   -7.469mA
-1.348V   -5.866mA   -4.856mA   -7.105mA
-624.7mV  -4.916mA   -4.159mA   -5.858mA
-348.8mV  -3.801mA   -3.094mA   -4.599mA
1.151V    12.84mA    10.46mA    15.74mA
1.973V    21.76mA    17.22mA    26.81mA
2.886V    32.79mA    22.61mA    38.85mA
3.292V    37.5mA     23.36mA    46.84mA
3.559V    38.98mA    23.47mA    51.29mA
3.984V    40.35mA    23.62mA    56.07mA
4.418V    40.54mA    23.46mA    58.39mA
5V        40.61mA    23.24mA    59.2mA
[GND Clamp]
|   Voltage   I(typ)   I(min)   I(max)
-2.5V     -325.5mA   -278mA     -374.2mA
-1.151V   -58.23mA   -45.14mA   -72.47mA
-1.062V   -42.41mA   -32.96mA   -53.36mA
-1.027V   -36.66mA   -28.83mA   -45.98mA
-1.002V   -32.86mA   -26.25mA   -40.53mA
-914.3mV  -20.84mA   -18.12mA   -24.89mA
-846.8mV  -14.83mA   -13.46mA   -16.65mA
-770.2mV  -10.08mA   -9.023mA   -13.45mA
-624.7mV  -5.69mA    -4.486mA   -7.367mA
-460.5mV  -2.142mA   -1.389mA   -2.573mA
-358.7mV  -493.6uA   -330.5uA   -623.1uA
5V        0A         0A         0A
[Pullup]
|   Voltage   I(typ)   I(min)   I(max)
-2.5V     10.27mA    7.073mA    12.41mA
-2.499V   10.66mA    7.396mA    12.87mA
-2.497V   10.67mA    7.398mA    12.51mA
-2.496V   10.67mA    7.398mA    12.87mA
-2.106V   10.81mA    7.628mA    12.93mA
-1.477V   10.35mA    7.618mA    11.95mA
-938.2mV  8.625mA    6.905mA    9.883mA
-498mV    5.812mA    4.853mA    7.061mA
1.227V    -12.84mA   -10.79mA   -15.52mA
2.655V    -27.79mA   -23.14mA   -33.76mA
4.602V    -47.04mA   -38.18mA   -57.35mA
5V        -50.79mA   -40.6mA    -62.1mA
[POWER Clamp]
|   Voltage   I(typ)   I(min)   I(max)
-2.5V     383.1mA    300.3mA    465.8mA
-1.265V   71.43mA    49.26mA    97.28mA
-1.162V   48.95mA    35.07mA    69.59mA
-1.083V   35.05mA    27.13mA    48.53mA
-1.045V   28.71mA    23.46mA    40.27mA
-931.5mV  16.22mA    14.27mA    20.59mA
-894.8mV  13.41mA    11.9mA     15.81mA
-802.5mV  7.998mA    6.976mA    12.43mA
-624mV    4.16mA     3.224mA    5.913mA
-448.5mV  1.623mA    1.115mA    2.26mA
-321.9mV  342.6uA    265.3uA    575.4uA
5V        0A         0A         0A
[Ramp]
R_load = 300
|   typ   min   max
dV/dt_r   1.13127/3.11524e-10   0.970762/4.35069e-10   1.29914/2.60862e-10
dV/dt_f   1.1447/2.78312e-10   0.980635/3.37533e-10   1.31397/2.38136e-10
[Falling Waveform]
V_fixture = 2.5V
V_fixture_min = 2.25V
V_fixture_max = 2.75V
R_fixture = 300Ohm
C_fixture = 0F
|   Time   V(typ)   V(min)   V(max)
0s        2.48V      2.232V     2.728V
369.1ps   2.512V     2.241V     2.845V
516.6ps   2.569V     2.251V     2.156V
619.1ps   2.245V     2.266V     1.43V
701.5ps   1.881V     2.3V       1.067V
847.9ps   1.172V     2.196V     769.1mV
1.043ns   795mV      1.612V     614.4mV
1.282ns   645.6mV    944.9mV    561.5mV
1.639ns   592.4mV    677.3mV    543.4mV
5ns       572.3mV    597.6mV    537.7mV
[Rising Waveform]
V_fixture = 0V
V_fixture_min = 0V
V_fixture_max = 0V
R_fixture = 300Ohm
C_fixture = 0F
|   Time   V(typ)   V(min)   V(max)
0s        257.3uV    430.3uV    258.2uV
363.3ps   -79.57mV   -37.62mV   -96.47mV
504.9ps   -53.15mV   -93.25mV   332.6mV
627.6ps   251.9mV    -75.32mV   953.2mV
786.6ps   850.4mV    6.562mV    1.729V
921.7ps   1.367V     221.9mV    1.986V
1.055ns   1.641V     516.2mV    2.084V
1.379ns   1.827V     1.254V     2.139V
1.719ns   1.863V     1.523V     2.155V
5ns       1.886V     1.618V     2.165V
[Rising Waveform]
V_fixture = 2.5V
V_fixture_min = 2.25V
V_fixture_max = 2.75V
R_fixture = 300Ohm
C_fixture = 0F
|   Time   V(typ)   V(min)   V(max)
0s        572.3mV    597.6mV    537.7mV
298.9ps   536mV      582.7mV    550.7mV
398.7ps   677.5mV    582.2mV    845.9mV
500.7ps   921.2mV    762.9mV    1.334V
688.4ps   1.607V     1.11V      2.307V
792.7ps   2.01V      1.278V     2.537V
927.7ps   2.28V      1.553V     2.646V
1.169ns   2.425V     2.019V     2.697V
1.495ns   2.459V     2.184V     2.713V
5ns       2.48V      2.232V     2.728V
[Falling Waveform]
|Gnd
V_fixture = 0V
V_fixture_min = 0V
V_fixture_max = 0V
R_fixture = 300Ohm
C_fixture = 0F
|   Time   V(typ)   V(min)   V(max)
0s        1.887V     1.62V      2.166V
380ps     1.92V      1.629V     2.267V
516.6ps   1.969V     1.638V     1.55V
594.6ps   1.727V     1.646V     995.6mV
724.1ps   1.036V     1.692V     485.1mV
867.8ps   513.3mV    1.505V     214.6mV
1.043ns   222.1mV    829.4mV    81.04mV
1.267ns   77mV       326mV      29.4mV
1.629ns   23.54mV    73.9mV     8.229mV
5ns       252.8uV    422.9uV    256.7uV
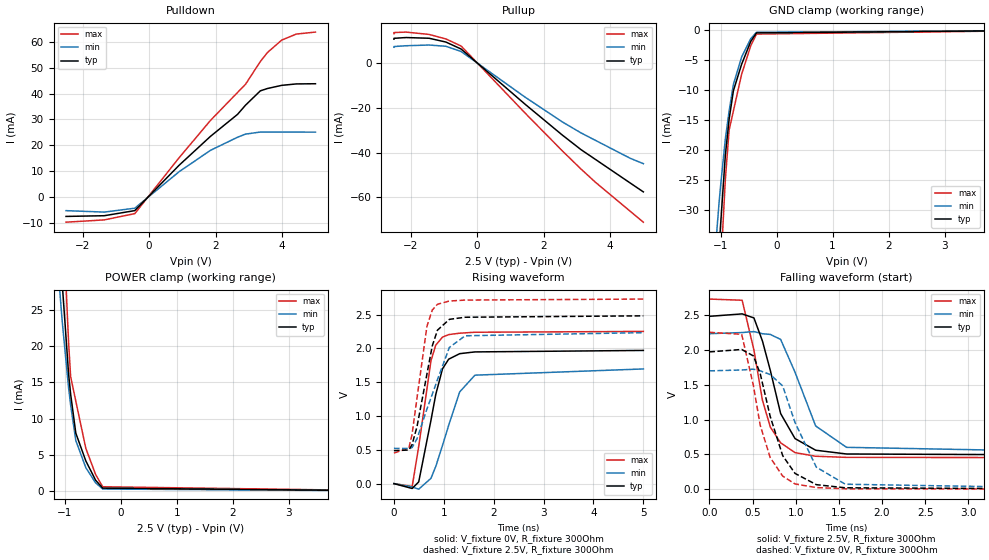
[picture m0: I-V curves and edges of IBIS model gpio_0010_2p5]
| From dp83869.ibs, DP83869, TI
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|   gpio_0010_2p5 Model
[Model]   gpio_0010_2p5
Model_type   I/O
Polarity   Non-Inverting
Enable   Active-Low
Vinl = 0.7
Vinh = 1.7
Vmeas = 1.25
Vref = 0
Cref = 2pF
Rref = 100000
|   typ   min   max
C_comp   1.246pF   1.092pF   1.323pF
| Where Nom  PVT is Nominal Process, 2.5V,  27C
|   Fast PVT is Strong Process,  2.75V, -40C
|   Slow PVT is Weak Process,   2.25V, 125C
[Voltage Range]   2.5   2.25   2.75
|Junction Temperature
[Temperature Range]   27   125   -40
[Pullup Reference]   2.5   2.25   2.75
[Pulldown Reference]   0   0   -0
[Power Clamp Reference]   2.5   2.25   2.75
[GND Clamp Reference]   0   0   0
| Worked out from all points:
|   slope of the pulldown table from 0 to 0.375 V, typ, clamps not added: 72.7 ohm
|   slope of the pullup table from 0 to 0.375 V, typ, clamps not added: 76.9 ohm
|   GND clamp passes 1 mA (typ) near -0.41 V on its own axis
|   POWER clamp passes 1 mA (typ) near -0.41 V on its own axis
|   falling waveform, V_fixture 2.5V, R_fixture 300Ohm: 20-80 % time 271ps typ, 334ps min, 229ps max; typ from 2.48 V to 0.488 V
|   rising waveform, V_fixture 0V, R_fixture 300Ohm: 20-80 % time 311ps typ, 439ps min, 260ps max; typ from 0 V to 1.97 V
|   rising waveform, V_fixture 2.5V, R_fixture 300Ohm: 20-80 % time 308ps typ, 483ps min, 250ps max; typ from 0.488 V to 2.48 V
|   falling waveform, V_fixture 0V, R_fixture 300Ohm: 20-80 % time 281ps typ, 334ps min, 244ps max; typ from 1.97 V to 0 V
[Pulldown]
|   Voltage   I(typ)   I(min)   I(max)
-2.5V     -7.562mA   -5.327mA   -9.796mA
-1.35V    -7.289mA   -5.886mA   -8.905mA
-432mV    -5.315mA   -4.38mA    -6.481mA
901.8mV   12.25mA    9.75mA     15.17mA
1.846V    23.45mA    18.03mA    29.62mA
2.656V    31.92mA    23.07mA    40.39mA
2.897V    35.48mA    24.3mA     43.57mA
3.343V    41.04mA    25.09mA    52.38mA
3.559V    41.95mA    25.08mA    55.9mA
3.987V    43.17mA    25.07mA    60.69mA
4.425V    43.72mA    25.07mA    63.02mA
5V        43.79mA    25.06mA    63.78mA
[GND Clamp]
|   Voltage   I(typ)   I(min)   I(max)
-2.5V     -325.5mA   -278mA     -374.2mA
-1.151V   -58.23mA   -45.14mA   -72.47mA
-1.062V   -42.41mA   -32.96mA   -53.36mA
-1.027V   -36.66mA   -28.83mA   -45.98mA
-1.002V   -32.86mA   -26.26mA   -40.53mA
-914.3mV  -20.84mA   -18.12mA   -24.89mA
-846.8mV  -14.83mA   -13.46mA   -16.65mA
-770.2mV  -10.08mA   -9.023mA   -13.45mA
-624.7mV  -5.69mA    -4.486mA   -7.367mA
-460.5mV  -1.85mA    -1.389mA   -2.574mA
-358.7mV  -429.3uA   -330.5uA   -624.5uA
5V        0A         0A         0A
[Pullup]
|   Voltage   I(typ)   I(min)   I(max)
-2.5V     10.91mA    7.282mA    13.43mA
-2.499V   11.3mA     7.606mA    13.89mA
-2.135V   11.65mA    7.965mA    14.1mA
-1.442V   11.33mA    8.291mA    13.04mA
-935.2mV  9.612mA    7.717mA    11.01mA
-479.3mV  6.482mA    5.368mA    7.838mA
1.44V     -18.26mA   -15.1mA    -22.22mA
2.557V    -32.09mA   -26.19mA   -39.18mA
3.125V    -38.71mA   -31.2mA    -47.43mA
3.55V     -43.01mA   -34.47mA   -53.24mA
4.602V    -53.68mA   -42.58mA   -66.37mA
5V        -57.7mA    -45.02mA   -71.31mA
[POWER Clamp]
|   Voltage   I(typ)   I(min)   I(max)
-2.5V     383.1mA    300.3mA    465.8mA
-1.265V   71.44mA    49.26mA    97.28mA
-1.162V   48.95mA    35.07mA    69.59mA
-1.083V   35.05mA    27.13mA    48.54mA
-1.045V   28.71mA    23.46mA    40.27mA
-931.5mV  16.22mA    14.27mA    20.59mA
-894.8mV  13.41mA    11.9mA     15.81mA
-802.5mV  7.998mA    6.976mA    12.43mA
-624mV    4.16mA     3.225mA    5.913mA
-448.5mV  1.483mA    1.115mA    2.261mA
-321.9mV  387.1uA    265.3uA    577.3uA
5V        0A         0A         0A
[Ramp]
R_load = 300
|   typ   min   max
dV/dt_r   1.18219/3.10021e-10   1.01809/4.38704e-10   1.35101/2.59428e-10
dV/dt_f   1.19668/2.67622e-10   1.02759/3.30058e-10   1.36745/2.28162e-10
[Falling Waveform]
V_fixture = 2.5V
V_fixture_min = 2.25V
V_fixture_max = 2.75V
R_fixture = 300Ohm
C_fixture = 0F
|   Time   V(typ)   V(min)   V(max)
0s        2.483V     2.234V     2.731V
379.7ps   2.518V     2.25V      2.714V
516.1ps   2.46V      2.264V     1.999V
614.7ps   2.129V     2.233V     1.278V
706.2ps   1.705V     2.223V     891.6mV
825.6ps   1.086V     2.151V     665.7mV
992.2ps   726.9mV    1.68V      525.3mV
1.231ns   559.7mV    908.4mV    473.2mV
1.589ns   505.5mV    601.2mV    456.9mV
5ns       488.4mV    521.6mV    451.9mV
[Rising Waveform]
V_fixture = 0V
V_fixture_min = 0V
V_fixture_max = 0V
R_fixture = 300Ohm
C_fixture = 0F
|   Time   V(typ)   V(min)   V(max)
0s        212.1uV    361.6uV    210.8uV
366.3ps   -71.64mV   -49.01mV   -41.9mV
497.3ps   26.04mV    -81.94mV   551.9mV
742.9ps   938.3mV    78.69mV    1.819V
838.8ps   1.319V     253.9mV    2.05V
974ps     1.699V     565.5mV    2.168V
1.097ns   1.841V     861.5mV    2.205V
1.318ns   1.923V     1.357V     2.226V
1.624ns   1.949V     1.605V     2.24V
5ns       1.971V     1.697V     2.252V
[Rising Waveform]
V_fixture = 2.5V
V_fixture_min = 2.25V
V_fixture_max = 2.75V
R_fixture = 300Ohm
C_fixture = 0F
|   Time   V(typ)   V(min)   V(max)
0s        488.4mV    521.6mV    451.9mV
298.9ps   497mV      521.8mV    526mV
362.9ps   575.4mV    533mV      724.5mV
463.4ps   844.8mV    664.7mV    1.27V
661.5ps   1.62V      1.104V     2.326V
768.4ps   2.037V     1.321V     2.568V
873.1ps   2.271V     1.54V      2.654V
1.112ns   2.431V     2.016V     2.702V
1.429ns   2.462V     2.188V     2.716V
5ns       2.483V     2.234V     2.731V
[Falling Waveform]
|Gnd
V_fixture = 0V
V_fixture_min = 0V
V_fixture_max = 0V
R_fixture = 300Ohm
C_fixture = 0F
|   Time   V(typ)   V(min)   V(max)
0s        1.972V     1.7V       2.253V
374.3ps   2.007V     1.712V     2.225V
510.4ps   1.914V     1.724V     1.487V
589.2ps   1.659V     1.7V       916.5mV
704.4ps   1.046V     1.647V     455.1mV
849.5ps   481.4mV    1.483V     187.6mV
992.2ps   226.7mV    956.8mV    75.29mV
1.239ns   64.78mV    315.8mV    23.01mV
1.575ns   19.96mV    71.12mV    6.097mV
5ns       208.4uV    355.9uV    209.7uV
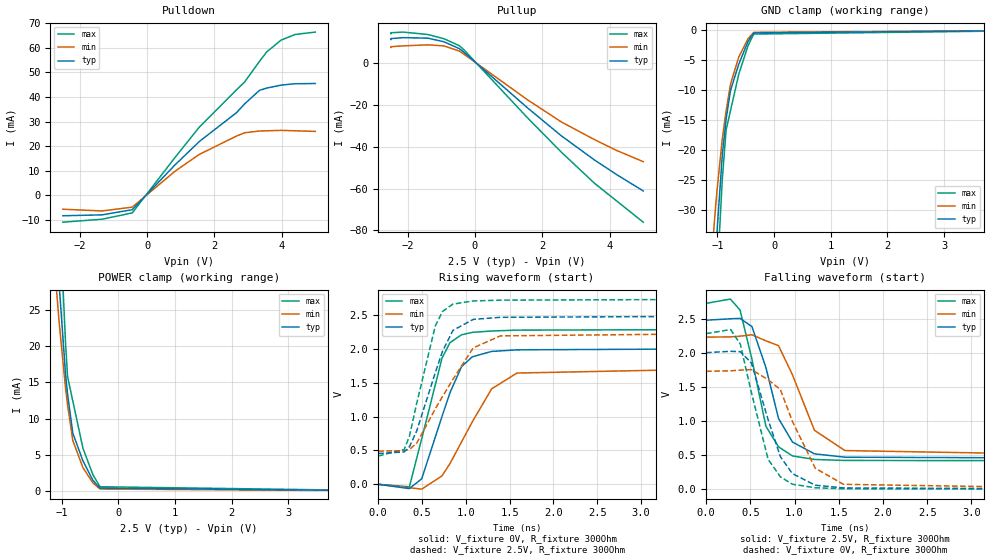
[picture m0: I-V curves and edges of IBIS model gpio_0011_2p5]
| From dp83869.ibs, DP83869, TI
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|   gpio_0011_2p5 Model
[Model]   gpio_0011_2p5
Model_type   I/O
Polarity   Non-Inverting
Enable   Active-Low
Vinl = 0.7
Vinh = 1.7
Vmeas = 1.25
Vref = 0
Cref = 2pF
Rref = 100000
|   typ   min   max
C_comp   1.246pF   1.092pF   1.323pF
| Where Nom  PVT is Nominal Process, 2.5V,  27C
|   Fast PVT is Strong Process,  2.75V, -40C
|   Slow PVT is Weak Process,   2.25V, 125C
[Voltage Range]   2.5   2.25   2.75
|Junction Temperature
[Temperature Range]   27   125   -40
[Pullup Reference]   2.5   2.25   2.75
[Pulldown Reference]   -0   -0   -0
[Power Clamp Reference]   2.5   2.25   2.75
[GND Clamp Reference]   0   0   0
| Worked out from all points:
|   slope of the pulldown table from 0 to 0.375 V, typ, clamps not added: 66.5 ohm
|   slope of the pullup table from 0 to 0.375 V, typ, clamps not added: 70.7 ohm
|   GND clamp passes 1 mA (typ) near -0.41 V on its own axis
|   POWER clamp passes 1 mA (typ) near -0.41 V on its own axis
|   falling waveform, V_fixture 2.5V, R_fixture 300Ohm: 20-80 % time 269ps typ, 333ps min, 232ps max; typ from 2.48 V to 0.454 V
|   rising waveform, V_fixture 0V, R_fixture 300Ohm: 20-80 % time 313ps typ, 444ps min, 262ps max; typ from 0 V to 2 V
|   rising waveform, V_fixture 2.5V, R_fixture 300Ohm: 20-80 % time 307ps typ, 473ps min, 248ps max; typ from 0.454 V to 2.48 V
|   falling waveform, V_fixture 0V, R_fixture 300Ohm: 20-80 % time 286ps typ, 342ps min, 248ps max; typ from 2.01 V to 0 V
[Pulldown]
|   Voltage   I(typ)   I(min)   I(max)
-2.5V     -8.367mA   -5.701mA   -10.98mA
-1.333V   -7.991mA   -6.407mA   -9.762mA
-438.8mV  -5.894mA   -4.842mA   -7.194mA
829.2mV   12.31mA    9.744mA    15.32mA
1.554V    21.86mA    16.62mA    27.71mA
2.657V    33.58mA    24.07mA    42.88mA
2.9V      37.17mA    25.42mA    46.09mA
3.343V    42.7mA     26.14mA    54.51mA
3.556V    43.6mA     26.22mA    58.32mA
3.981V    44.82mA    26.39mA    63.12mA
4.405V    45.38mA    26.22mA    65.44mA
5V        45.46mA    25.98mA    66.4mA
[GND Clamp]
|   Voltage   I(typ)   I(min)   I(max)
-2.5V     -325.5mA   -278mA     -374.2mA
-1.151V   -58.23mA   -45.14mA   -72.47mA
-1.062V   -42.41mA   -32.96mA   -53.36mA
-1.027V   -36.66mA   -28.83mA   -45.98mA
-1.002V   -32.86mA   -26.26mA   -40.53mA
-914.3mV  -20.84mA   -18.12mA   -24.89mA
-846.8mV  -14.83mA   -13.46mA   -16.65mA
-770.2mV  -10.08mA   -9.023mA   -13.45mA
-624.7mV  -5.69mA    -4.486mA   -7.367mA
-460.5mV  -1.85mA    -1.389mA   -2.574mA
-358.7mV  -429.3uA   -330.5uA   -624.5uA
5V        0A         0A         0A
[Pullup]
|   Voltage   I(typ)   I(min)   I(max)
-2.5V     11.16mA    7.357mA    13.88mA
-2.499V   11.55mA    7.681mA    14.34mA
-2.131V   12.01mA    8.093mA    14.66mA
-1.399V   11.76mA    8.566mA    13.5mA
-927mV    10.07mA    8.083mA    11.53mA
-470.3mV  6.818mA    5.639mA    8.218mA
-339.8mV  5.216mA    4.266mA    6.42mA
1.554V    -21.39mA   -17.57mA   -26.12mA
2.562V    -34.78mA   -28.17mA   -42.56mA
3.556V    -46.43mA   -36.7mA    -57.54mA
4.205V    -53.28mA   -41.78mA   -65.87mA
5V        -61.14mA   -47.18mA   -76.06mA
[POWER Clamp]
|   Voltage   I(typ)   I(min)   I(max)
-2.5V     383.1mA    300.3mA    465.8mA
-1.265V   71.44mA    49.26mA    97.29mA
-1.162V   48.95mA    35.07mA    69.59mA
-1.083V   35.06mA    27.13mA    48.54mA
-1.045V   28.71mA    23.46mA    40.27mA
-931.5mV  16.22mA    14.27mA    20.59mA
-894.8mV  13.41mA    11.9mA     15.81mA
-802.5mV  7.998mA    6.976mA    12.43mA
-624mV    4.16mA     3.225mA    5.913mA
-448.5mV  1.483mA    1.115mA    2.261mA
-321.9mV  387.1uA    265.3uA    577.3uA
5V        0A         0A         0A
[Ramp]
R_load = 300
|   typ   min   max
dV/dt_r   1.20279/3.12175e-10   1.03766/4.43053e-10   1.37168/2.6124e-10
dV/dt_f   1.21795/2.66762e-10   1.04769/3.2994e-10   1.38873/2.28522e-10
[Falling Waveform]
V_fixture = 2.5V
V_fixture_min = 2.25V
V_fixture_max = 2.75V
R_fixture = 300Ohm
C_fixture = 0F
|   Time   V(typ)   V(min)   V(max)
0s        2.484V     2.235V     2.732V
274ps     2.505V     2.239V     2.795V
383.6ps   2.511V     2.249V     2.634V
518.4ps   2.39V      2.27V      1.909V
676.2ps   1.789V     2.181V     925.3mV
819ps     1.04V      2.11V      622.9mV
976.2ps   693.4mV    1.682V     488.7mV
1.225ns   519.8mV    866mV      437.1mV
1.57ns    470.2mV    567.9mV    422.3mV
5ns       454.1mV    489mV      417.7mV
[Rising Waveform]
V_fixture = 0V
V_fixture_min = 0V
V_fixture_max = 0V
R_fixture = 300Ohm
C_fixture = 0F
|   Time   V(typ)   V(min)   V(max)
0s        193.5uV    333.2uV    191.4uV
355.8ps   -62.99mV   -49.23mV   -37.16mV
496.4ps   81.63mV    -71.31mV   672.4mV
728.2ps   1.001V     125.4mV    1.86V
819.7ps   1.353V     307.9mV    2.09V
950.8ps   1.735V     624.5mV    2.205V
1.073ns   1.88V      919.7mV    2.241V
1.295ns   1.96V      1.409V     2.261V
1.584ns   1.983V     1.641V     2.274V
5ns       2.005V     1.73V      2.286V
[Rising Waveform]
V_fixture = 2.5V
V_fixture_min = 2.25V
V_fixture_max = 2.75V
R_fixture = 300Ohm
C_fixture = 0F
|   Time   V(typ)   V(min)   V(max)
0s        454.1mV    489.1mV    417.7mV
297ps     478.1mV    496.4mV    513.7mV
355.8ps   552.4mV    513.5mV    707.7mV
439.2ps   786mV      606mV      1.193V
650.4ps   1.642V     1.11V      2.331V
733ps     1.959V     1.293V     2.548V
852.7ps   2.27V      1.548V     2.658V
1.084ns   2.432V     2.011V     2.704V
1.393ns   2.463V     2.189V     2.716V
5ns       2.484V     2.235V     2.732V
[Falling Waveform]
|Gnd
V_fixture = 0V
V_fixture_min = 0V
V_fixture_max = 0V
R_fixture = 300Ohm
C_fixture = 0F
|   Time   V(typ)   V(min)   V(max)
0s        2.007V     1.733V     2.287V
277.1ps   2.027V     1.74V      2.347V
386.7ps   2.022V     1.75V      2.133V
512.6ps   1.855V     1.758V     1.418V
700.6ps   1.025V     1.61V      440.7mV
840.8ps   475.4mV    1.463V     180.3mV
976.2ps   228.4mV    995.4mV    72.79mV
1.234ns   58.51mV    308.7mV    21.12mV
1.553ns   18.5mV     71.41mV    5.465mV
5ns       190.4uV    328.6uV    190.5uV
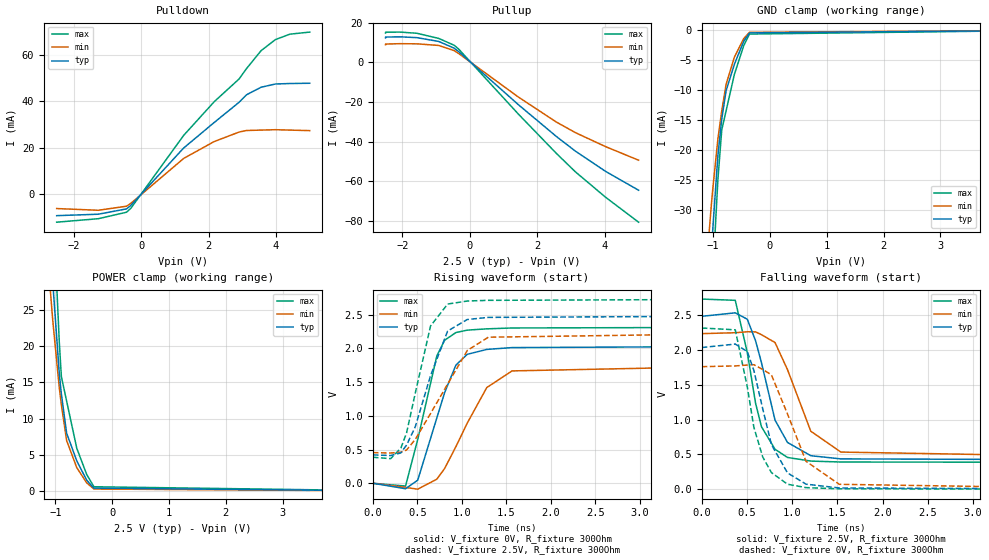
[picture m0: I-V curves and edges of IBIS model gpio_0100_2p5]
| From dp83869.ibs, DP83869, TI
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|   gpio_0100_2p5 Model
[Model]   gpio_0100_2p5
Model_type   I/O
Polarity   Non-Inverting
Enable   Active-Low
Vinl = 0.7
Vinh = 1.7
Vmeas = 1.25
Vref = 0
Cref = 2pF
Rref = 100000
|   typ   min   max
C_comp   1.246pF   1.092pF   1.323pF
| Where Nom  PVT is Nominal Process, 2.5V,  27C
|   Fast PVT is Strong Process,  2.75V, -40C
|   Slow PVT is Weak Process,   2.25V, 125C
[Voltage Range]   2.5   2.25   2.75
|Junction Temperature
[Temperature Range]   27   125   -40
[Pullup Reference]   2.5   2.25   2.75
[Pulldown Reference]   0   0   0
[Power Clamp Reference]   2.5   2.25   2.75
[GND Clamp Reference]   0   0   0
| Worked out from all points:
|   slope of the pulldown table from 0 to 0.375 V, typ, clamps not added: 60.9 ohm
|   slope of the pullup table from 0 to 0.375 V, typ, clamps not added: 65.5 ohm
|   GND clamp passes 1 mA (typ) near -0.41 V on its own axis
|   POWER clamp passes 1 mA (typ) near -0.41 V on its own axis
|   falling waveform, V_fixture 2.5V, R_fixture 300Ohm: 20-80 % time 254ps typ, 322ps min, 213ps max; typ from 2.48 V to 0.421 V
|   rising waveform, V_fixture 0V, R_fixture 300Ohm: 20-80 % time 283ps typ, 410ps min, 235ps max; typ from 0 V to 2.04 V
|   rising waveform, V_fixture 2.5V, R_fixture 300Ohm: 20-80 % time 292ps typ, 469ps min, 234ps max; typ from 0.421 V to 2.48 V
|   falling waveform, V_fixture 0V, R_fixture 300Ohm: 20-80 % time 261ps typ, 320ps min, 222ps max; typ from 2.04 V to 0 V
[Pulldown]
|   Voltage   I(typ)   I(min)   I(max)
-2.5V     -9.321mA   -6.253mA   -12.14mA
-1.267V   -8.695mA   -6.998mA   -10.64mA
-431.3mV  -6.404mA   -5.251mA   -7.841mA
-303.1mV  -4.916mA   -4.018mA   -6.155mA
1.265V    19.91mA    15.4mA     25.35mA
2.166V    30.86mA    22.64mA    39.82mA
2.904V    39.59mA    26.75mA    49.66mA
3.127V    42.85mA    27.43mA    54.17mA
3.558V    46.1mA     27.6mA     61.88mA
3.983V    47.49mA    27.77mA    66.67mA
4.413V    47.7mA     27.6mA     69mA
5V        47.81mA    27.37mA    69.89mA
[GND Clamp]
|   Voltage   I(typ)   I(min)   I(max)
-2.5V     -325.5mA   -278mA     -374.2mA
-1.151V   -58.23mA   -45.14mA   -72.47mA
-1.062V   -42.41mA   -32.96mA   -53.36mA
-1.027V   -36.66mA   -28.83mA   -45.98mA
-1.002V   -32.86mA   -26.26mA   -40.53mA
-914.3mV  -20.85mA   -18.12mA   -24.89mA
-846.8mV  -14.83mA   -13.46mA   -16.65mA
-770.2mV  -10.08mA   -9.023mA   -13.45mA
-624.7mV  -5.69mA    -4.486mA   -7.367mA
-460.6mV  -1.851mA   -1.389mA   -2.574mA
-358.7mV  -429.3uA   -330.5uA   -624.5uA
5V        0A         0A         0A
[Pullup]
|   Voltage   I(typ)   I(min)   I(max)
-2.5V     12.38mA    8.921mA    14.76mA
-2.499V   12.77mA    9.244mA    15.22mA
-2.069V   12.89mA    9.43mA     15.28mA
-1.571V   12.48mA    9.351mA    14.69mA
-924.7mV  10.56mA    8.544mA    12.09mA
-465.8mV  7.176mA    5.938mA    8.639mA
-330.8mV  5.416mA    4.438mA    6.674mA
1.439V    -21.39mA   -17.53mA   -26.15mA
2.561V    -37.39mA   -30.12mA   -45.91mA
3.125V    -44.79mA   -35.46mA   -55.23mA
4.025V    -55.07mA   -42.56mA   -68.14mA
5V        -64.55mA   -49.39mA   -80.68mA
[POWER Clamp]
|   Voltage   I(typ)   I(min)   I(max)
-2.5V     383.1mA    300.3mA    465.8mA
-1.265V   71.44mA    49.26mA    97.29mA
-1.162V   48.95mA    35.07mA    69.59mA
-1.083V   35.06mA    27.13mA    48.54mA
-1.045V   28.71mA    23.46mA    40.27mA
-931.5mV  16.22mA    14.27mA    20.59mA
-894.8mV  13.41mA    11.9mA     15.81mA
-802.5mV  7.998mA    6.976mA    12.43mA
-624.1mV  4.16mA     3.225mA    5.913mA
-448.6mV  1.483mA    1.115mA    2.261mA
-321.9mV  387.1uA    265.3uA    577.3uA
5V        0A         0A         0A
[Ramp]
R_load = 300
|   typ   min   max
dV/dt_r   1.22076/2.82576e-10   1.05496/4.09602e-10   1.38951/2.345e-10
dV/dt_f   1.2386/2.51939e-10   1.06876/3.19507e-10   1.40855/2.11271e-10
[Falling Waveform]
V_fixture = 2.5V
V_fixture_min = 2.25V
V_fixture_max = 2.75V
R_fixture = 300Ohm
C_fixture = 0F
|   Time   V(typ)   V(min)   V(max)
0s        2.485V     2.236V     2.733V
371.3ps   2.535V     2.249V     2.715V
504.4ps   2.443V     2.263V     1.963V
596.1ps   2.132V     2.261V     1.233V
660.7ps   1.82V      2.221V     898.8mV
810.8ps   993.2mV    2.108V     574.3mV
948.6ps   672mV      1.719V     456.1mV
1.206ns   481.3mV    833.6mV    403.9mV
1.539ns   435.5mV    533.4mV    390.5mV
5ns       420.6mV    454.7mV    385.8mV
[Rising Waveform]
V_fixture = 0V
V_fixture_min = 0V
V_fixture_max = 0V
R_fixture = 300Ohm
C_fixture = 0F
|   Time   V(typ)   V(min)   V(max)
0s        179.6uV    308.2uV    177.9uV
367.1ps   -81.32mV   -61.83mV   -41.49mV
504.4ps   46mV       -87.68mV   651.3mV
718.5ps   968.3mV    60.22mV    1.889V
806.7ps   1.346V     219.7mV    2.122V
932.9ps   1.753V     542.7mV    2.236V
1.06ns    1.913V     891.1mV    2.272V
1.28ns    1.986V     1.42V      2.291V
1.564ns   2.013V     1.667V     2.304V
5ns       2.035V     1.759V     2.316V
[Rising Waveform]
V_fixture = 2.5V
V_fixture_min = 2.25V
V_fixture_max = 2.75V
R_fixture = 300Ohm
C_fixture = 0F
|   Time   V(typ)   V(min)   V(max)
0s        420.6mV    454.7mV    385.8mV
199.6ps   411.4mV    448.9mV    364.8mV
314.2ps   449.6mV    459.8mV    520.2mV
378.7ps   566.8mV    493.2mV    746.3mV
475.2ps   833.2mV    648.3mV    1.329V
648.2ps   1.596V     1.035V     2.334V
840.5ps   2.259V     1.472V     2.659V
1.061ns   2.43V      1.97V      2.704V
1.297ns   2.461V     2.167V     2.714V
5ns       2.485V     2.236V     2.733V
[Falling Waveform]
|Gnd
V_fixture = 0V
V_fixture_min = 0V
V_fixture_max = 0V
R_fixture = 300Ohm
C_fixture = 0F
|   Time   V(typ)   V(min)   V(max)
0s        2.036V     1.761V     2.317V
371.3ps   2.086V     1.772V     2.291V
504.4ps   1.978V     1.784V     1.469V
577.6ps   1.703V     1.789V     886.3mV
674.4ps   1.158V     1.721V     464.4mV
770.8ps   641.8mV    1.644V     239mV
948.6ps   234.3mV    1.081V     71.16mV
1.154ns   71.98mV    400.1mV    22.46mV
1.521ns   17.37mV    69.95mV    5.078mV
5ns       176.5uV    303uV      176.9uV
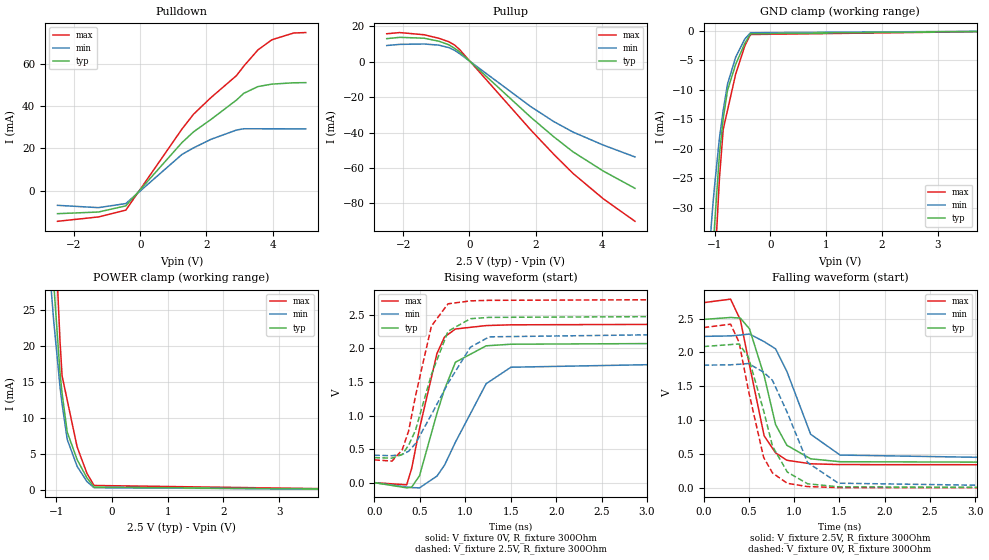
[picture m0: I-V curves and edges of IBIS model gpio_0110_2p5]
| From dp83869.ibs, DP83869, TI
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|   gpio_0110_2p5 Model
[Model]   gpio_0110_2p5
Model_type   I/O
Polarity   Non-Inverting
Enable   Active-Low
Vinl = 0.7
Vinh = 1.7
Vmeas = 1.25
Vref = 0
Cref = 2pF
Rref = 100000
|   typ   min   max
C_comp   1.246pF   1.092pF   1.323pF
| Where Nom  PVT is Nominal Process, 2.5V,  27C
|   Fast PVT is Strong Process,  2.75V, -40C
|   Slow PVT is Weak Process,   2.25V, 125C
[Voltage Range]   2.5   2.25   2.75
|Junction Temperature
[Temperature Range]   27   125   -40
[Pullup Reference]   2.5   2.25   2.75
[Pulldown Reference]   0   0   -0
[Power Clamp Reference]   2.5   2.25   2.75
[GND Clamp Reference]   0   0   0
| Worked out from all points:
|   slope of the pulldown table from 0 to 0.375 V, typ, clamps not added: 52.6 ohm
|   slope of the pullup table from 0 to 0.375 V, typ, clamps not added: 57 ohm
|   GND clamp passes 1 mA (typ) near -0.39 V on its own axis
|   POWER clamp passes 1 mA (typ) near -0.39 V on its own axis
|   falling waveform, V_fixture 2.5V, R_fixture 300Ohm: 20-80 % time 251ps typ, 322ps min, 210ps max; typ from 2.49 V to 0.373 V
|   rising waveform, V_fixture 0V, R_fixture 300Ohm: 20-80 % time 279ps typ, 406ps min, 232ps max; typ from 0 V to 2.08 V
|   rising waveform, V_fixture 2.5V, R_fixture 300Ohm: 20-80 % time 284ps typ, 445ps min, 226ps max; typ from 0.373 V to 2.49 V
|   falling waveform, V_fixture 0V, R_fixture 300Ohm: 20-80 % time 260ps typ, 329ps min, 221ps max; typ from 2.09 V to 0 V
[Pulldown]
|   Voltage   I(typ)   I(min)   I(max)
-2.5V     -10.87mA   -6.932mA   -14.47mA
-1.263V   -10.09mA   -8.023mA   -12.41mA
-435.4mV  -7.184mA   -6.091mA   -9.182mA
1.261V    22.7mA     17.1mA     29.09mA
1.614V    27.8mA     20.22mA    36.15mA
2.141V    33.66mA    24.26mA    44mA
2.908V    42.77mA    28.61mA    54.31mA
3.127V    45.94mA    29.22mA    58.76mA
3.556V    49.13mA    29.21mA    66.45mA
3.979V    50.3mA     29.2mA     71.24mA
4.636V    50.92mA    29.19mA    74.43mA
5V        50.99mA    29.19mA    74.63mA
[GND Clamp]
|   Voltage   I(typ)   I(min)   I(max)
-2.5V     -325.5mA   -278mA     -374.2mA
-1.151V   -58.23mA   -45.14mA   -72.46mA
-1.062V   -42.41mA   -32.96mA   -53.35mA
-1.027V   -36.66mA   -28.83mA   -45.96mA
-1.003V   -32.98mA   -26.33mA   -40.68mA
-915.3mV  -20.96mA   -18.2mA    -25.04mA
-847.2mV  -14.86mA   -13.48mA   -16.68mA
-770.2mV  -10.08mA   -9.023mA   -13.46mA
-624.7mV  -5.69mA    -4.486mA   -7.363mA
-460.9mV  -2.149mA   -1.394mA   -2.584mA
-358.7mV  -493.6uA   -330.5uA   -624.1uA
5V        0A         0A         0A
[Pullup]
|   Voltage   I(typ)   I(min)   I(max)
-2.5V     13.02mA    9.13mA     15.78mA
-2.106V   13.75mA    9.784mA    16.45mA
-1.371V   13.27mA    9.996mA    15.21mA
-922.5mV  11.55mA    9.355mA    13.22mA
-624.7mV  9.557mA    7.958mA    11.25mA
-451.2mV  7.568mA    6.431mA    9.398mA
-306.4mV  5.672mA    4.645mA    7.012mA
1.846V    -31.27mA   -25.3mA    -38.44mA
2.541V    -42.32mA   -33.76mA   -52.2mA
3.124V    -50.87mA   -39.71mA   -63.05mA
4.044V    -61.79mA   -47.11mA   -77.46mA
5V        -71.51mA   -53.8mA    -90.15mA
[POWER Clamp]
|   Voltage   I(typ)   I(min)   I(max)
-2.5V     383.1mA    300.3mA    465.8mA
-1.265V   71.44mA    49.26mA    97.29mA
-1.162V   48.95mA    35.07mA    69.59mA
-1.083V   35.06mA    27.14mA    48.55mA
-1.045V   28.71mA    23.46mA    40.28mA
-931.5mV  16.22mA    14.27mA    20.57mA
-895mV    13.42mA    11.91mA    15.83mA
-802.5mV  7.998mA    6.976mA    12.44mA
-624.4mV  4.167mA    3.23mA     5.923mA
-448.9mV  1.629mA    1.119mA    2.268mA
-321.9mV  342.6uA    265.3uA    574.8uA
5V        0A         0A         0A
[Ramp]
R_load = 300
|   typ   min   max
dV/dt_r   1.25113/2.7872e-10   1.08464/4.05404e-10   1.41937/2.31539e-10
dV/dt_f   1.26818/2.48973e-10   1.09749/3.19424e-10   1.43762/2.09452e-10
[Falling Waveform]
V_fixture = 2.5V
V_fixture_min = 2.25V
V_fixture_max = 2.75V
R_fixture = 300Ohm
C_fixture = 0F
|   Time   V(typ)   V(min)   V(max)
0s        2.487V     2.237V     2.735V
298.2ps   2.516V     2.244V     2.787V
406.3ps   2.507V     2.256V     2.481V
507.3ps   2.348V     2.272V     1.812V
669.2ps   1.656V     2.159V     768.4mV
795.6ps   934.3mV    2.053V     516.9mV
919.7ps   629.1mV    1.721V     407.8mV
1.183ns   428.9mV    791.3mV    355.6mV
1.508ns   386.1mV    484.4mV    343.7mV
5ns       372.9mV    408.2mV    339.3mV
[Rising Waveform]
V_fixture = 0V
V_fixture_min = 0V
V_fixture_max = 0V
R_fixture = 300Ohm
C_fixture = 0F
|   Time   V(typ)   V(min)   V(max)
0s        156.1uV    270.9uV    153.3uV
355.8ps   -77.74mV   -66.06mV   -32.69mV
411ps     -66.47mV   -74.31mV   212mV
497.4ps   102.8mV    -77.44mV   807.6mV
689.5ps   1.035V     97.88mV    1.926V
772.4ps   1.392V     260.5mV    2.171V
892.6ps   1.795V     603.9mV    2.29V
1.23ns    2.039V     1.474V     2.341V
1.502ns   2.063V     1.72V      2.352V
5ns       2.085V     1.808V     2.366V
[Rising Waveform]
V_fixture = 2.5V
V_fixture_min = 2.25V
V_fixture_max = 2.75V
R_fixture = 300Ohm
C_fixture = 0F
|   Time   V(typ)   V(min)   V(max)
0s        372.9mV    408.2mV    339.3mV
194.4ps   364.8mV    402mV      321.4mV
306.1ps   418.4mV    419.3mV    487mV
377.5ps   557.6mV    468.1mV    769.6mV
452.6ps   779mV      582.3mV    1.289V
628.1ps   1.612V     1.014V     2.333V
810.7ps   2.256V     1.48V      2.665V
1.057ns   2.443V     2.019V     2.709V
1.264ns   2.463V     2.173V     2.717V
5ns       2.486V     2.237V     2.735V
[Falling Waveform]
|Gnd
V_fixture = 0V
V_fixture_min = 0V
V_fixture_max = 0V
R_fixture = 300Ohm
C_fixture = 0F
|   Time   V(typ)   V(min)   V(max)
0s        2.087V     1.812V     2.367V
298.2ps   2.116V     1.817V     2.417V
391.5ps   2.125V     1.825V     2.153V
495.1ps   1.933V     1.836V     1.441V
663.4ps   1.14V      1.709V     449.3mV
761.3ps   615.1mV    1.587V     220.3mV
925.3ps   233mV      1.11V      66.77mV
1.149ns   60.71mV    373.7mV    19.1mV
1.489ns   15.55mV    68.97mV    4.469mV
5ns       153.2uV    266.8uV    152.4uV
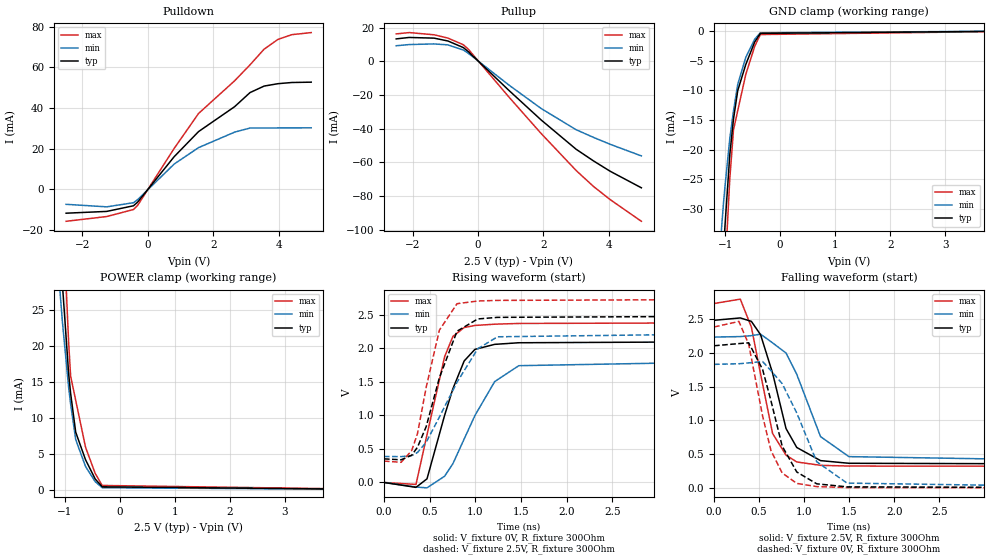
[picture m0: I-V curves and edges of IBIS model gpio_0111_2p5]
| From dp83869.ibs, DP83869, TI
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|   gpio_0111_2p5 Model
[Model]   gpio_0111_2p5
Model_type   I/O
Polarity   Non-Inverting
Enable   Active-Low
Vinl = 0.7
Vinh = 1.7
Vmeas = 1.25
Vref = 0
Cref = 2pF
Rref = 100000
|   typ   min   max
C_comp   1.246pF   1.092pF   1.323pF
| Where Nom  PVT is Nominal Process, 2.5V,  27C
|   Fast PVT is Strong Process,  2.75V, -40C
|   Slow PVT is Weak Process,   2.25V, 125C
[Voltage Range]   2.5   2.25   2.75
|Junction Temperature
[Temperature Range]   27   125   -40
[Pullup Reference]   2.5   2.25   2.75
[Pulldown Reference]   0   -0   0
[Power Clamp Reference]   2.5   2.25   2.75
[GND Clamp Reference]   0   0   0
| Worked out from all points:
|   slope of the pulldown table from 0 to 0.375 V, typ, clamps not added: 49.3 ohm
|   slope of the pullup table from 0 to 0.375 V, typ, clamps not added: 53.5 ohm
|   GND clamp passes 1 mA (typ) near -0.41 V on its own axis
|   POWER clamp passes 1 mA (typ) near -0.41 V on its own axis
|   falling waveform, V_fixture 2.5V, R_fixture 300Ohm: 20-80 % time 252ps typ, 326ps min, 214ps max; typ from 2.49 V to 0.352 V
|   rising waveform, V_fixture 0V, R_fixture 300Ohm: 20-80 % time 279ps typ, 405ps min, 233ps max; typ from 0 V to 2.11 V
|   rising waveform, V_fixture 2.5V, R_fixture 300Ohm: 20-80 % time 283ps typ, 434ps min, 224ps max; typ from 0.352 V to 2.49 V
|   falling waveform, V_fixture 0V, R_fixture 300Ohm: 20-80 % time 268ps typ, 351ps min, 227ps max; typ from 2.11 V to 0 V
[Pulldown]
|   Voltage   I(typ)   I(min)   I(max)
-2.5V     -11.67mA   -7.306mA   -15.65mA
-1.256V   -10.79mA   -8.549mA   -13.31mA
-436.6mV  -8.014mA   -6.515mA   -9.858mA
-309.9mV  -6.214mA   -5.011mA   -7.805mA
806mV     16.09mA    12.47mA    20.15mA
1.554V    28.45mA    20.56mA    37.36mA
2.656V    40.67mA    28.17mA    53.39mA
3.127V    47.6mA     30.18mA    61.23mA
3.558V    50.79mA    30.2mA     68.93mA
3.981V    51.97mA    30.23mA    73.72mA
4.401V    52.55mA    30.25mA    76.05mA
5V        52.72mA    30.28mA    77.09mA
[GND Clamp]
|   Voltage   I(typ)   I(min)   I(max)
-2.5V     -325.5mA   -278mA     -374.2mA
-1.151V   -58.23mA   -45.14mA   -72.47mA
-1.062V   -42.41mA   -32.96mA   -53.36mA
-1.027V   -36.66mA   -28.83mA   -45.98mA
-1.002V   -32.87mA   -26.26mA   -40.54mA
-914.3mV  -20.85mA   -18.13mA   -24.9mA
-846.8mV  -14.83mA   -13.46mA   -16.65mA
-770.2mV  -10.08mA   -9.023mA   -13.45mA
-624.7mV  -5.69mA    -4.486mA   -7.366mA
-460.6mV  -1.851mA   -1.389mA   -2.575mA
-358.7mV  -427.2uA   -330.5uA   -624.4uA
5V        0A         0A         0A
[Pullup]
|   Voltage   I(typ)   I(min)   I(max)
-2.5V     13.27mA    9.205mA    16.23mA
-2.107V   14.12mA    9.911mA    17.02mA
-1.342V   13.72mA    10.29mA    15.71mA
-917.2mV  12.02mA    9.726mA    13.75mA
-445.6mV  8.113mA    6.685mA    9.789mA
-296.4mV  5.778mA    4.753mA    7.188mA
949.2mV   -17.29mA   -14.11mA   -21.22mA
1.929V    -34.71mA   -27.93mA   -42.72mA
3.003V    -52.14mA   -40.57mA   -64.72mA
3.534V    -59.05mA   -45.12mA   -74.19mA
4.044V    -65.18mA   -49.2mA    -81.99mA
5V        -75.01mA   -56.11mA   -94.87mA
[POWER Clamp]
|   Voltage   I(typ)   I(min)   I(max)
-2.5V     383.1mA    300.3mA    465.8mA
-1.265V   71.45mA    49.26mA    97.29mA
-1.162V   48.95mA    35.07mA    69.59mA
-1.083V   35.06mA    27.14mA    48.55mA
-1.045V   28.71mA    23.46mA    40.27mA
-931.5mV  16.22mA    14.27mA    20.59mA
-894.8mV  13.41mA    11.9mA     15.81mA
-802.5mV  7.998mA    6.976mA    12.44mA
-624.1mV  4.161mA    3.225mA    5.914mA
-448.6mV  1.483mA    1.115mA    2.261mA
-321.9mV  388.5uA    265.3uA    577.3uA
5V        0A         0A         0A
[Ramp]
R_load = 300
|   typ   min   max
dV/dt_r   1.26399/2.79214e-10   1.09736/4.04728e-10   1.43191/2.31999e-10
dV/dt_f   1.2809/2.52235e-10   1.11019/3.25477e-10   1.44992/2.13565e-10
[Falling Waveform]
V_fixture = 2.5V
V_fixture_min = 2.25V
V_fixture_max = 2.75V
R_fixture = 300Ohm
C_fixture = 0F
|   Time   V(typ)   V(min)   V(max)
0s        2.487V     2.238V     2.736V
290.7ps   2.522V     2.245V     2.801V
413.7ps   2.471V     2.259V     2.387V
515.9ps   2.273V     2.281V     1.692V
649.1ps   1.704V     2.152V     807.7mV
798.3ps   880.1mV    2.001V     485.4mV
917.5ps   599.3mV    1.685V     384.6mV
1.181ns   404.6mV    761.1mV    334.5mV
1.496ns   364.8mV    463.7mV    323.7mV
5ns       352.4mV    387.6mV    319.6mV
[Rising Waveform]
V_fixture = 0V
V_fixture_min = 0V
V_fixture_max = 0V
R_fixture = 300Ohm
C_fixture = 0F
|   Time   V(typ)   V(min)   V(max)
0s        145.1uV    254.3uV    142.1uV
350.4ps   -72.86mV   -67.67mV   -29.44mV
471ps     54.44mV    -80.33mV   712.7mV
663.4ps   1.001V     93.46mV    1.875V
753.9ps   1.398V     279.5mV    2.179V
877.9ps   1.814V     650.2mV    2.312V
995ps     1.986V     998.8mV    2.343V
1.211ns   2.061V     1.505V     2.362V
1.475ns   2.085V     1.743V     2.373V
5ns       2.107V     1.829V     2.387V
[Rising Waveform]
V_fixture = 2.5V
V_fixture_min = 2.25V
V_fixture_max = 2.75V
R_fixture = 300Ohm
C_fixture = 0F
|   Time   V(typ)   V(min)   V(max)
0s        352.4mV    387.6mV    319.6mV
187.9ps   338.5mV    385.7mV    300.8mV
303.4ps   406.5mV    401.7mV    476mV
367.4ps   527.1mV    448mV      732.2mV
462.7ps   836mV      601.7mV    1.425V
606.1ps   1.562V     976.1mV    2.272V
799.4ps   2.257V     1.496V     2.668V
1.026ns   2.44V      1.995V     2.708V
1.242ns   2.464V     2.174V     2.717V
5ns       2.487V     2.238V     2.736V
[Falling Waveform]
|Gnd
V_fixture = 0V
V_fixture_min = 0V
V_fixture_max = 0V
R_fixture = 300Ohm
C_fixture = 0F
|   Time   V(typ)   V(min)   V(max)
0s        2.109V     1.833V     2.388V
275.1ps   2.141V     1.842V     2.47V
384.3ps   2.153V     1.855V     2.13V
538.5ps   1.757V     1.875V     1.066V
631.2ps   1.292V     1.739V     553.3mV
755.7ps   619.7mV    1.546V     221.2mV
917.5ps   235.7mV    1.111V     66.27mV
1.139ns   59.92mV    388.1mV    18.88mV
1.475ns   15.09mV    70.64mV    4.479mV
5ns       142.9uV    251.1uV    141.4uV
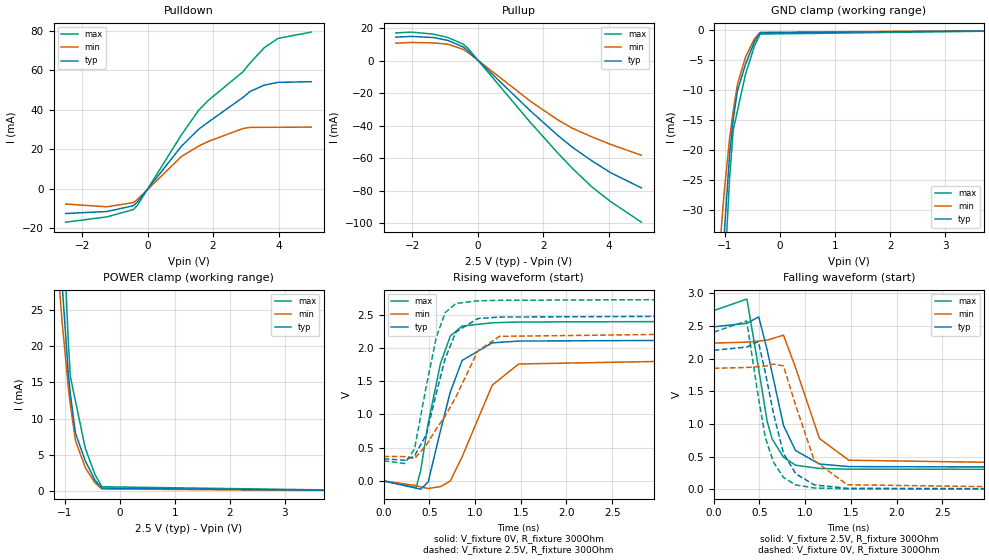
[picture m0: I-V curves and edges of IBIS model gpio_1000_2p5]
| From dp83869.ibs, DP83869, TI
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|   gpio_1000_2p5 Model
[Model]   gpio_1000_2p5
Model_type   I/O
Polarity   Non-Inverting
Enable   Active-Low
Vinl = 0.7
Vinh = 1.7
Vmeas = 1.25
Vref = 0
Cref = 2pF
Rref = 100000
|   typ   min   max
C_comp   1.246pF   1.092pF   1.323pF
| Where Nom  PVT is Nominal Process, 2.5V,  27C
|   Fast PVT is Strong Process,  2.75V, -40C
|   Slow PVT is Weak Process,   2.25V, 125C
[Voltage Range]   2.5   2.25   2.75
|Junction Temperature
[Temperature Range]   27   125   -40
[Pullup Reference]   2.5   2.25   2.75
[Pulldown Reference]   -0   0   0
[Power Clamp Reference]   2.5   2.25   2.75
[GND Clamp Reference]   0   0   0
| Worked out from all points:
|   slope of the pulldown table from 0 to 0.375 V, typ, clamps not added: 46.5 ohm
|   slope of the pullup table from 0 to 0.375 V, typ, clamps not added: 50.6 ohm
|   GND clamp passes 1 mA (typ) near -0.41 V on its own axis
|   POWER clamp passes 1 mA (typ) near -0.41 V on its own axis
|   falling waveform, V_fixture 2.5V, R_fixture 300Ohm: 20-80 % time 220ps typ, 277ps min, 187ps max; typ from 2.49 V to 0.334 V
|   rising waveform, V_fixture 0V, R_fixture 300Ohm: 20-80 % time 252ps typ, 346ps min, 213ps max; typ from 0 V to 2.13 V
|   rising waveform, V_fixture 2.5V, R_fixture 300Ohm: 20-80 % time 247ps typ, 432ps min, 201ps max; typ from 0.334 V to 2.49 V
|   falling waveform, V_fixture 0V, R_fixture 300Ohm: 20-80 % time 228ps typ, 280ps min, 198ps max; typ from 2.13 V to 0 V
[Pulldown]
|   Voltage   I(typ)   I(min)   I(max)
-2.5V     -12.47mA   -7.669mA   -16.87mA
-1.246V   -11.47mA   -9.085mA   -14.18mA
-437.3mV  -8.545mA   -6.947mA   -10.52mA
-310.6mV  -6.619mA   -5.338mA   -8.328mA
1.036V    21.6mA     16.39mA    27.39mA
1.556V    30.1mA     21.6mA     39.66mA
1.844V    33.64mA    23.91mA    44.6mA
2.912V    46.23mA    30.51mA    59.18mA
3.127V    49.19mA    31.1mA     63.58mA
3.559V    52.45mA    31.13mA    71.31mA
3.985V    53.88mA    31.15mA    76.12mA
5V        54.22mA    31.22mA    79.3mA
[GND Clamp]
|   Voltage   I(typ)   I(min)   I(max)
-2.5V     -325.5mA   -278mA     -374.2mA
-1.151V   -58.23mA   -45.14mA   -72.47mA
-1.062V   -42.41mA   -32.96mA   -53.36mA
-1.027V   -36.66mA   -28.83mA   -45.98mA
-1.002V   -32.87mA   -26.26mA   -40.54mA
-914.3mV  -20.85mA   -18.13mA   -24.9mA
-846.8mV  -14.83mA   -13.46mA   -16.65mA
-770.2mV  -10.08mA   -9.023mA   -13.45mA
-624.7mV  -5.69mA    -4.486mA   -7.366mA
-460.6mV  -1.851mA   -1.39mA    -2.575mA
-358.7mV  -427.2uA   -330.5uA   -624.4uA
5V        0A         0A         0A
[Pullup]
|   Voltage   I(typ)   I(min)   I(max)
-2.5V     14.49mA    10.77mA    17.1mA
-2.04V    14.97mA    11.22mA    17.62mA
-1.351V   14.27mA    10.98mA    16.35mA
-913.5mV  12.49mA    10.18mA    14.3mA
-441.8mV  8.453mA    6.966mA    10.2mA
-290.4mV  5.951mA    4.914mA    7.429mA
1.612V    -30.89mA   -24.95mA   -38.04mA
2.423V    -45.52mA   -36.09mA   -56.28mA
2.886V    -53.15mA   -41.48mA   -66.1mA
3.476V    -61.45mA   -46.72mA   -77.4mA
4.05V     -68.74mA   -51.4mA    -86.52mA
5V        -78.23mA   -58.15mA   -99.34mA
[POWER Clamp]
|   Voltage   I(typ)   I(min)   I(max)
-2.5V     383.1mA    300.3mA    465.8mA
-1.265V   71.45mA    49.27mA    97.3mA
-1.162V   48.95mA    35.07mA    69.59mA
-1.083V   35.06mA    27.14mA    48.55mA
-1.045V   28.71mA    23.46mA    40.27mA
-931.5mV  16.22mA    14.27mA    20.59mA
-894.8mV  13.41mA    11.9mA     15.81mA
-802.5mV  7.998mA    6.976mA    12.44mA
-624.1mV  4.161mA    3.225mA    5.914mA
-448.6mV  1.483mA    1.116mA    2.262mA
-321.9mV  388.5uA    265.3uA    577.3uA
5V        0A         0A         0A
[Ramp]
R_load = 300
|   typ   min   max
dV/dt_r   1.27549/2.50617e-10   1.10908/3.44245e-10   1.44296/2.1063e-10
dV/dt_f   1.2922/2.19789e-10   1.12189/2.78317e-10   1.46066/1.86733e-10
[Falling Waveform]
V_fixture = 2.5V
V_fixture_min = 2.25V
V_fixture_max = 2.75V
R_fixture = 300Ohm
C_fixture = 0F
|   Time   V(typ)   V(min)   V(max)
0s        2.488V     2.238V     2.737V
363.2ps   2.542V     2.253V     2.913V
492.2ps   2.641V     2.269V     1.833V
584.2ps   2.133V     2.284V     1.038V
638.4ps   1.781V     2.306V     769.2mV
762.9ps   976.1mV    2.36V      489.3mV
893.3ps   593.7mV    1.868V     367.8mV
1.156ns   385.6mV    777.1mV    317.3mV
1.477ns   345.9mV    443.7mV    306.7mV
5ns       334.2mV    368.7mV    302.4mV
[Rising Waveform]
V_fixture = 0V
V_fixture_min = 0V
V_fixture_max = 0V
R_fixture = 300Ohm
C_fixture = 0F
|   Time   V(typ)   V(min)   V(max)
0s        137.2uV    240.8uV    133.8uV
356ps     -109mV     -68.4mV    -98.47mV
405ps     -123.6mV   -90.56mV   154.2mV
487.1ps   -16.88mV   -113.4mV   867.9mV
622.3ps   759.8mV    -85.22mV   1.771V
729.5ps   1.34V      -394uV     2.18V
858.9ps   1.813V     364.9mV    2.331V
1.188ns   2.078V     1.441V     2.38V
1.477ns   2.105V     1.76V      2.392V
5ns       2.126V     1.849V     2.405V
[Rising Waveform]
V_fixture = 2.5V
V_fixture_min = 2.25V
V_fixture_max = 2.75V
R_fixture = 300Ohm
C_fixture = 0F
|   Time   V(typ)   V(min)   V(max)
0s        334.2mV    368.7mV    302.4mV
229ps     311.1mV    366.5mV    263.4mV
338.4ps   376.2mV    335.3mV    482.7mV
466ps     697.4mV    538.8mV    1.425V
575.4ps   1.317V     781.2mV    2.158V
673.3ps   1.841V     977.5mV    2.533V
790.9ps   2.243V     1.265V     2.671V
1.031ns   2.444V     1.958V     2.71V
1.267ns   2.466V     2.176V     2.719V
5ns       2.488V     2.238V     2.737V
[Falling Waveform]
|Gnd
V_fixture = 0V
V_fixture_min = 0V
V_fixture_max = 0V
R_fixture = 300Ohm
C_fixture = 0F
|   Time   V(typ)   V(min)   V(max)
0s        2.128V     1.852V     2.406V
360.3ps   2.178V     1.865V     2.578V
487.1ps   2.261V     1.878V     1.417V
565.2ps   1.78V      1.886V     783.4mV
653.3ps   1.159V     1.916V     414.6mV
762.9ps   547.1mV    1.889V     179mV
896.8ps   236.1mV    1.28V      64.37mV
1.1ns     65.03mV    439.3mV    18.93mV
1.46ns    14.17mV    67.82mV    4.29mV
5ns       135.1uV    237.5uV    133.2uV
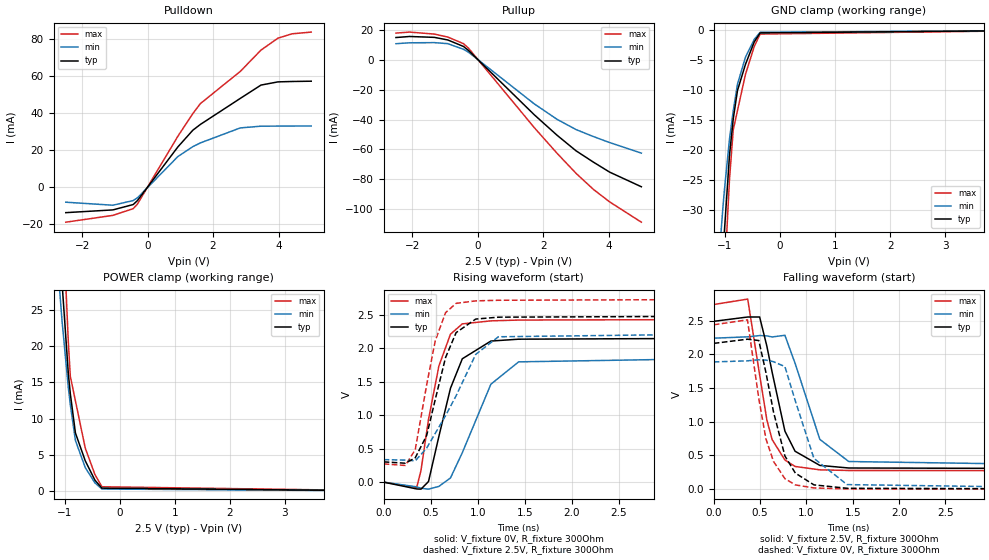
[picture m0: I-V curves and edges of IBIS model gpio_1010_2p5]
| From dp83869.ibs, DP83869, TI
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|   gpio_1010_2p5 Model
[Model]   gpio_1010_2p5
Model_type   I/O
Polarity   Non-Inverting
Enable   Active-Low
Vinl = 0.7
Vinh = 1.7
Vmeas = 1.25
Vref = 0
Cref = 2pF
Rref = 100000
|   typ   min   max
C_comp   1.246pF   1.092pF   1.323pF
| Where Nom  PVT is Nominal Process, 2.5V,  27C
|   Fast PVT is Strong Process,  2.75V, -40C
|   Slow PVT is Weak Process,   2.25V, 125C
[Voltage Range]   2.5   2.25   2.75
|Junction Temperature
[Temperature Range]   27   125   -40
[Pullup Reference]   2.5   2.25   2.75
[Pulldown Reference]   -0   0   -0
[Power Clamp Reference]   2.5   2.25   2.75
[GND Clamp Reference]   0   0   0
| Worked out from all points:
|   slope of the pulldown table from 0 to 0.375 V, typ, clamps not added: 41.6 ohm
|   slope of the pullup table from 0 to 0.375 V, typ, clamps not added: 45.3 ohm
|   GND clamp passes 1 mA (typ) near -0.41 V on its own axis
|   POWER clamp passes 1 mA (typ) near -0.41 V on its own axis
|   falling waveform, V_fixture 2.5V, R_fixture 300Ohm: 20-80 % time 217ps typ, 275ps min, 184ps max; typ from 2.49 V to 0.303 V
|   rising waveform, V_fixture 0V, R_fixture 300Ohm: 20-80 % time 245ps typ, 341ps min, 204ps max; typ from 0 V to 2.16 V
|   rising waveform, V_fixture 2.5V, R_fixture 300Ohm: 20-80 % time 240ps typ, 412ps min, 194ps max; typ from 0.303 V to 2.49 V
|   falling waveform, V_fixture 0V, R_fixture 300Ohm: 20-80 % time 225ps typ, 281ps min, 194ps max; typ from 2.16 V to 0 V
[Pulldown]
|   Voltage   I(typ)   I(min)   I(max)
-2.5V     -14.02mA   -8.348mA   -19.2mA
-1.061V   -12.53mA   -9.987mA   -15.5mA
-439.7mV  -9.613mA   -7.45mA    -11.86mA
-313.7mV  -7.525mA   -6.019mA   -9.423mA
923.7mV   21.64mA    16.41mA    27.43mA
1.382V    30.73mA    21.82mA    39.76mA
1.615V    33.9mA     23.86mA    45.22mA
2.833V    48.01mA    31.98mA    62.67mA
3.464V    55.23mA    32.92mA    74.21mA
3.983V    56.97mA    32.96mA    80.7mA
4.412V    57.18mA    32.99mA    83.06mA
5V        57.34mA    33.04mA    84mA
[GND Clamp]
|   Voltage   I(typ)   I(min)   I(max)
-2.5V     -325.5mA   -278mA     -374.2mA
-1.151V   -58.23mA   -45.14mA   -72.47mA
-1.062V   -42.41mA   -32.96mA   -53.36mA
-1.027V   -36.66mA   -28.83mA   -45.97mA
-1.002V   -32.89mA   -26.27mA   -40.56mA
-914.5mV  -20.87mA   -18.14mA   -24.92mA
-847mV    -14.84mA   -13.47mA   -16.66mA
-770.2mV  -10.08mA   -9.023mA   -13.45mA
-624.7mV  -5.69mA    -4.486mA   -7.365mA
-464.5mV  -1.919mA   -1.5mA     -2.671mA
-358.7mV  -429.3uA   -330.5uA   -624.3uA
5V        0A         0A         0A
[Pullup]
|   Voltage   I(typ)   I(min)   I(max)
-2.5V     15.13mA    10.98mA    18.12mA
-2.084V   15.84mA    11.59mA    18.79mA
-1.324V   15.24mA    11.7mA     17.45mA
-914.2mV  13.49mA    11mA       15.44mA
-434.5mV  9.127mA    7.208mA    11.01mA
-278.5mV  6.367mA    5.219mA    7.886mA
1.731V    -36.86mA   -29.53mA   -45.51mA
2.426V    -50.59mA   -39.87mA   -62.72mA
3.005V    -61.03mA   -46.75mA   -76.17mA
3.535V    -68.63mA   -51.44mA   -86.95mA
4.033V    -75.37mA   -55.48mA   -95.38mA
5V        -85.18mA   -62.57mA   -109mA
[POWER Clamp]
|   Voltage   I(typ)   I(min)   I(max)
-2.5V     383.1mA    300.3mA    465.8mA
-1.265V   71.48mA    49.28mA    97.33mA
-1.162V   48.95mA    35.07mA    69.59mA
-1.083V   35.08mA    27.15mA    48.58mA
-1.045V   28.71mA    23.46mA    40.29mA
-931.5mV  16.22mA    14.27mA    20.57mA
-895mV    13.42mA    11.91mA    15.82mA
-802.5mV  7.998mA    6.976mA    12.44mA
-624.2mV  4.163mA    3.227mA    5.917mA
-448.7mV  1.485mA    1.117mA    2.264mA
-321.9mV  387.1uA    265.3uA    577.2uA
5V        0A         0A         0A
[Ramp]
R_load = 300
|   typ   min   max
dV/dt_r   1.29559/2.4361e-10   1.12931/3.38984e-10   1.46232/2.02147e-10
dV/dt_f   1.31143/2.16396e-10   1.14136/2.75054e-10   1.47906/1.83887e-10
[Falling Waveform]
V_fixture = 2.5V
V_fixture_min = 2.25V
V_fixture_max = 2.75V
R_fixture = 300Ohm
C_fixture = 0F
|   Time   V(typ)   V(min)   V(max)
0s        2.489V     2.239V     2.738V
366.2ps   2.553V     2.259V     2.819V
495ps     2.553V     2.278V     1.695V
572.9ps   2.121V     2.273V     1.027V
630ps     1.733V     2.257V     734.9mV
767.8ps   861mV      2.282V     432.8mV
877.5ps   562.3mV    1.867V     336.9mV
1.145ns   352.4mV    737.7mV    286.5mV
1.457ns   313.9mV    410.1mV    277.1mV
5ns       303.2mV    337.2mV    272.9mV
[Rising Waveform]
V_fixture = 0V
V_fixture_min = 0V
V_fixture_max = 0V
R_fixture = 300Ohm
C_fixture = 0F
|   Time   V(typ)   V(min)   V(max)
0s        122.2uV    217uV      118.7uV
351.1ps   -101.6mV   -70.59mV   -80.43mV
396.8ps   -104.7mV   -90.87mV   173.7mV
476.8ps   9.173mV    -105mV     938.1mV
587.1ps   684.2mV    -63.34mV   1.737V
710.4ps   1.404V     62.53mV    2.213V
836.1ps   1.845V     439.9mV    2.367V
1.14ns    2.11V      1.465V     2.412V
1.435ns   2.138V     1.799V     2.424V
5ns       2.159V     1.882V     2.437V
[Rising Waveform]
V_fixture = 2.5V
V_fixture_min = 2.25V
V_fixture_max = 2.75V
R_fixture = 300Ohm
C_fixture = 0F
|   Time   V(typ)   V(min)   V(max)
0s        303.2mV    337.2mV    272.9mV
230ps     283.3mV    329.3mV    249.7mV
335.5ps   363.4mV    317.8mV    483.9mV
457ps     696.6mV    508.7mV    1.454V
549.2ps   1.24V      731.3mV    2.118V
658.2ps   1.864V     994.2mV    2.535V
770.3ps   2.236V     1.292V     2.674V
978.8ps   2.439V     1.911V     2.711V
1.22ns    2.467V     2.174V     2.72V
5ns       2.489V     2.239V     2.738V
[Falling Waveform]
|Gnd
V_fixture = 0V
V_fixture_min = 0V
V_fixture_max = 0V
R_fixture = 300Ohm
C_fixture = 0F
|   Time   V(typ)   V(min)   V(max)
0s        2.162V     1.887V     2.438V
363.6ps   2.224V     1.903V     2.511V
486ps     2.204V     1.919V     1.344V
562.9ps   1.73V      1.914V     746.4mV
645.3ps   1.141V     1.89V      409.8mV
767.8ps   491.8mV    1.818V     156.1mV
880.3ps   238.6mV    1.308V     63.45mV
1.081ns   63.64mV    456.4mV    18.15mV
1.439ns   13.29mV    67.67mV    4.069mV
5ns       120.6uV    214.4uV    118uV
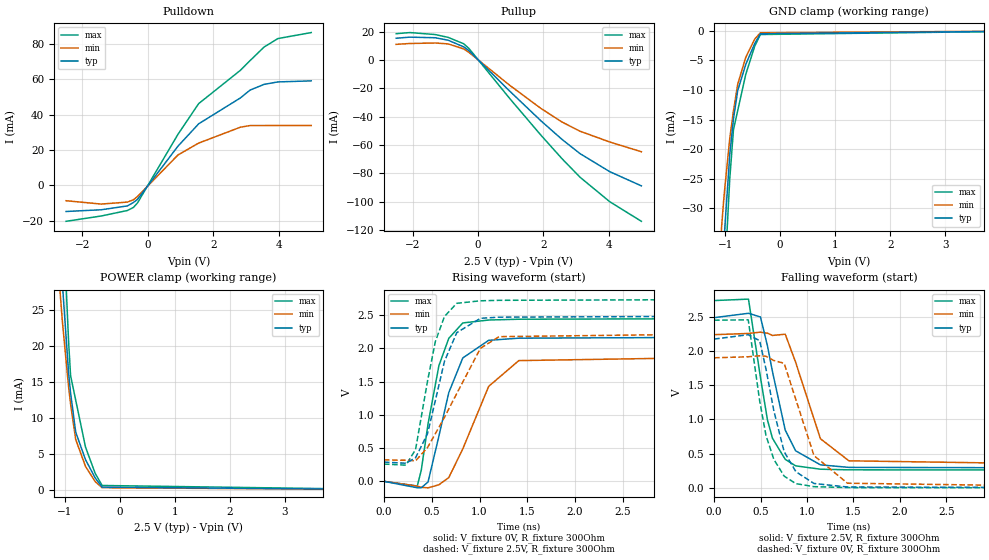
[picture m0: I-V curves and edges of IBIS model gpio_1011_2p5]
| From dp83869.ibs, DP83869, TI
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|   gpio_1011_2p5 Model
[Model]   gpio_1011_2p5
Model_type   I/O
Polarity   Non-Inverting
Enable   Active-Low
Vinl = 0.7
Vinh = 1.7
Vmeas = 1.25
Vref = 0
Cref = 2pF
Rref = 100000
|   typ   min   max
C_comp   1.246pF   1.092pF   1.323pF
| Where Nom  PVT is Nominal Process, 2.5V,  27C
|   Fast PVT is Strong Process,  2.75V, -40C
|   Slow PVT is Weak Process,   2.25V, 125C
[Voltage Range]   2.5   2.25   2.75
|Junction Temperature
[Temperature Range]   27   125   -40
[Pullup Reference]   2.5   2.25   2.75
[Pulldown Reference]   0   0   -0
[Power Clamp Reference]   2.5   2.25   2.75
[GND Clamp Reference]   0   0   0
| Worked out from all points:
|   slope of the pulldown table from 0 to 0.375 V, typ, clamps not added: 39.6 ohm
|   slope of the pullup table from 0 to 0.375 V, typ, clamps not added: 43.2 ohm
|   GND clamp passes 1 mA (typ) near -0.39 V on its own axis
|   POWER clamp passes 1 mA (typ) near -0.39 V on its own axis
|   falling waveform, V_fixture 2.5V, R_fixture 300Ohm: 20-80 % time 218ps typ, 276ps min, 186ps max; typ from 2.49 V to 0.289 V
|   rising waveform, V_fixture 0V, R_fixture 300Ohm: 20-80 % time 243ps typ, 340ps min, 201ps max; typ from 0 V to 2.17 V
|   rising waveform, V_fixture 2.5V, R_fixture 300Ohm: 20-80 % time 238ps typ, 403ps min, 190ps max; typ from 0.289 V to 2.49 V
|   falling waveform, V_fixture 0V, R_fixture 300Ohm: 20-80 % time 230ps typ, 286ps min, 196ps max; typ from 2.18 V to 0 V
[Pulldown]
|   Voltage   I(typ)   I(min)   I(max)
-2.5V     -14.82mA   -8.722mA   -20.38mA
-1.425V   -13.85mA   -10.62mA   -17.38mA
-624.7mV  -11.67mA   -9.497mA   -14.26mA
-441mV    -9.736mA   -8.215mA   -12.54mA
-315mV    -7.966mA   -6.331mA   -9.979mA
923.7mV   22.2mA     17.21mA    28.92mA
1.556V    34.85mA    23.93mA    46.29mA
2.833V    49.52mA    32.94mA    65.17mA
3.127V    53.94mA    33.86mA    70.63mA
3.556V    57.2mA     33.87mA    78.33mA
3.981V    58.59mA    33.89mA    83.16mA
5V        59.18mA    33.92mA    86.55mA
[GND Clamp]
|   Voltage   I(typ)   I(min)   I(max)
-2.5V     -325.5mA   -278mA     -374.2mA
-1.151V   -58.23mA   -45.14mA   -72.47mA
-1.062V   -42.41mA   -32.96mA   -53.36mA
-1.027V   -36.66mA   -28.83mA   -45.97mA
-1.002V   -32.9mA    -26.28mA   -40.59mA
-914.8mV  -20.9mA    -18.16mA   -24.97mA
-847.5mV  -14.87mA   -13.5mA    -16.7mA
-770.2mV  -10.08mA   -9.023mA   -13.47mA
-624.7mV  -5.69mA    -4.486mA   -7.36mA
-461.2mV  -2.153mA   -1.398mA   -2.59mA
-358.7mV  -493.6uA   -330.5uA   -623.8uA
5V        0A         0A         0A
[Pullup]
|   Voltage   I(typ)   I(min)   I(max)
-2.5V     15.37mA    11.05mA    18.57mA
-2.087V   16.14mA    11.66mA    19.37mA
-1.306V   15.71mA    12.01mA    17.98mA
-910.5mV  13.97mA    11.37mA    15.98mA
-431.2mV  9.238mA    7.786mA    11.42mA
-272.2mV  6.53mA     5.328mA    8.089mA
968.7mV   -21.86mA   -17.77mA   -27.05mA
1.926V    -42.87mA   -34.14mA   -53mA
2.569V    -55.95mA   -43.72mA   -69.55mA
3.124V    -66.06mA   -50.24mA   -82.69mA
4.033V    -78.78mA   -57.85mA   -99.98mA
5V        -88.79mA   -64.71mA   -113.8mA
[POWER Clamp]
|   Voltage   I(typ)   I(min)   I(max)
-2.5V     383.1mA    300.3mA    465.8mA
-1.265V   71.46mA    49.27mA    97.31mA
-1.162V   48.95mA    35.07mA    69.58mA
-1.083V   35.1mA     27.16mA    48.61mA
-1.045V   28.71mA    23.46mA    40.28mA
-931.5mV  16.22mA    14.27mA    20.57mA
-895.3mV  13.44mA    11.92mA    15.85mA
-802.5mV  7.998mA    6.976mA    12.45mA
-624.7mV  4.171mA    3.233mA    5.929mA
-449.2mV  1.632mA    1.121mA    2.272mA
-321.9mV  342.6uA    265.3uA    574.7uA
5V        0A         0A         0A
[Ramp]
R_load = 300
|   typ   min   max
dV/dt_r   1.30437/2.41683e-10   1.13819/3.37972e-10   1.47073/1.99631e-10
dV/dt_f   1.31997/2.17179e-10   1.15017/2.7626e-10   1.48714/1.85126e-10
[Falling Waveform]
V_fixture = 2.5V
V_fixture_min = 2.25V
V_fixture_max = 2.75V
R_fixture = 300Ohm
C_fixture = 0F
|   Time   V(typ)   V(min)   V(max)
0s        2.489V     2.24V      2.739V
370.5ps   2.553V     2.258V     2.76V
499.4ps   2.499V     2.277V     1.616V
575ps     2.076V     2.262V     992.1mV
629ps     1.699V     2.229V     724.9mV
766.3ps   844.2mV    2.247V     416.6mV
878ps     542.3mV    1.838V     322.1mV
1.145ns   336.7mV    718.9mV    272.9mV
1.452ns   299.6mV    395.8mV    263.8mV
5ns       289.5mV    322.9mV    260mV
[Rising Waveform]
V_fixture = 0V
V_fixture_min = 0V
V_fixture_max = 0V
R_fixture = 300Ohm
C_fixture = 0F
|   Time   V(typ)   V(min)   V(max)
0s        115.2uV    205.9uV    111.7uV
349ps     -96.46mV   -72.3mV    -69.82mV
391ps     -95.36mV   -89.31mV   171.5mV
461.4ps   -9.328mV   -97.74mV   863.3mV
575ps     679.1mV    -51.03mV   1.739V
678.5ps   1.335V     56.44mV    2.15V
825.2ps   1.855V     488.8mV    2.381V
1.096ns   2.12V      1.428V     2.425V
1.411ns   2.152V     1.815V     2.437V
5ns       2.174V     1.897V     2.451V
[Rising Waveform]
V_fixture = 2.5V
V_fixture_min = 2.25V
V_fixture_max = 2.75V
R_fixture = 300Ohm
C_fixture = 0F
|   Time   V(typ)   V(min)   V(max)
0s        289.5mV    322.9mV    260mV
228.5ps   272.7mV    317.1mV    243.7mV
330.5ps   353.4mV    307.5mV    475.8mV
456.5ps   718.4mV    509.4mV    1.511V
538.2ps   1.217V     717mV      2.104V
633.5ps   1.806V     963.1mV    2.479V
761.9ps   2.235V     1.32V      2.676V
1.01ns    2.451V     2.001V     2.714V
1.205ns   2.468V     2.175V     2.721V
5ns       2.489V     2.24V      2.739V
[Falling Waveform]
|Gnd
V_fixture = 0V
V_fixture_min = 0V
V_fixture_max = 0V
R_fixture = 300Ohm
C_fixture = 0F
|   Time   V(typ)   V(min)   V(max)
0s        2.176V     1.902V     2.452V
368ps     2.239V     1.917V     2.457V
491.1ps   2.152V     1.932V     1.271V
559.4ps   1.735V     1.924V     764.3mV
643.3ps   1.129V     1.862V     417.6mV
754.7ps   528.7mV    1.822V     171.7mV
881.7ps   235.4mV    1.287V     61.47mV
1.076ns   64.01mV    471.7mV    17.72mV
1.436ns   12.68mV    68.06mV    3.963mV
5ns       114.1uV    204.1uV    111uV
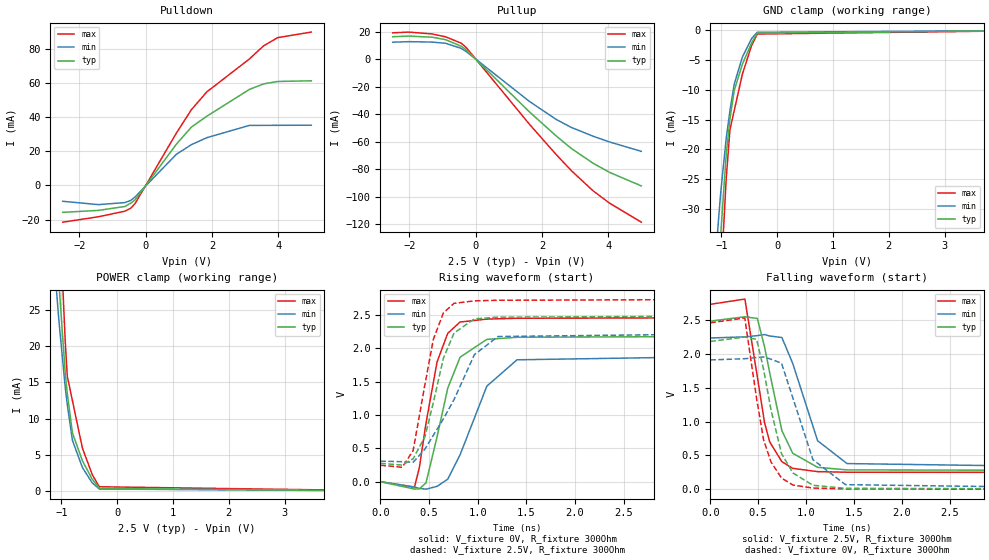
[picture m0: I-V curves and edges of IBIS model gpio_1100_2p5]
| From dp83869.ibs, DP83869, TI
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|   gpio_1100_2p5 Model
[Model]   gpio_1100_2p5
Model_type   I/O
Polarity   Non-Inverting
Enable   Active-Low
Vinl = 0.7
Vinh = 1.7
Vmeas = 1.25
Vref = 0
Cref = 2pF
Rref = 100000
|   typ   min   max
C_comp   1.246pF   1.092pF   1.323pF
| Where Nom  PVT is Nominal Process, 2.5V,  27C
|   Fast PVT is Strong Process,  2.75V, -40C
|   Slow PVT is Weak Process,   2.25V, 125C
[Voltage Range]   2.5   2.25   2.75
|Junction Temperature
[Temperature Range]   27   125   -40
[Pullup Reference]   2.5   2.25   2.75
[Pulldown Reference]   0   -0   0
[Power Clamp Reference]   2.5   2.25   2.75
[GND Clamp Reference]   0   0   0
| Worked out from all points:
|   slope of the pulldown table from 0 to 0.375 V, typ, clamps not added: 37.5 ohm
|   slope of the pullup table from 0 to 0.375 V, typ, clamps not added: 41.2 ohm
|   GND clamp passes 1 mA (typ) near -0.39 V on its own axis
|   POWER clamp passes 1 mA (typ) near -0.39 V on its own axis
|   falling waveform, V_fixture 2.5V, R_fixture 300Ohm: 20-80 % time 208ps typ, 267ps min, 175ps max; typ from 2.49 V to 0.275 V
|   rising waveform, V_fixture 0V, R_fixture 300Ohm: 20-80 % time 229ps typ, 324ps min, 190ps max; typ from 0 V to 2.19 V
|   rising waveform, V_fixture 2.5V, R_fixture 300Ohm: 20-80 % time 229ps typ, 400ps min, 182ps max; typ from 0.275 V to 2.49 V
|   falling waveform, V_fixture 0V, R_fixture 300Ohm: 20-80 % time 212ps typ, 270ps min, 182ps max; typ from 2.19 V to 0 V
[Pulldown]
|   Voltage   I(typ)   I(min)   I(max)
-2.5V     -15.78mA   -9.274mA   -21.54mA
-1.423V   -14.62mA   -11.23mA   -18.36mA
-624.7mV  -12.33mA   -10.05mA   -15.07mA
-440.7mV  -10.29mA   -8.687mA   -13.25mA
-314.7mV  -8.413mA   -6.69mA    -10.54mA
924.5mV   24.12mA    18.23mA    30.6mA
1.381V    34.24mA    23.94mA    44.44mA
1.847V    40.62mA    28.03mA    54.9mA
3.128V    56.31mA    35.23mA    74.16mA
3.558V    59.58mA    35.26mA    81.89mA
3.982V    61.01mA    35.29mA    86.7mA
4.999V    61.41mA    35.36mA    89.98mA
|   4.99863   0.0856237   0.0353591   0.0899851
|   4.99884   0.189902   0.0353591   0.196057
|   4.99934   0.444693   0.339274   0.455228
|   4.99938   0.444705   0.368152   0.479855
|   4.99942   0.444715   0.389729   0.479866
|   5   0.444866   0.389855   0.480043
[GND Clamp]
|   Voltage   I(typ)   I(min)   I(max)
-2.5V     -325.5mA   -278mA     -374.2mA
-1.151V   -58.23mA   -45.14mA   -72.46mA
-1.062V   -42.41mA   -32.96mA   -53.35mA
-1.027V   -36.66mA   -28.83mA   -45.96mA
-1.003V   -32.98mA   -26.33mA   -40.68mA
-915.3mV  -20.96mA   -18.2mA    -25.04mA
-847.2mV  -14.86mA   -13.48mA   -16.68mA
-770.2mV  -10.08mA   -9.023mA   -13.46mA
-624.7mV  -5.69mA    -4.486mA   -7.363mA
-460.9mV  -2.148mA   -1.394mA   -2.584mA
-358.7mV  -493.6uA   -330.5uA   -624.1uA
5V        0A         0A         0A
[Pullup]
|   Voltage   I(typ)   I(min)   I(max)
-2.5V     16.6mA     12.62mA    19.44mA
-2.012V   17.05mA    13mA       19.97mA
-1.312V   16.25mA    12.68mA    18.61mA
-906.7mV  14.45mA    11.82mA    16.53mA
-430.2mV  9.606mA    8.072mA    11.86mA
-268.2mV  6.732mA    5.489mA    8.337mA
1.615V    -37.99mA   -30.4mA    -46.93mA
2.426V    -55.62mA   -43.62mA   -69.15mA
2.889V    -64.86mA   -49.54mA   -81.02mA
3.539V    -75.54mA   -55.89mA   -95.63mA
4.04V     -82.27mA   -60.11mA   -104.7mA
5V        -92.15mA   -66.96mA   -118.6mA
[POWER Clamp]
|   Voltage   I(typ)   I(min)   I(max)
-2.5V     383.1mA    300.3mA    465.8mA
-1.265V   71.44mA    49.26mA    97.29mA
-1.162V   48.95mA    35.07mA    69.59mA
-1.083V   35.06mA    27.14mA    48.54mA
-1.045V   28.71mA    23.46mA    40.28mA
-931.5mV  16.22mA    14.27mA    20.57mA
-895mV    13.42mA    11.91mA    15.83mA
-802.5mV  7.998mA    6.976mA    12.44mA
-624.4mV  4.167mA    3.23mA     5.922mA
-448.9mV  1.629mA    1.119mA    2.268mA
-321.9mV  342.6uA    265.3uA    574.8uA
5V        0A         0A         0A
[Ramp]
R_load = 300
|   typ   min   max
dV/dt_r   1.31236/2.27611e-10   1.14637/3.21026e-10   1.47832/1.88285e-10
dV/dt_f   1.32863/2.07344e-10   1.15968/2.67863e-10   1.49506/1.74746e-10
[Falling Waveform]
V_fixture = 2.5V
V_fixture_min = 2.25V
V_fixture_max = 2.75V
R_fixture = 300Ohm
C_fixture = 0F
|   Time   V(typ)   V(min)   V(max)
0s        2.49V      2.24V      2.739V
361.5ps   2.555V     2.257V     2.817V
491.6ps   2.529V     2.275V     1.664V
566.4ps   2.113V     2.291V     988mV
620.5ps   1.726V     2.27V      700.3mV
748ps     866.1mV    2.247V     406.8mV
861.1ps   532.1mV    1.863V     308.5mV
1.121ns   323.7mV    717.5mV    260.1mV
1.428ns   285.7mV    379.5mV    251.1mV
5ns       275.4mV    307.4mV    247.3mV
[Rising Waveform]
V_fixture = 0V
V_fixture_min = 0V
V_fixture_max = 0V
R_fixture = 300Ohm
C_fixture = 0F
|   Time   V(typ)   V(min)   V(max)
0s        110.5uV    196.4uV    107.1uV
351.3ps   -110mV     -80.11mV   -81.88mV
401.3ps   -108.1mV   -100.7mV   209.5mV
469.6ps   -18.14mV   -112.1mV   875.8mV
583.4ps   672.2mV    -69.84mV   1.796V
693.1ps   1.4V       37.45mV    2.225V
819.7ps   1.867V     402.2mV    2.395V
1.095ns   2.134V     1.433V     2.438V
1.405ns   2.166V     1.828V     2.451V
5ns       2.187V     1.911V     2.464V
[Rising Waveform]
V_fixture = 2.5V
V_fixture_min = 2.25V
V_fixture_max = 2.75V
R_fixture = 300Ohm
C_fixture = 0F
|   Time   V(typ)   V(min)   V(max)
0s        275.4mV    307.4mV    247.3mV
224.7ps   248.9mV    300mV      216.2mV
337.9ps   344.1mV    291.1mV    468.1mV
459.9ps   678.9mV    491.9mV    1.466V
545.3ps   1.187V     696mV      2.134V
648.5ps   1.852V     942.4mV    2.532V
758.1ps   2.23V      1.232V     2.675V
967.1ps   2.442V     1.906V     2.712V
1.21ns    2.468V     2.177V     2.721V
5ns       2.49V      2.24V      2.739V
[Falling Waveform]
|Gnd
V_fixture = 0V
V_fixture_min = 0V
V_fixture_max = 0V
R_fixture = 300Ohm
C_fixture = 0F
|   Time   V(typ)   V(min)   V(max)
0s        2.189V     1.915V     2.465V
360.2ps   2.254V     1.933V     2.537V
484.3ps   2.22V      1.95V      1.337V
556.9ps   1.774V     1.958V     731.6mV
634.5ps   1.174V     1.926V     402.5mV
743.8ps   526.5mV    1.867V     164.4mV
863.1ps   240.8mV    1.349V     61.17mV
1.072ns   57.5mV     436.8mV    16.43mV
1.412ns   12.44mV    66.83mV    3.665mV
5ns       109uV      194.3uV    106.5uV
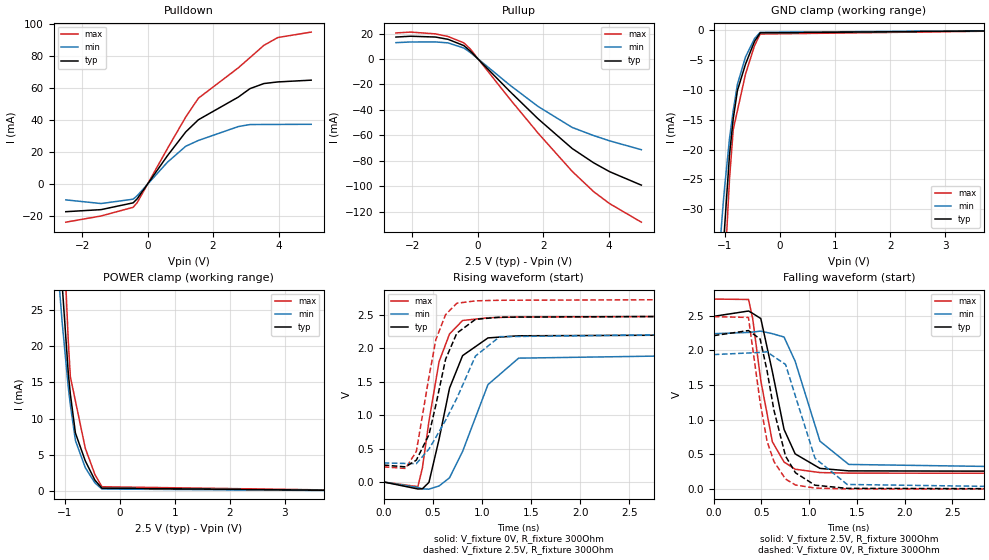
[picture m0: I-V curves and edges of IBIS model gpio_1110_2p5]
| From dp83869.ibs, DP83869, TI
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|   gpio_1110_2p5 Model
[Model]   gpio_1110_2p5
Model_type   I/O
Polarity   Non-Inverting
Enable   Active-Low
Vinl = 0.7
Vinh = 1.7
Vmeas = 1.25
Vref = 0
Cref = 2pF
Rref = 100000
|   typ   min   max
C_comp   1.246pF   1.092pF   1.323pF
| Where Nom  PVT is Nominal Process, 2.5V,  27C
|   Fast PVT is Strong Process,  2.75V, -40C
|   Slow PVT is Weak Process,   2.25V, 125C
[Voltage Range]   2.5   2.25   2.75
|Junction Temperature
[Temperature Range]   27   125   -40
[Pullup Reference]   2.5   2.25   2.75
[Pulldown Reference]   0   0   0
[Power Clamp Reference]   2.5   2.25   2.75
[GND Clamp Reference]   0   0   0
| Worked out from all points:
|   slope of the pulldown table from 0 to 0.375 V, typ, clamps not added: 34.1 ohm
|   slope of the pullup table from 0 to 0.375 V, typ, clamps not added: 37.6 ohm
|   GND clamp passes 1 mA (typ) near -0.41 V on its own axis
|   POWER clamp passes 1 mA (typ) near -0.41 V on its own axis
|   falling waveform, V_fixture 2.5V, R_fixture 300Ohm: 20-80 % time 206ps typ, 268ps min, 174ps max; typ from 2.49 V to 0.254 V
|   rising waveform, V_fixture 0V, R_fixture 300Ohm: 20-80 % time 221ps typ, 316ps min, 180ps max; typ from 0 V to 2.21 V
|   rising waveform, V_fixture 2.5V, R_fixture 300Ohm: 20-80 % time 221ps typ, 384ps min, 173ps max; typ from 0.254 V to 2.49 V
|   falling waveform, V_fixture 0V, R_fixture 300Ohm: 20-80 % time 214ps typ, 274ps min, 181ps max; typ from 2.21 V to 0 V
[Pulldown]
|   Voltage   I(typ)   I(min)   I(max)
-2.5V     -17.33mA   -9.954mA   -23.87mA
-1.423V   -16.04mA   -12.24mA   -20mA
-441.8mV  -11.8mA    -9.516mA   -14.58mA
-316.6mV  -9.235mA   -7.34mA    -11.62mA
608.9mV   17.67mA    13.59mA    22.15mA
1.166V    32.43mA    23.49mA    41.73mA
1.552V    40.01mA    27.1mA     53.45mA
2.772V    54.14mA    35.76mA    72.39mA
3.127V    59.4mA     37.02mA    78.74mA
3.556V    62.6mA     37.06mA    86.45mA
3.981V    63.59mA    37.09mA    91.29mA
5V        64.7mA     37.17mA    94.67mA
[GND Clamp]
|   Voltage   I(typ)   I(min)   I(max)
-2.5V     -325.5mA   -278mA     -374.2mA
-1.151V   -58.23mA   -45.14mA   -72.46mA
-1.062V   -42.41mA   -32.96mA   -53.35mA
-1.027V   -36.66mA   -28.83mA   -45.97mA
-1.003V   -32.95mA   -26.32mA   -40.65mA
-914.9mV  -20.92mA   -18.17mA   -24.99mA
-846.8mV  -14.83mA   -13.46mA   -16.65mA
-770.2mV  -10.08mA   -9.023mA   -13.45mA
-624.7mV  -5.69mA    -4.486mA   -7.366mA
-460.6mV  -1.851mA   -1.389mA   -2.575mA
-358.7mV  -429.3uA   -330.5uA   -624.4uA
5V        0A         0A         0A
[Pullup]
|   Voltage   I(typ)   I(min)   I(max)
-2.5V     17.24mA    12.83mA    20.46mA
-2.055V   17.88mA    13.35mA    21.14mA
-1.294V   17.25mA    13.42mA    19.74mA
-907.5mV  15.45mA    12.64mA    17.68mA
-423.8mV  10.5mA     8.595mA    12.66mA
-232.6mV  6.29mA     5.202mA    7.973mA
971.7mV   -25.27mA   -20.36mA   -31.19mA
1.846V    -47.13mA   -37.4mA    -58.41mA
2.887V    -70.46mA   -53.87mA   -88.43mA
3.539V    -81.65mA   -60.23mA   -104.3mA
4.031V    -88.68mA   -64.42mA   -113.8mA
5V        -99.26mA   -71.38mA   -128.4mA
[POWER Clamp]
|   Voltage   I(typ)   I(min)   I(max)
-2.5V     383.1mA    300.3mA    465.8mA
-1.265V   71.41mA    49.24mA    97.24mA
-1.162V   48.95mA    35.07mA    69.59mA
-1.083V   35.03mA    27.12mA    48.5mA
-1.045V   28.71mA    23.46mA    40.27mA
-931.5mV  16.22mA    14.27mA    20.59mA
-894.6mV  13.4mA     11.89mA    15.79mA
-802.5mV  7.998mA    6.976mA    12.43mA
-624.1mV  4.161mA    3.225mA    5.914mA
-448.6mV  1.483mA    1.115mA    2.261mA
-321.9mV  387.1uA    265.3uA    577.3uA
5V        0A         0A         0A
[Ramp]
R_load = 300
|   typ   min   max
dV/dt_r   1.32663/2.19319e-10   1.16103/3.13184e-10   1.49186/1.79671e-10
dV/dt_f   1.34195/2.05743e-10   1.1735/2.67224e-10   1.50763/1.73445e-10
[Falling Waveform]
V_fixture = 2.5V
V_fixture_min = 2.25V
V_fixture_max = 2.75V
R_fixture = 300Ohm
C_fixture = 0F
|   Time   V(typ)   V(min)   V(max)
0s        2.491V     2.241V     2.74V
364.7ps   2.568V     2.259V     2.734V
408.1ps   2.533V     2.265V     2.456V
493ps     2.459V     2.278V     1.563V
614.2ps   1.694V     2.241V     683.1mV
736.6ps   861.4mV    2.193V     391.4mV
853.2ps   508.6mV    1.843V     287.4mV
1.113ns   299.6mV    691.9mV    239.5mV
1.415ns   263.6mV    356.4mV    231mV
5ns       254mV      285.1mV    227.2mV
[Rising Waveform]
V_fixture = 0V
V_fixture_min = 0V
V_fixture_max = 0V
R_fixture = 300Ohm
C_fixture = 0F
|   Time   V(typ)   V(min)   V(max)
0s        100.2uV    180uV      96.95uV
348ps     -104.5mV   -82.28mV   -69.37mV
393.9ps   -101.9mV   -102.1mV   209.7mV
460.9ps   -4.904mV   -107.2mV   911.5mV
563.8ps   642.3mV    -59.16mV   1.803V
670.1ps   1.406V     63.2mV     2.217V
803ps     1.893V     458.3mV    2.419V
1.061ns   2.158V     1.459V     2.46V
1.373ns   2.19V      1.855V     2.472V
5ns       2.211V     1.935V     2.487V
[Rising Waveform]
V_fixture = 2.5V
V_fixture_min = 2.25V
V_fixture_max = 2.75V
R_fixture = 300Ohm
C_fixture = 0F
|   Time   V(typ)   V(min)   V(max)
0s        254mV      285.1mV    227.2mV
222.1ps   226.5mV    278.1mV    203.1mV
332.5ps   327.8mV    274.9mV    457.4mV
460.9ps   708.6mV    493.6mV    1.574V
531.6ps   1.159V     670.5mV    2.136V
630.1ps   1.84V      925.2mV    2.507V
744.4ps   2.229V     1.254V     2.677V
933.9ps   2.436V     1.887V     2.713V
1.181ns   2.469V     2.177V     2.722V
5ns       2.491V     2.241V     2.74V
[Falling Waveform]
|Gnd
V_fixture = 0V
V_fixture_min = 0V
V_fixture_max = 0V
R_fixture = 300Ohm
C_fixture = 0F
|   Time   V(typ)   V(min)   V(max)
0s        2.213V     1.94V      2.487V
363.2ps   2.286V     1.963V     2.475V
486ps     2.164V     1.971V     1.253V
558.3ps   1.708V     1.98V      692.3mV
630.6ps   1.138V     1.909V     399.2mV
752.2ps   476.9mV    1.798V     145.2mV
856.4ps   236.1mV    1.337V     59.78mV
1.061ns   57.01mV    446.9mV    16.05mV
1.398ns   11.97mV    67.95mV    3.55mV
5ns       99.29uV    177.8uV    96.25uV
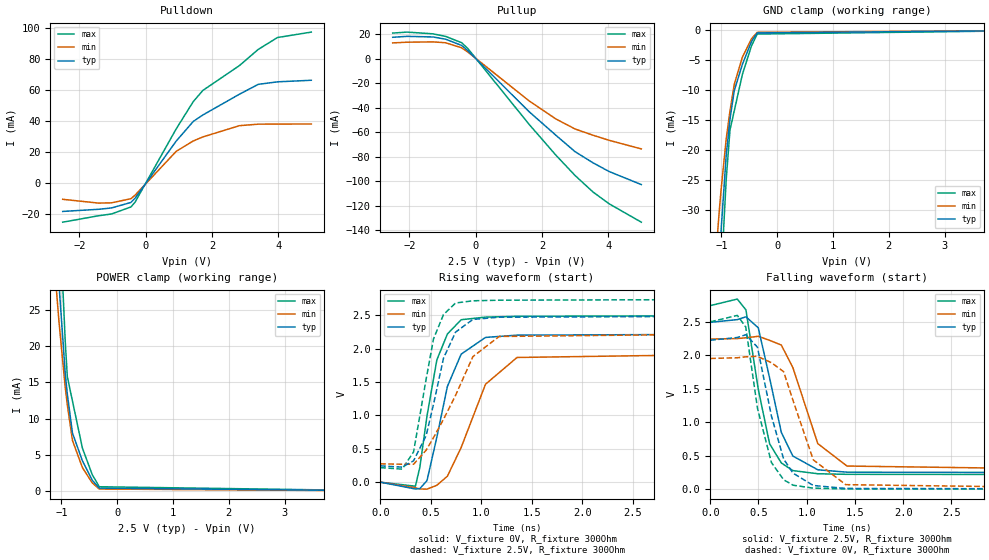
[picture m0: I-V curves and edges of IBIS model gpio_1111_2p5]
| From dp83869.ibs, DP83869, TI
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|   gpio_1111_2p5 Model
[Model]   gpio_1111_2p5
Model_type   I/O
Polarity   Non-Inverting
Enable   Active-Low
Vinl = 0.7
Vinh = 1.7
Vmeas = 1.25
Vref = 0
Cref = 2pF
Rref = 100000
|   typ   min   max
C_comp   1.246pF   1.092pF   1.323pF
| Where Nom  PVT is Nominal Process, 2.5V,  27C
|   Fast PVT is Strong Process,  2.75V, -40C
|   Slow PVT is Weak Process,   2.25V, 125C
[Voltage Range]   2.5   2.25   2.75
|Junction Temperature
[Temperature Range]   27   125   -40
[Pullup Reference]   2.5   2.25   2.75
[Pulldown Reference]   0   -0   -0
[Power Clamp Reference]   2.5   2.25   2.75
[GND Clamp Reference]   0   0   0
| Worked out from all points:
|   slope of the pulldown table from 0 to 0.375 V, typ, clamps not added: 32.8 ohm
|   slope of the pullup table from 0 to 0.375 V, typ, clamps not added: 36.1 ohm
|   GND clamp passes 1 mA (typ) near -0.41 V on its own axis
|   POWER clamp passes 1 mA (typ) near -0.41 V on its own axis
|   falling waveform, V_fixture 2.5V, R_fixture 300Ohm: 20-80 % time 208ps typ, 270ps min, 176ps max; typ from 2.49 V to 0.244 V
|   rising waveform, V_fixture 0V, R_fixture 300Ohm: 20-80 % time 219ps typ, 313ps min, 177ps max; typ from 0 V to 2.22 V
|   rising waveform, V_fixture 2.5V, R_fixture 300Ohm: 20-80 % time 218ps typ, 376ps min, 169ps max; typ from 0.244 V to 2.49 V
|   falling waveform, V_fixture 0V, R_fixture 300Ohm: 20-80 % time 215ps typ, 280ps min, 183ps max; typ from 2.22 V to 0 V
[Pulldown]
|   Voltage   I(typ)   I(min)   I(max)
-2.5V     -18.13mA   -10.33mA   -25.05mA
-1.422V   -16.76mA   -12.76mA   -20.92mA
-1.028V   -15.89mA   -12.6mA    -19.76mA
-442.6mV  -12.34mA   -9.944mA   -15.26mA
-317.3mV  -9.668mA   -7.669mA   -12.17mA
923.7mV   27.13mA    20.53mA    34.97mA
1.439V    39.78mA    27.22mA    52.54mA
1.73V     43.96mA    29.81mA    59.75mA
2.829V    57.25mA    37.04mA    75.66mA
3.398V    63.62mA    38.01mA    86.09mA
3.979V    65.25mA    38.06mA    93.75mA
5V        66.26mA    38.14mA    97.25mA
[GND Clamp]
|   Voltage   I(typ)   I(min)   I(max)
-2.5V     -325.5mA   -278mA     -374.2mA
-1.151V   -58.23mA   -45.14mA   -72.47mA
-1.062V   -42.41mA   -32.96mA   -53.36mA
-1.027V   -36.66mA   -28.83mA   -45.98mA
-1.002V   -32.86mA   -26.26mA   -40.53mA
-914.3mV  -20.85mA   -18.12mA   -24.89mA
-846.8mV  -14.83mA   -13.46mA   -16.65mA
-770.2mV  -10.08mA   -9.023mA   -13.45mA
-624.7mV  -5.69mA    -4.486mA   -7.367mA
-460.6mV  -1.85mA    -1.389mA   -2.574mA
-358.7mV  -429.3uA   -330.5uA   -624.5uA
5V        0A         0A         0A
[Pullup]
|   Voltage   I(typ)   I(min)   I(max)
-2.5V     17.48mA    12.9mA     20.91mA
-2.068V   18.24mA    13.46mA    21.72mA
-1.283V   17.73mA    13.73mA    20.29mA
-905.2mV  15.93mA    13.02mA    18.23mA
-420.8mV  10.84mA    8.9mA      13.06mA
-232.6mV  6.531mA    5.405mA    8.289mA
1.615V    -43.24mA   -34.43mA   -53.57mA
2.424V    -62.49mA   -49.19mA   -78.74mA
3.002V    -75.87mA   -57.35mA   -95.32mA
3.54V     -84.91mA   -62.41mA   -108.7mA
4.029V    -92.06mA   -66.59mA   -118.4mA
5V        -102.7mA   -73.6mA    -133.4mA
[POWER Clamp]
|   Voltage   I(typ)   I(min)   I(max)
-2.5V     383.1mA    300.3mA    465.8mA
-1.265V   71.4mA     49.23mA    97.23mA
-1.162V   48.95mA    35.07mA    69.59mA
-1.083V   35.06mA    27.13mA    48.54mA
-1.045V   28.71mA    23.46mA    40.27mA
-931.5mV  16.22mA    14.27mA    20.59mA
-894.8mV  13.41mA    11.9mA     15.81mA
-802.5mV  7.998mA    6.976mA    12.43mA
-624.1mV  4.16mA     3.225mA    5.913mA
-448.6mV  1.483mA    1.115mA    2.261mA
-321.9mV  387.1uA    265.3uA    577.3uA
5V        0A         0A         0A
[Ramp]
R_load = 300
|   typ   min   max
dV/dt_r   1.33299/2.1679e-10   1.16759/3.1057e-10   1.49788/1.77052e-10
dV/dt_f   1.348/2.07407e-10   1.17986/2.70157e-10   1.51328/1.7541e-10
[Falling Waveform]
V_fixture = 2.5V
V_fixture_min = 2.25V
V_fixture_max = 2.75V
R_fixture = 300Ohm
C_fixture = 0F
|   Time   V(typ)   V(min)   V(max)
0s        2.491V     2.241V     2.74V
280.3ps   2.531V     2.248V     2.838V
369.7ps   2.573V     2.26V      2.677V
497.8ps   2.409V     2.282V     1.491V
615.3ps   1.66V      2.222V     677.1mV
736.9ps   847mV      2.151V     391.2mV
856ps     495mV      1.817V     277.7mV
1.115ns   289.4mV    680.1mV    230.2mV
1.418ns   253.6mV    345.2mV    221.6mV
5ns       244.3mV    274.8mV    218.2mV
[Rising Waveform]
V_fixture = 0V
V_fixture_min = 0V
V_fixture_max = 0V
R_fixture = 300Ohm
C_fixture = 0F
|   Time   V(typ)   V(min)   V(max)
0s        94.62uV    172.2uV    91.48uV
347.5ps   -102.1mV   -84.15mV   -60.28mV
391.4ps   -96.27mV   -101.1mV   221.6mV
462.3ps   23.43mV    -104.6mV   990.2mV
559.7ps   673.1mV    -46.46mV   1.829V
664ps     1.432V     89.2mV     2.217V
800.4ps   1.916V     519.1mV    2.431V
1.041ns   2.166V     1.465V     2.47V
1.353ns   2.2V       1.866V     2.482V
5ns       2.222V     1.946V     2.497V
[Rising Waveform]
V_fixture = 2.5V
V_fixture_min = 2.25V
V_fixture_max = 2.75V
R_fixture = 300Ohm
C_fixture = 0F
|   Time   V(typ)   V(min)   V(max)
0s        244.3mV    274.8mV    218.2mV
216.6ps   225mV      268.3mV    194.9mV
329.6ps   320.4mV    268.4mV    453mV
453.1ps   693.8mV    476.7mV    1.536V
526.9ps   1.165V     667.1mV    2.145V
625.6ps   1.855V     940.8mV    2.508V
745.1ps   2.246V     1.3V       2.681V
916.4ps   2.435V     1.879V     2.714V
1.176ns   2.469V     2.18V      2.723V
5ns       2.491V     2.241V     2.74V
[Falling Waveform]
|Gnd
V_fixture = 0V
V_fixture_min = 0V
V_fixture_max = 0V
R_fixture = 300Ohm
C_fixture = 0F
|   Time   V(typ)   V(min)   V(max)
0s        2.224V     1.951V     2.498V
280.3ps   2.264V     1.962V     2.594V
367.9ps   2.305V     1.976V     2.421V
489.2ps   2.12V      1.983V     1.209V
634.2ps   1.092V     1.888V     397.4mV
760.7ps   450.4mV    1.754V     140.3mV
858.6ps   238.9mV    1.321V     59.59mV
1.068ns   55.41mV    438.6mV    15.21mV
1.404ns   11.29mV    67.16mV    3.462mV
5ns       94.57uV    170.9uV    91.28uV
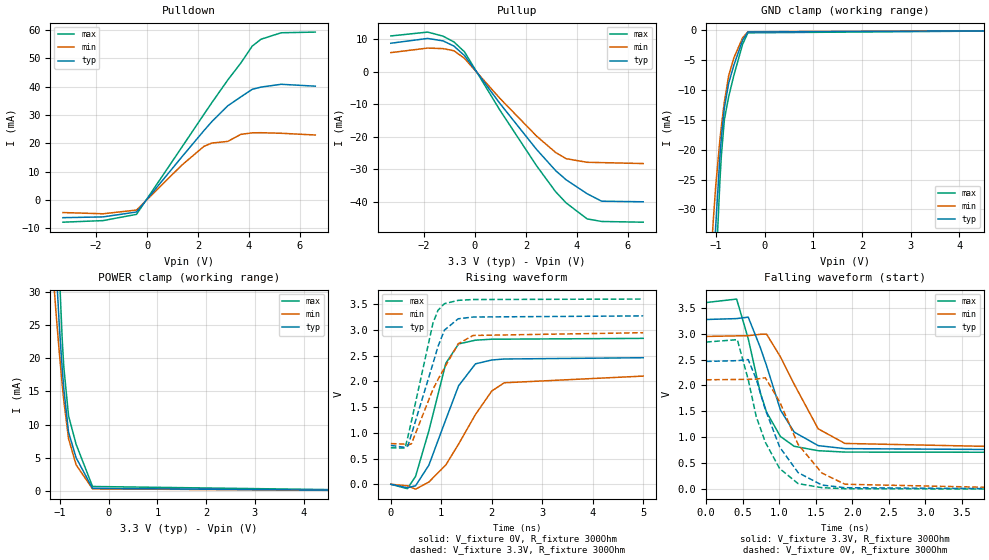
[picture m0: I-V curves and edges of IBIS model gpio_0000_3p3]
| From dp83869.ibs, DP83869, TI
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|   gpio_0000_3p3 Model
[Model]   gpio_0000_3p3
Model_type   I/O
Polarity   Non-Inverting
Enable   Active-Low
Vinl = 0.7
Vinh = 1.7
Vmeas = 1.65
Vref = 0
Cref = 2pF
Rref = 100000
|   typ   min   max
C_comp   1.10585pF   1.10585pF   1.45739pF
| Where Nom  PVT is Nominal Process, 3.3V,  27C
|   Fast PVT is Strong Process,  3.63V, -40C
|   Slow PVT is Weak Process,   2.97V, 125C
[Voltage Range]   3.3   2.97   3.63
|Junction Temperature
[Temperature Range]   27   125   -40
[Pullup Reference]   3.3   2.97   3.63
[Pulldown Reference]   -0   0   0
[Power Clamp Reference]   3.3   2.97   3.63
[GND Clamp Reference]   0   0   0
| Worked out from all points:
|   slope of the pulldown table from 0 to 0.495 V, typ, clamps not added: 89 ohm
|   slope of the pullup table from 0 to 0.495 V, typ, clamps not added: 96.1 ohm
|   GND clamp passes 1 mA (typ) near -0.41 V on its own axis
|   POWER clamp passes 1 mA (typ) near -0.41 V on its own axis
|   falling waveform, V_fixture 3.3V, R_fixture 300Ohm: 20-80 % time 387ps typ, 469ps min, 336ps max; typ from 3.27 V to 0.756 V
|   rising waveform, V_fixture 0V, R_fixture 300Ohm: 20-80 % time 561ps typ, 765ps min, 432ps max; typ from 0 V to 2.46 V
|   rising waveform, V_fixture 3.3V, R_fixture 300Ohm: 20-80 % time 472ps typ, 627ps min, 384ps max; typ from 0.756 V to 3.27 V
|   falling waveform, V_fixture 0V, R_fixture 300Ohm: 20-80 % time 433ps typ, 496ps min, 379ps max; typ from 2.46 V to 0 V
[Pulldown]
|   Voltage   I(typ)   I(min)   I(max)
-3.3V     -6.236mA   -4.426mA   -7.829mA
-1.725V   -5.961mA   -4.859mA   -7.268mA
-412.8mV  -4.231mA   -3.537mA   -5.065mA
1.355V    15.09mA    12.23mA    18.5mA
2.234V    24.51mA    18.95mA    30.27mA
2.543V    27.67mA    20.1mA     34.35mA
3.165V    33.24mA    20.68mA    42.33mA
3.677V    36.38mA    23.16mA    48.31mA
4.128V    39.07mA    23.71mA    54.33mA
4.472V    39.85mA    23.75mA    56.75mA
5.262V    40.84mA    23.55mA    59.02mA
6.6V      40.17mA    22.94mA    59.26mA
[GND Clamp]
|   Voltage   I(typ)   I(min)   I(max)
-3.3V     -489.2mA   -422.2mA   -556.8mA
-1.128V   -53.94mA   -41.75mA   -66.49mA
-1.053V   -40.94mA   -31.89mA   -50.85mA
-1.004V   -32.91mA   -26.23mA   -40.88mA
-914.8mV  -20.88mA   -18.15mA   -24.96mA
-886mV    -17.91mA   -16.01mA   -20.9mA
-824.7mV  -12.98mA   -11.96mA   -14.96mA
-737.5mV  -8.884mA   -7.637mA   -11.14mA
-632.6mV  -5.898mA   -4.664mA   -7.616mA
-450.4mV  -1.653mA   -1.242mA   -2.33mA
-341.5mV  -279.4uA   -241.7uA   -417.8uA
6.6V      0A         0A         0A
[Pullup]
|   Voltage   I(typ)   I(min)   I(max)
-3.3V     8.744mA    5.857mA    10.98mA
-1.854V   10.22mA    7.259mA    12.17mA
-1.25V    9.464mA    7.09mA     10.92mA
-823.7mV  7.868mA    6.443mA    9.137mA
-409.9mV  4.958mA    4.085mA    6.1mA
964.1mV   -9.615mA   -8.073mA   -11.64mA
2.415V    -23.87mA   -19.78mA   -28.89mA
3.165V    -30.4mA    -24.82mA   -36.9mA
3.575V    -33.21mA   -26.73mA   -40.31mA
4.399V    -37.5mA    -27.84mA   -45.23mA
4.969V    -39.8mA    -27.94mA   -46.03mA
6.6V      -39.98mA   -28.23mA   -46.25mA
[POWER Clamp]
|   Voltage   I(typ)   I(min)   I(max)
-3.3V     592.7mA    473.7mA    711.1mA
-1.183V   53.33mA    37.6mA     74.54mA
-1.164V   49.45mA    35.35mA    69.48mA
-1.121V   40.99mA    30.62mA    58.01mA
-1.071V   32.56mA    25.84mA    45.66mA
-1.013V   24.62mA    20.7mA     32.69mA
-952.4mV  18.17mA    15.83mA    22.43mA
-922.7mV  15.44mA    13.63mA    18.69mA
-824.7mV  8.834mA    7.855mA    11.3mA
-669.2mV  4.995mA    3.928mA    7.01mA
-332.6mV  387.6uA    312.9uA    668.4uA
6.6V      0A         0A         0A
[Ramp]
R_load = 300
|   typ   min   max
dV/dt_r   1.47587/5.59928e-10   1.26169/7.6486e-10   1.70107/4.31106e-10
dV/dt_f   1.51015/3.8335e-10   1.29271/4.6825e-10   1.7339/3.3383e-10
[Falling Waveform]
V_fixture = 3.3V
V_fixture_min = 2.97V
V_fixture_max = 3.63V
R_fixture = 300Ohm
C_fixture = 0F
|   Time   V(typ)   V(min)   V(max)
0s        3.273V     2.946V     3.6V
417.7ps   3.29V      2.957V     3.667V
576.4ps   3.318V     2.961V     2.903V
741.3ps   2.735V     2.987V     1.862V
826.7ps   2.384V     2.992V     1.488V
1.017ns   1.529V     2.553V     1.017V
1.205ns   1.102V     2.026V     827.7mV
1.534ns   840.5mV    1.164V     742.2mV
1.9ns     782.2mV    882.4mV    715.8mV
5ns       756.4mV    791.5mV    710.3mV
[Rising Waveform]
V_fixture = 0V
V_fixture_min = 0V
V_fixture_max = 0V
R_fixture = 300Ohm
C_fixture = 0F
|   Time   V(typ)   V(min)   V(max)
0s        421.1uV    616uV      448.6uV
327.3ps   -67.8mV    -29.49mV   -84.95mV
490.5ps   -28.46mV   -94.61mV   154.6mV
753.1ps   370.2mV    43.34mV    1.037V
1.09ns    1.259V     376.4mV    2.353V
1.343ns   1.915V     782.4mV    2.728V
1.677ns   2.341V     1.357V     2.801V
2ns       2.416V     1.813V     2.82V
2.247ns   2.435V     1.973V     2.821V
5ns       2.46V      2.103V     2.836V
[Rising Waveform]
V_fixture = 3.3V
V_fixture_min = 2.97V
V_fixture_max = 3.63V
R_fixture = 300Ohm
C_fixture = 0F
|   Time   V(typ)   V(min)   V(max)
0s        756.4mV    791.5mV    710.4mV
282.6ps   716.5mV    781.2mV    703.7mV
338.9ps   747mV      762.8mV    925.9mV
407.5ps   967.6mV    787.5mV    1.221V
835.6ps   2.349V     1.847V     3.135V
935ps     2.679V     2.038V     3.382V
1.062ns   2.997V     2.261V     3.511V
1.336ns   3.217V     2.733V     3.575V
1.631ns   3.251V     2.893V     3.591V
5ns       3.273V     2.946V     3.6V
[Falling Waveform]
|Gnd
V_fixture = 0V
V_fixture_min = 0V
V_fixture_max = 0V
R_fixture = 300Ohm
C_fixture = 0F
|   Time   V(typ)   V(min)   V(max)
0s        2.464V     2.11V      2.838V
427.1ps   2.479V     2.116V     2.884V
576.4ps   2.499V     2.119V     2.113V
686.5ps   2.121V     2.122V     1.398V
810.7ps   1.534V     2.149V     904.9mV
1.007ns   812.3mV    1.686V     396.9mV
1.259ns   319.9mV    863.4mV    107.5mV
1.585ns   79.39mV    311.3mV    29.05mV
1.9ns     29.09mV    95.39mV    9.109mV
5ns       413.8uV    593.3uV    443.7uV
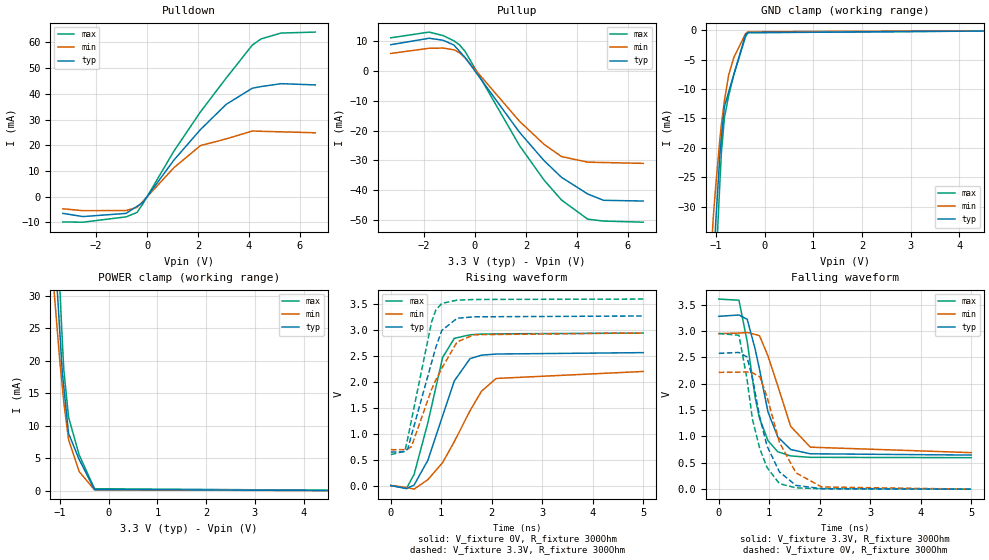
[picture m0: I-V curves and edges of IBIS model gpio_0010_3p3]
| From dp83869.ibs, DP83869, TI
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|   gpio_0010_3p3 Model
[Model]   gpio_0010_3p3
Model_type   I/O
Polarity   Non-Inverting
Enable   Active-Low
Vinl = 0.7
Vinh = 1.7
Vmeas = 1.65
Vref = 0
Cref = 2pF
Rref = 100000
|   typ   min   max
C_comp   1.10585pF   1.10585pF   1.45739pF
| Where Nom  PVT is Nominal Process, 3.3V,  27C
|   Fast PVT is Strong Process,  3.63V, -40C
|   Slow PVT is Weak Process,   2.97V, 125C
[Voltage Range]   3.3   2.97   3.63
|Junction Temperature
[Temperature Range]   27   125   -40
[Pullup Reference]   3.3   2.97   3.63
[Pulldown Reference]   -0   0   0
[Power Clamp Reference]   3.3   2.97   3.63
[GND Clamp Reference]   0   0   0
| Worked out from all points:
|   slope of the pulldown table from 0 to 0.495 V, typ, clamps not added: 72.8 ohm
|   slope of the pullup table from 0 to 0.495 V, typ, clamps not added: 80 ohm
|   GND clamp passes 1 mA (typ) near -0.40 V on its own axis
|   POWER clamp passes 1 mA (typ) near -0.40 V on its own axis
|   falling waveform, V_fixture 3.3V, R_fixture 300Ohm: 20-80 % time 378ps typ, 467ps min, 325ps max; typ from 3.28 V to 0.647 V
|   rising waveform, V_fixture 0V, R_fixture 300Ohm: 20-80 % time 528ps typ, 733ps min, 405ps max; typ from 0 V to 2.57 V
|   rising waveform, V_fixture 3.3V, R_fixture 300Ohm: 20-80 % time 457ps typ, 592ps min, 376ps max; typ from 0.647 V to 3.28 V
|   falling waveform, V_fixture 0V, R_fixture 300Ohm: 20-80 % time 415ps typ, 482ps min, 359ps max; typ from 2.58 V to 0 V
[Pulldown]
|   Voltage   I(typ)   I(min)   I(max)
-3.3V     -6.521mA   -4.727mA   -9.846mA
-2.514V   -7.764mA   -5.465mA   -9.95mA
-824.5mV  -6.534mA   -5.422mA   -7.883mA
-389.1mV  -3.762mA   -4.158mA   -6.132mA
-171.1mV  -2.374mA   -1.938mA   -2.919mA
1.048V    14.14mA    11.2mA     17.6mA
2.094V    26.08mA    19.85mA    32.95mA
3.103V    35.88mA    22.45mA    46.1mA
4.127V    42.17mA    25.52mA    58.93mA
4.47V     42.82mA    25.42mA    61.36mA
5.259V    43.95mA    25.21mA    63.65mA
6.6V      43.46mA    24.85mA    64.02mA
[GND Clamp]
|   Voltage   I(typ)   I(min)   I(max)
-3.3V     -489.2mA   -422.2mA   -556.8mA
-1.127V   -53.91mA   -42.17mA   -66.65mA
-1.052V   -41.16mA   -31.77mA   -50.65mA
-1.004V   -32.89mA   -26.64mA   -41.18mA
-914.6mV  -20.86mA   -18.27mA   -25.36mA
-885.1mV  -18.27mA   -15.94mA   -20.77mA
-823.7mV  -12.95mA   -11.9mA    -14.89mA
-736.6mV  -10.49mA   -7.6mA     -11.1mA
-630.6mV  -7.511mA   -4.619mA   -7.552mA
-388.9mV  -705.5uA   -547.6uA   -1.053mA
-340.6mV  -377.1uA   -237.3uA   -408.4uA
6.6V      0A         0A         0A
[Pullup]
|   Voltage   I(typ)   I(min)   I(max)
-3.3V     8.874mA    5.934mA    11.2mA
-1.797V   11.05mA    7.684mA    13.12mA
-1.247V   10.38mA    7.746mA    11.94mA
-824.5mV  8.757mA    7.18mA     10.17mA
-606.9mV  6.685mA    6.209mA    8.846mA
-384.1mV  4.565mA    4.415mA    6.605mA
1.745V    -20.54mA   -16.83mA   -25mA
2.706V    -30.05mA   -24.59mA   -36.59mA
3.392V    -35.69mA   -28.72mA   -43.31mA
4.426V    -41.33mA   -30.61mA   -49.79mA
5.048V    -43.43mA   -30.73mA   -50.41mA
6.6V      -43.68mA   -31.02mA   -50.79mA
[POWER Clamp]
|   Voltage   I(typ)   I(min)   I(max)
-3.3V     592.7mA    473.7mA    711.1mA
-1.183V   53.3mA     37.94mA    74.62mA
-1.164V   49.83mA    35.35mA    69.48mA
-1.12V    41.55mA    30.52mA    57.76mA
-1.071V   32.54mA    26.06mA    46.36mA
-1.012V   25.37mA    20.62mA    32.49mA
-952.2mV  18.16mA    15.89mA    22.87mA
-921.7mV  15.93mA    13.56mA    18.58mA
-824.5mV  8.828mA    7.861mA    11.32mA
-606.9mV  4.83mA     2.976mA    5.521mA
-292mV    218.8uA    166.6uA    335.6uA
6.6V      0A         0A         0A
[Ramp]
R_load = 300
|   typ   min   max
dV/dt_r   1.54101/5.25646e-10   1.32257/7.26399e-10   1.76778/4.03288e-10
dV/dt_f   1.57819/3.74737e-10   1.35354/4.64101e-10   1.80417/3.2253e-10
[Falling Waveform]
V_fixture = 3.3V
V_fixture_min = 2.97V
V_fixture_max = 3.63V
R_fixture = 300Ohm
C_fixture = 0F
|   Time   V(typ)   V(min)   V(max)
0s        3.277V     2.949V     3.604V
400.8ps   3.302V     2.959V     3.582V
564.6ps   3.22V      2.97V      2.794V
720.9ps   2.658V     2.932V     1.74V
807ps     2.277V     2.911V     1.349V
974.9ps   1.466V     2.527V     920.8mV
1.169ns   991.4mV    1.96V      709.5mV
1.425ns   752mV      1.192V     630.5mV
1.814ns   671.2mV    796.3mV    603.5mV
5ns       646.6mV    693mV      597.5mV
[Rising Waveform]
V_fixture = 0V
V_fixture_min = 0V
V_fixture_max = 0V
R_fixture = 300Ohm
C_fixture = 0F
|   Time   V(typ)   V(min)   V(max)
0s        348.1uV    514.3uV    366.4uV
312.1ps   -58.85mV   -36.07mV   -49.13mV
460.2ps   9.083mV    -69.34mV   212.6mV
734.1ps   489.2mV    114.5mV    1.214V
1.027ns   1.352V     445.4mV    2.478V
1.258ns   2.022V     849.3mV    2.845V
1.569ns   2.453V     1.447V     2.913V
1.797ns   2.52V      1.824V     2.928V
2.087ns   2.542V     2.07V      2.932V
5ns       2.569V     2.205V     2.947V
[Rising Waveform]
V_fixture = 3.3V
V_fixture_min = 2.97V
V_fixture_max = 3.63V
R_fixture = 300Ohm
C_fixture = 0F
|   Time   V(typ)   V(min)   V(max)
0s        646.6mV    693mV      597.5mV
279.5ps   654.2mV    694.9mV    667.7mV
337.6ps   712.1mV    705.2mV    924mV
409.4ps   973.5mV    754.6mV    1.269V
807ps     2.376V     1.857V     3.16V
892.2ps   2.671V     2.042V     3.392V
1.011ns   2.999V     2.267V     3.521V
1.313ns   3.233V     2.777V     3.583V
1.653ns   3.261V     2.915V     3.596V
5ns       3.277V     2.949V     3.604V
[Falling Waveform]
|Gnd
V_fixture = 0V
V_fixture_min = 0V
V_fixture_max = 0V
R_fixture = 300Ohm
C_fixture = 0F
|   Time   V(typ)   V(min)   V(max)
0s        2.575V     2.214V     2.951V
400.8ps   2.592V     2.219V     2.918V
559.1ps   2.507V     2.222V     2.094V
667.9ps   2.106V     2.206V     1.327V
814ps     1.358V     2.132V     764.1mV
956.5ps   819.6mV    1.752V     412.8mV
1.202ns   328mV      888.8mV    104.6mV
1.529ns   71.8mV     310.4mV    25.68mV
2.039ns   10.42mV    42.06mV    7.45mV
5ns       340.4uV    492uV      361.4uV
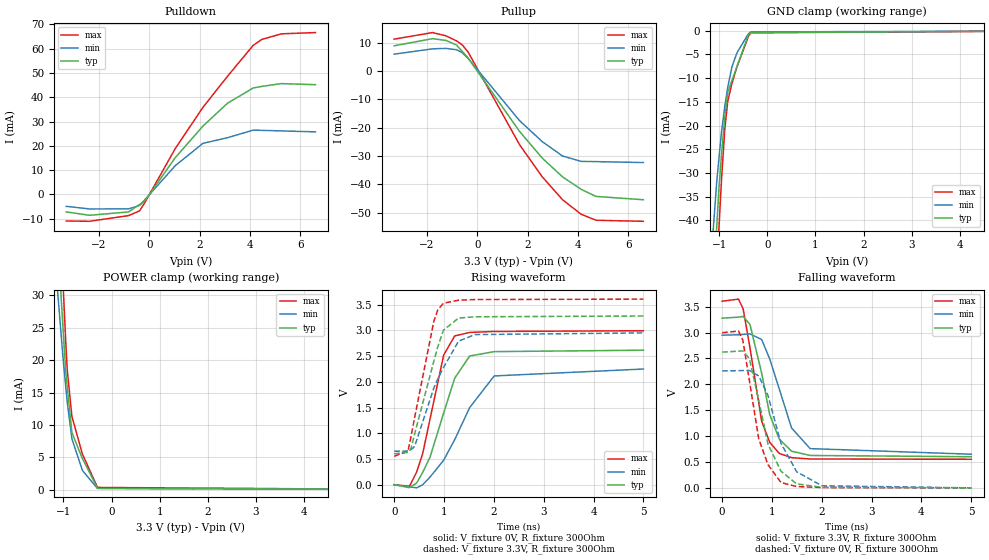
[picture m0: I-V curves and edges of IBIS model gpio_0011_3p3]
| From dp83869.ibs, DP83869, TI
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|   gpio_0011_3p3 Model
[Model]   gpio_0011_3p3
Model_type   I/O
Polarity   Non-Inverting
Enable   Active-Low
Vinl = 0.7
Vinh = 1.7
Vmeas = 1.65
Vref = 0
Cref = 2pF
Rref = 100000
|   typ   min   max
C_comp   1.10585pF   1.10585pF   1.45739pF
| Where Nom  PVT is Nominal Process, 3.3V,  27C
|   Fast PVT is Strong Process,  3.63V, -40C
|   Slow PVT is Weak Process,   2.97V, 125C
[Voltage Range]   3.3   2.97   3.63
|Junction Temperature
[Temperature Range]   27   125   -40
[Pullup Reference]   3.3   2.97   3.63
[Pulldown Reference]   -0   0   -0
[Power Clamp Reference]   3.3   2.97   3.63
[GND Clamp Reference]   0   0   0
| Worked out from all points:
|   slope of the pulldown table from 0 to 0.495 V, typ, clamps not added: 66.6 ohm
|   slope of the pullup table from 0 to 0.495 V, typ, clamps not added: 73.9 ohm
|   GND clamp passes 1 mA (typ) near -0.40 V on its own axis
|   POWER clamp passes 1 mA (typ) near -0.40 V on its own axis
|   falling waveform, V_fixture 3.3V, R_fixture 300Ohm: 20-80 % time 373ps typ, 463ps min, 319ps max; typ from 3.28 V to 0.601 V
|   rising waveform, V_fixture 0V, R_fixture 300Ohm: 20-80 % time 508ps typ, 710ps min, 390ps max; typ from 0 V to 2.61 V
|   rising waveform, V_fixture 3.3V, R_fixture 300Ohm: 20-80 % time 448ps typ, 572ps min, 372ps max; typ from 0.601 V to 3.28 V
|   falling waveform, V_fixture 0V, R_fixture 300Ohm: 20-80 % time 410ps typ, 479ps min, 355ps max; typ from 2.62 V to 0 V
[Pulldown]
|   Voltage   I(typ)   I(min)   I(max)
-3.3V     -7.18mA    -4.887mA   -10.92mA
-2.379V   -8.576mA   -5.963mA   -11.05mA
-824.4mV  -7.193mA   -5.936mA   -8.711mA
-389.1mV  -4.131mA   -4.541mA   -6.752mA
-171mV    -2.598mA   -2.109mA   -3.203mA
1.028V    15.14mA    11.85mA    18.85mA
2.13V     28.14mA    21.05mA    35.88mA
3.103V    37.54mA    23.36mA    48.61mA
4.127V    43.83mA    26.48mA    61.4mA
4.469V    44.49mA    26.39mA    63.83mA
5.25V     45.64mA    26.16mA    66.13mA
6.6V      45.2mA     25.77mA    66.65mA
[GND Clamp]
|   Voltage   I(typ)   I(min)   I(max)
-3.3V     -489.2mA   -422.2mA   -556.8mA
-1.127V   -53.89mA   -42.15mA   -66.62mA
-1.052V   -41.16mA   -31.77mA   -50.65mA
-1.004V   -32.87mA   -26.63mA   -41.16mA
-952.4mV  -25.95mA   -21.26mA   -31.23mA
-885.1mV  -18.27mA   -15.94mA   -20.77mA
-823.7mV  -12.94mA   -11.9mA    -14.89mA
-736.6mV  -10.49mA   -7.6mA     -11.1mA
-630.6mV  -7.509mA   -4.619mA   -7.552mA
-388.8mV  -704.2uA   -546.7uA   -1.051mA
-340.6mV  -377.1uA   -237.3uA   -408.4uA
6.6V      0A         0A         0A
[Pullup]
|   Voltage   I(typ)   I(min)   I(max)
-3.3V     8.925mA    5.966mA    11.28mA
-1.778V   11.44mA    7.841mA    13.6mA
-1.246V   10.83mA    8.016mA    12.45mA
-824.4mV  9.199mA    7.534mA    10.68mA
-606.9mV  7.041mA    6.549mA    9.327mA
-374.2mV  4.734mA    4.591mA    6.874mA
1.686V    -21.41mA   -17.59mA   -26.11mA
2.581V    -30.76mA   -24.94mA   -37.37mA
3.391V    -37.42mA   -30.05mA   -45.51mA
4.126V    -41.8mA    -31.92mA   -50.61mA
4.717V    -44.32mA   -32.02mA   -52.74mA
6.6V      -45.49mA   -32.34mA   -53.11mA
[POWER Clamp]
|   Voltage   I(typ)   I(min)   I(max)
-3.3V     592.7mA    473.7mA    711.1mA
-1.183V   53.27mA    37.92mA    74.59mA
-1.164V   49.83mA    35.35mA    69.48mA
-1.12V    41.55mA    30.52mA    57.76mA
-1.071V   32.52mA    26.04mA    46.34mA
-1.012V   25.37mA    20.62mA    32.49mA
-952.1mV  18.15mA    15.88mA    22.85mA
-921.7mV  15.93mA    13.56mA    18.58mA
-824.4mV  8.823mA    7.854mA    11.32mA
-606.9mV  4.829mA    2.976mA    5.521mA
-292mV    218.8uA    166.6uA    335.6uA
6.6V      0A         0A         0A
[Ramp]
R_load = 300
|   typ   min   max
dV/dt_r   1.56808/5.06648e-10   1.34839/7.05187e-10   1.79506/3.88498e-10
dV/dt_f   1.60625/3.70579e-10   1.38004/4.61239e-10   1.83227/3.18702e-10
[Falling Waveform]
V_fixture = 3.3V
V_fixture_min = 2.97V
V_fixture_max = 3.63V
R_fixture = 300Ohm
C_fixture = 0F
|   Time   V(typ)   V(min)   V(max)
0s        3.278V     2.95V      3.606V
328.7ps   3.298V     2.957V     3.646V
422ps     3.312V     2.964V     3.459V
558.9ps   3.158V     2.975V     2.706V
793.7ps   2.214V     2.865V     1.287V
955.3ps   1.414V     2.491V     879.3mV
1.148ns   942.9mV    1.907V     664.6mV
1.394ns   708.1mV    1.156V     583.4mV
1.766ns   626.2mV    758.4mV    558.4mV
5ns       601.3mV    650.1mV    552.5mV
[Rising Waveform]
V_fixture = 0V
V_fixture_min = 0V
V_fixture_max = 0V
R_fixture = 300Ohm
C_fixture = 0F
|   Time   V(typ)   V(min)   V(max)
0s        318.5uV    472.9uV    333.2uV
306.1ps   -55.62mV   -39.34mV   -29.8mV
450.5ps   34.04mV    -60.53mV   246.1mV
569.9ps   236.7mV    -1.795mV   596.7mV
717.3ps   531.6mV    147.4mV    1.269V
992.3ps   1.393V     476.2mV    2.518V
1.214ns   2.071V     876.8mV    2.891V
1.515ns   2.501V     1.5V       2.959V
2.007ns   2.586V     2.114V     2.978V
5ns       2.614V     2.248V     2.992V
[Rising Waveform]
V_fixture = 3.3V
V_fixture_min = 2.97V
V_fixture_max = 3.63V
R_fixture = 300Ohm
C_fixture = 0F
|   Time   V(typ)   V(min)   V(max)
0s        601.3mV    650.1mV    552.5mV
276.4ps   628.7mV    655.4mV    653.9mV
336.1ps   701.2mV    679.2mV    931.5mV
410.1ps   987.4mV    743.8mV    1.307V
793.7ps   2.395V     1.875V     3.17V
874.9ps   2.681V     2.055V     3.399V
988.8ps   3.004V     2.278V     3.526V
1.292ns   3.238V     2.79V      3.585V
1.619ns   3.263V     2.917V     3.598V
5ns       3.278V     2.95V      3.606V
[Falling Waveform]
|Gnd
V_fixture = 0V
V_fixture_min = 0V
V_fixture_max = 0V
R_fixture = 300Ohm
C_fixture = 0F
|   Time   V(typ)   V(min)   V(max)
0s        2.622V     2.259V     2.997V
328.7ps   2.641V     2.264V     3.03V
416.9ps   2.645V     2.266V     2.849V
546.8ps   2.496V     2.268V     2.077V
734.7ps   1.692V     2.163V     945.5mV
920.3ps   844.9mV    1.786V     448.9mV
1.181ns   322.2mV    862.2mV    102.4mV
1.496ns   77.46mV    311.2mV    25.33mV
2.003ns   9.833mV    40.67mV    6.968mV
5ns       310.6uV    449.8uV    328.1uV
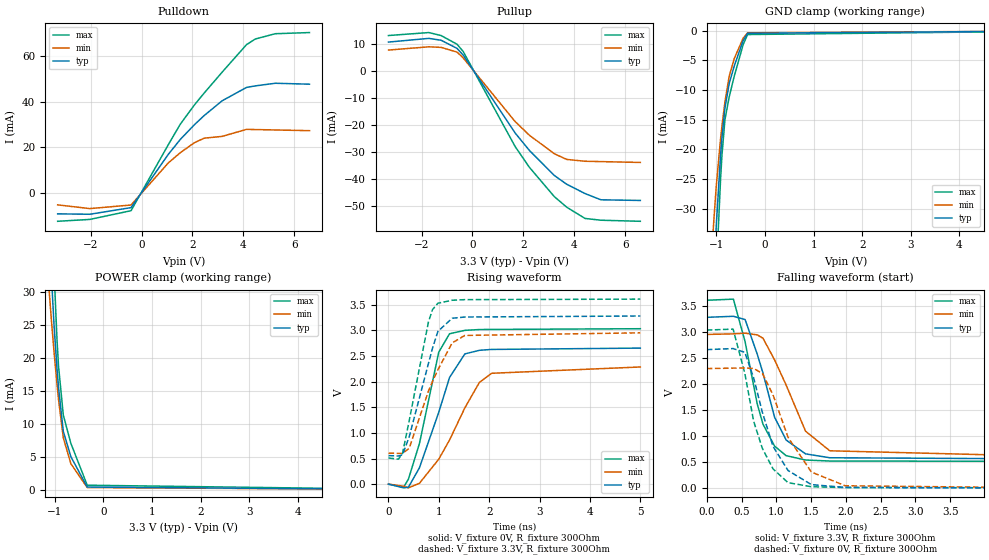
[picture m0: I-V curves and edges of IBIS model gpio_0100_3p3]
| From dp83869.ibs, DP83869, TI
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|   gpio_0100_3p3 Model
[Model]   gpio_0100_3p3
Model_type   I/O
Polarity   Non-Inverting
Enable   Active-Low
Vinl = 0.7
Vinh = 1.7
Vmeas = 1.65
Vref = 0
Cref = 2pF
Rref = 100000
|   typ   min   max
C_comp   1.10585pF   1.10585pF   1.45739pF
| Where Nom  PVT is Nominal Process, 3.3V,  27C
|   Fast PVT is Strong Process,  3.63V, -40C
|   Slow PVT is Weak Process,   2.97V, 125C
[Voltage Range]   3.3   2.97   3.63
|Junction Temperature
[Temperature Range]   27   125   -40
[Pullup Reference]   3.3   2.97   3.63
[Pulldown Reference]   -0   0   0
[Power Clamp Reference]   3.3   2.97   3.63
[GND Clamp Reference]   0   0   0
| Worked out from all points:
|   slope of the pulldown table from 0 to 0.495 V, typ, clamps not added: 60.8 ohm
|   slope of the pullup table from 0 to 0.495 V, typ, clamps not added: 68.5 ohm
|   GND clamp passes 1 mA (typ) near -0.41 V on its own axis
|   POWER clamp passes 1 mA (typ) near -0.41 V on its own axis
|   falling waveform, V_fixture 3.3V, R_fixture 300Ohm: 20-80 % time 371ps typ, 461ps min, 317ps max; typ from 3.28 V to 0.557 V
|   rising waveform, V_fixture 0V, R_fixture 300Ohm: 20-80 % time 514ps typ, 722ps min, 391ps max; typ from 0 V to 2.65 V
|   rising waveform, V_fixture 3.3V, R_fixture 300Ohm: 20-80 % time 444ps typ, 573ps min, 365ps max; typ from 0.557 V to 3.28 V
|   falling waveform, V_fixture 0V, R_fixture 300Ohm: 20-80 % time 388ps typ, 456ps min, 337ps max; typ from 2.66 V to 0 V
[Pulldown]
|   Voltage   I(typ)   I(min)   I(max)
-3.3V     -9.059mA   -5.134mA   -12.32mA
-2.036V   -9.245mA   -6.77mA    -11.5mA
-414.8mV  -6.337mA   -5.195mA   -7.682mA
1.049V    16.94mA    13.2mA     21.16mA
1.52V     23.46mA    17.67mA    30.11mA
2.067V    29.8mA     21.98mA    38.42mA
2.457V    33.88mA    24.02mA    43.71mA
3.166V    40.37mA    24.8mA     52.89mA
4.125V    46.21mA    27.87mA    64.92mA
4.47V     46.88mA    27.79mA    67.38mA
5.256V    48.03mA    27.61mA    69.69mA
6.6V      47.62mA    27.3mA     70.19mA
[GND Clamp]
|   Voltage   I(typ)   I(min)   I(max)
-3.3V     -489.2mA   -422.2mA   -556.8mA
-1.128V   -53.94mA   -41.75mA   -66.49mA
-1.053V   -40.94mA   -31.89mA   -50.85mA
-1.004V   -32.91mA   -26.23mA   -40.88mA
-914.8mV  -20.88mA   -18.15mA   -24.96mA
-886mV    -17.91mA   -16.01mA   -20.9mA
-824.7mV  -12.98mA   -11.96mA   -14.96mA
-737.5mV  -8.884mA   -7.637mA   -11.14mA
-632.6mV  -5.898mA   -4.664mA   -7.616mA
-450.4mV  -1.653mA   -1.242mA   -2.33mA
-360.4mV  -415.6uA   -340.7uA   -627.7uA
6.6V      0A         0A         0A
[Pullup]
|   Voltage   I(typ)   I(min)   I(max)
-3.3V     10.59mA    7.648mA    13.01mA
-1.714V   11.96mA    8.846mA    14.1mA
-1.23V    11.26mA    8.629mA    12.99mA
-605.9mV  8.275mA    6.896mA    9.799mA
-364.3mV  5.809mA    4.762mA    7.128mA
1.676V    -22.91mA   -18.71mA   -27.9mA
2.234V    -29.32mA   -23.73mA   -35.55mA
3.219V    -38.63mA   -30.61mA   -46.42mA
3.709V    -41.87mA   -32.7mA    -50.34mA
4.427V    -45.29mA   -33.37mA   -54.47mA
5.051V    -47.59mA   -33.5mA    -55.12mA
6.6V      -47.83mA   -33.81mA   -55.52mA
[POWER Clamp]
|   Voltage   I(typ)   I(min)   I(max)
-3.3V     592.7mA    473.7mA    711.1mA
-1.183V   53.33mA    37.6mA     74.54mA
-1.164V   49.45mA    35.35mA    69.48mA
-1.121V   40.99mA    30.62mA    58.01mA
-1.071V   32.56mA    25.84mA    45.66mA
-1.013V   24.62mA    20.7mA     32.69mA
-952.4mV  18.17mA    15.83mA    22.43mA
-922.7mV  15.44mA    13.63mA    18.69mA
-824.7mV  8.834mA    7.855mA    11.3mA
-669.2mV  4.995mA    3.928mA    7.01mA
-332.6mV  387.6uA    312.9uA    668.4uA
6.6V      0A         0A         0A
[Ramp]
R_load = 300
|   typ   min   max
dV/dt_r   1.5914/5.12844e-10   1.37067/7.19297e-10   1.81826/3.90028e-10
dV/dt_f   1.63367/3.67777e-10   1.40818/4.58476e-10   1.85849/3.13919e-10
[Falling Waveform]
V_fixture = 3.3V
V_fixture_min = 2.97V
V_fixture_max = 3.63V
R_fixture = 300Ohm
C_fixture = 0F
|   Time   V(typ)   V(min)   V(max)
0s        3.28V      2.951V     3.608V
382.9ps   3.3V       2.962V     3.63V
551.6ps   3.237V     2.975V     2.809V
726.1ps   2.571V     2.943V     1.613V
808.4ps   2.208V     2.878V     1.226V
975.8ps   1.357V     2.46V      801.9mV
1.142ns   919.1mV    1.975V     619mV
1.421ns   653.8mV    1.089V     535.6mV
1.769ns   579.3mV    713.2mV    516.3mV
5ns       556.8mV    604.1mV    510.2mV
[Rising Waveform]
V_fixture = 0V
V_fixture_min = 0V
V_fixture_max = 0V
R_fixture = 300Ohm
C_fixture = 0F
|   Time   V(typ)   V(min)   V(max)
0s        295.8uV    438.1uV    309uV
301.2ps   -72.24mV   -40.69mV   -58.78mV
395.5ps   -60.64mV   -72.02mV   98.27mV
614.2ps   319.4mV    16.84mV    791mV
997.5ps   1.4V       486.5mV    2.573V
1.212ns   2.08V      859.9mV    2.933V
1.516ns   2.54V      1.488V     2.999V
1.805ns   2.61V      1.985V     3.015V
2.047ns   2.627V     2.162V     3.017V
5ns       2.653V     2.285V     3.031V
[Rising Waveform]
V_fixture = 3.3V
V_fixture_min = 2.97V
V_fixture_max = 3.63V
R_fixture = 300Ohm
C_fixture = 0F
|   Time   V(typ)   V(min)   V(max)
0s        556.8mV    604.2mV    510.2mV
197.3ps   548.8mV    600.4mV    487.1mV
278.8ps   571.3mV    599.9mV    601.1mV
411ps     922.9mV    699.7mV    1.236V
793.1ps   2.354V     1.816V     3.164V
873.4ps   2.65V      2.002V     3.403V
981.1ps   2.979V     2.231V     3.528V
1.264ns   3.235V     2.753V     3.586V
1.515ns   3.259V     2.9V       3.598V
5ns       3.279V     2.951V     3.608V
[Falling Waveform]
|Gnd
V_fixture = 0V
V_fixture_min = 0V
V_fixture_max = 0V
R_fixture = 300Ohm
C_fixture = 0F
|   Time   V(typ)   V(min)   V(max)
0s        2.659V     2.294V     3.035V
379.4ps   2.679V     2.303V     3.053V
548.1ps   2.606V     2.306V     2.198V
675.1ps   2.111V     2.296V     1.278V
800.1ps   1.451V     2.201V     757.9mV
953ps     797.6mV    1.789V     365.4mV
1.169ns   333.3mV    971.8mV    99.82mV
1.505ns   62.42mV    303.6mV    22.15mV
1.991ns   8.615mV    40.2mV     6.118mV
5ns       289.3uV    418.7uV    304.9uV
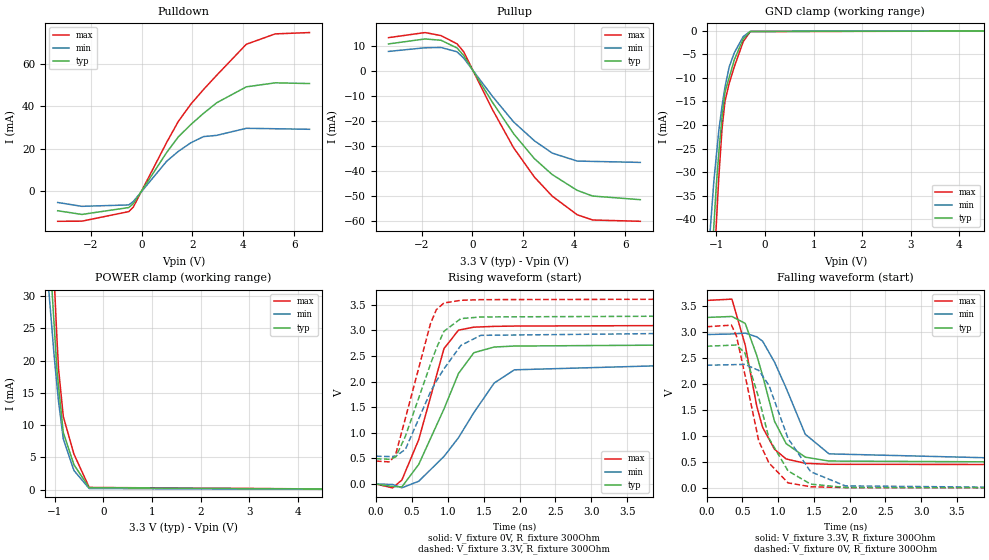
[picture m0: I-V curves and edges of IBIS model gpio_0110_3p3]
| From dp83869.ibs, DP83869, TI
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|   gpio_0110_3p3 Model
[Model]   gpio_0110_3p3
Model_type   I/O
Polarity   Non-Inverting
Enable   Active-Low
Vinl = 0.7
Vinh = 1.7
Vmeas = 1.65
Vref = 0
Cref = 2pF
Rref = 100000
|   typ   min   max
C_comp   1.10585pF   1.10585pF   1.45739pF
| Where Nom  PVT is Nominal Process, 3.3V,  27C
|   Fast PVT is Strong Process,  3.63V, -40C
|   Slow PVT is Weak Process,   2.97V, 125C
[Voltage Range]   3.3   2.97   3.63
|Junction Temperature
[Temperature Range]   27   125   -40
[Pullup Reference]   3.3   2.97   3.63
[Pulldown Reference]   -0   -0   0
[Power Clamp Reference]   3.3   2.97   3.63
[GND Clamp Reference]   0   0   0
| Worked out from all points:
|   slope of the pulldown table from 0 to 0.495 V, typ, clamps not added: 52.8 ohm
|   slope of the pullup table from 0 to 0.495 V, typ, clamps not added: 59.9 ohm
|   GND clamp passes 1 mA (typ) near -0.41 V on its own axis
|   POWER clamp passes 1 mA (typ) near -0.40 V on its own axis
|   falling waveform, V_fixture 3.3V, R_fixture 300Ohm: 20-80 % time 360ps typ, 452ps min, 307ps max; typ from 3.28 V to 0.494 V
|   rising waveform, V_fixture 0V, R_fixture 300Ohm: 20-80 % time 491ps typ, 697ps min, 372ps max; typ from 0 V to 2.72 V
|   rising waveform, V_fixture 3.3V, R_fixture 300Ohm: 20-80 % time 426ps typ, 539ps min, 355ps max; typ from 0.494 V to 3.28 V
|   falling waveform, V_fixture 0V, R_fixture 300Ohm: 20-80 % time 375ps typ, 444ps min, 325ps max; typ from 2.73 V to 0 V
[Pulldown]
|   Voltage   I(typ)   I(min)   I(max)
-3.3V     -9.344mA   -5.435mA   -14.34mA
-2.348V   -11.09mA   -7.262mA   -14.28mA
-502.9mV  -7.832mA   -6.592mA   -9.745mA
-324.7mV  -5.962mA   -4.956mA   -7.587mA
989.4mV   18.3mA     14.12mA    23.08mA
1.445V    25.62mA    18.76mA    32.94mA
1.939V    31.47mA    22.83mA    41.14mA
2.436V    36.75mA    25.74mA    48.03mA
2.947V    41.7mA     26.31mA    54.68mA
4.116V    49.27mA    29.66mA    69.41mA
5.253V    51.17mA    29.45mA    74.33mA
6.6V      50.83mA    29.19mA    74.95mA
[GND Clamp]
|   Voltage   I(typ)   I(min)   I(max)
-3.3V     -489.2mA   -422.2mA   -556.8mA
-1.128V   -53.97mA   -42.21mA   -66.72mA
-1.053V   -41.32mA   -31.89mA   -50.85mA
-1.004V   -32.94mA   -26.68mA   -41.24mA
-953.4mV  -26.08mA   -21.35mA   -31.4mA
-886mV    -18.36mA   -16.01mA   -20.9mA
-824.7mV  -12.99mA   -11.96mA   -14.96mA
-737.5mV  -9.888mA   -7.637mA   -11.14mA
-631.6mV  -6.122mA   -4.642mA   -7.584mA
-449.5mV  -1.722mA   -1.228mA   -2.306mA
-304.9mV  -132.9uA   -117.5uA   -164.8uA
6.6V      0A         0A         0A
[Pullup]
|   Voltage   I(typ)   I(min)   I(max)
-3.3V     10.72mA    7.725mA    13.23mA
-1.865V   12.71mA    9.183mA    15.26mA
-1.236V   12.19mA    9.305mA    14.05mA
-605.9mV  9.099mA    7.582mA    10.76mA
-347.5mV  6.154mA    5.099mA    7.643mA
783.8mV   -12.55mA   -10.16mA   -15.43mA
1.619V    -25.14mA   -20.43mA   -30.76mA
2.436V    -35.09mA   -27.95mA   -42.45mA
3.134V    -41.43mA   -32.85mA   -50.05mA
4.116V    -47.75mA   -36.06mA   -57.48mA
4.724V    -50.02mA   -36.19mA   -59.59mA
6.6V      -51.48mA   -36.59mA   -60.11mA
[POWER Clamp]
|   Voltage   I(typ)   I(min)   I(max)
-3.3V     592.7mA    473.7mA    711.1mA
-1.183V   53.37mA    37.99mA    74.72mA
-1.164V   49.83mA    35.35mA    69.48mA
-1.121V   41.73mA    30.62mA    58.01mA
-1.071V   32.59mA    26.09mA    46.44mA
-1.013V   25.49mA    20.7mA     32.69mA
-952.6mV  18.19mA    15.92mA    22.92mA
-922.7mV  16mA       13.63mA    18.69mA
-824.8mV  8.842mA    7.865mA    11.31mA
-605.9mV  3.85mA     2.962mA    5.498mA
-292mV    295.2uA    166.6uA    335.6uA
6.6V      0A         0A         0A
[Ramp]
R_load = 300
|   typ   min   max
dV/dt_r   1.63217/4.89432e-10   1.41066/6.95081e-10   1.8584/3.70571e-10
dV/dt_f   1.67275/3.57753e-10   1.44615/4.49008e-10   1.8969/3.04264e-10
[Falling Waveform]
V_fixture = 3.3V
V_fixture_min = 2.97V
V_fixture_max = 3.63V
R_fixture = 300Ohm
C_fixture = 0F
|   Time   V(typ)   V(min)   V(max)
0s        3.282V     2.953V     3.61V
352.4ps   3.301V     2.964V     3.635V
538ps     3.168V     2.981V     2.751V
700.7ps   2.546V     2.909V     1.569V
781.9ps   2.163V     2.825V     1.165V
948.3ps   1.283V     2.422V     743.6mV
1.111ns   852.6mV    1.922V     556.7mV
1.378ns   591.9mV    1.034V     473.1mV
1.711ns   516.3mV    654.9mV    454.2mV
5ns       493.9mV    542.7mV    448.7mV
[Rising Waveform]
V_fixture = 0V
V_fixture_min = 0V
V_fixture_max = 0V
R_fixture = 300Ohm
C_fixture = 0F
|   Time   V(typ)   V(min)   V(max)
0s        257.1uV    383.9uV    266.2uV
232.3ps   -48.13mV   -8.737mV   -74.79mV
361.4ps   -55.63mV   -73.88mV   77.64mV
595.8ps   381.8mV    53.56mV    864.9mV
948.2ps   1.466V     538.8mV    2.644V
1.15ns    2.158V     904.2mV    3.004V
1.364ns   2.564V     1.394V     3.063V
1.648ns   2.675V     1.973V     3.078V
1.929ns   2.694V     2.23V      3.084V
5ns       2.721V     2.351V     3.098V
[Rising Waveform]
V_fixture = 3.3V
V_fixture_min = 2.97V
V_fixture_max = 3.63V
R_fixture = 300Ohm
C_fixture = 0F
|   Time   V(typ)   V(min)   V(max)
0s        493.9mV    542.8mV    448.7mV
192.7ps   483.1mV    536.3mV    431.6mV
275.9ps   528.5mV    541.6mV    579.8mV
410.6ps   932.1mV    676.4mV    1.283V
760ps     2.34V      1.799V     3.13V
841.6ps   2.648V     2.009V     3.404V
946.7ps   2.981V     2.247V     3.534V
1.183ns   3.23V      2.706V     3.587V
1.46ns    3.262V     2.903V     3.6V
5ns       3.282V     2.953V     3.61V
[Falling Waveform]
|Gnd
V_fixture = 0V
V_fixture_min = 0V
V_fixture_max = 0V
R_fixture = 300Ohm
C_fixture = 0F
|   Time   V(typ)   V(min)   V(max)
0s        2.728V     2.362V     3.103V
345.3ps   2.747V     2.372V     3.134V
413.9ps   2.751V     2.374V     2.935V
533.3ps   2.602V     2.378V     2.188V
728.1ps   1.733V     2.262V     901.9mV
870.3ps   954.1mV    1.974V     480.4mV
1.137ns   327.4mV    954.5mV    96.67mV
1.454ns   72.06mV    311mV      21.03mV
1.938ns   7.767mV    38.56mV    5.827mV
5ns       250.6uV    365.1uV    261.8uV
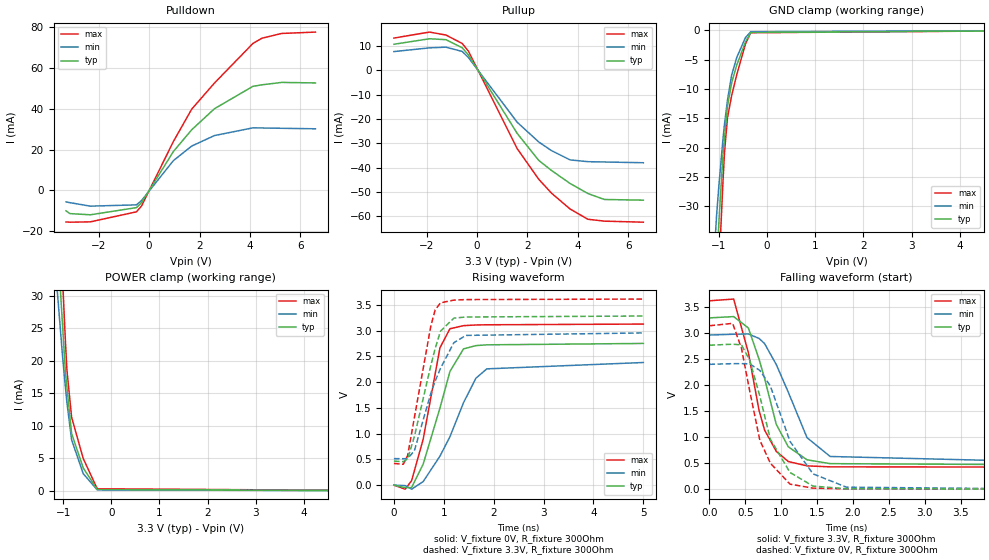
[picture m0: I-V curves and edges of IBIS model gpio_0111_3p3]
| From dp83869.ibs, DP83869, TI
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|   gpio_0111_3p3 Model
[Model]   gpio_0111_3p3
Model_type   I/O
Polarity   Non-Inverting
Enable   Active-Low
Vinl = 0.7
Vinh = 1.7
Vmeas = 1.65
Vref = 0
Cref = 2pF
Rref = 100000
|   typ   min   max
C_comp   1.10585pF   1.10585pF   1.45739pF
| Where Nom  PVT is Nominal Process, 3.3V,  27C
|   Fast PVT is Strong Process,  3.63V, -40C
|   Slow PVT is Weak Process,   2.97V, 125C
[Voltage Range]   3.3   2.97   3.63
|Junction Temperature
[Temperature Range]   27   125   -40
[Pullup Reference]   3.3   2.97   3.63
[Pulldown Reference]   -0   0   0
[Power Clamp Reference]   3.3   2.97   3.63
[GND Clamp Reference]   0   0   0
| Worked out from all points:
|   slope of the pulldown table from 0 to 0.495 V, typ, clamps not added: 50.1 ohm
|   slope of the pullup table from 0 to 0.495 V, typ, clamps not added: 57.1 ohm
|   GND clamp passes 1 mA (typ) near -0.40 V on its own axis
|   POWER clamp passes 1 mA (typ) near -0.40 V on its own axis
|   falling waveform, V_fixture 3.3V, R_fixture 300Ohm: 20-80 % time 355ps typ, 447ps min, 305ps max; typ from 3.28 V to 0.467 V
|   rising waveform, V_fixture 0V, R_fixture 300Ohm: 20-80 % time 475ps typ, 677ps min, 361ps max; typ from 0 V to 2.75 V
|   rising waveform, V_fixture 3.3V, R_fixture 300Ohm: 20-80 % time 417ps typ, 523ps min, 350ps max; typ from 0.467 V to 3.28 V
|   falling waveform, V_fixture 0V, R_fixture 300Ohm: 20-80 % time 372ps typ, 444ps min, 323ps max; typ from 2.76 V to 0 V
[Pulldown]
|   Voltage   I(typ)   I(min)   I(max)
-3.3V     -10mA      -5.595mA   -15.41mA
-3.147V   -11.32mA   -5.965mA   -15.53mA
-2.332V   -11.91mA   -7.682mA   -15.36mA
-503.9mV  -8.396mA   -7.046mA   -10.46mA
-298mV    -5.875mA   -4.883mA   -7.533mA
962.7mV   19.05mA    14.61mA    23.97mA
1.689V    29.7mA     21.72mA    39.79mA
2.593V    39.99mA    26.86mA    52.57mA
4.118V    50.95mA    30.63mA    71.91mA
4.469V    51.67mA    30.57mA    74.46mA
5.254V    52.86mA    30.42mA    76.82mA
6.6V      52.62mA    30.17mA    77.49mA
[GND Clamp]
|   Voltage   I(typ)   I(min)   I(max)
-3.3V     -489.2mA   -422.2mA   -556.8mA
-1.127V   -53.92mA   -42.17mA   -66.66mA
-1.052V   -41.16mA   -31.77mA   -50.65mA
-1.004V   -32.9mA    -26.64mA   -41.19mA
-914.6mV  -20.87mA   -18.28mA   -25.37mA
-885.1mV  -18.27mA   -15.94mA   -20.77mA
-823.7mV  -12.92mA   -11.9mA    -14.89mA
-736.6mV  -8.93mA    -7.6mA     -11.1mA
-630.6mV  -5.904mA   -4.619mA   -7.552mA
-450.4mV  -1.987mA   -1.242mA   -2.33mA
-340.6mV  -374.8uA   -237.3uA   -408.4uA
6.6V      0A         0A         0A
[Pullup]
|   Voltage   I(typ)   I(min)   I(max)
-3.3V     10.77mA    7.756mA    13.31mA
-1.886V   13.03mA    9.288mA    15.77mA
-1.234V   12.65mA    9.573mA    14.55mA
-590mV    9.339mA    7.809mA    11.1mA
-339.6mV  6.332mA    5.259mA    7.891mA
1.592V    -25.87mA   -21.28mA   -32.13mA
2.447V    -36.96mA   -29.39mA   -44.72mA
2.955V    -41.12mA   -32.97mA   -50.45mA
3.69V     -46.45mA   -36.77mA   -56.95mA
4.399V    -50.6mA    -37.5mA    -61.17mA
5.052V    -53.04mA   -37.63mA   -61.95mA
6.6V      -53.33mA   -37.94mA   -62.38mA
[POWER Clamp]
|   Voltage   I(typ)   I(min)   I(max)
-3.3V     592.7mA    473.7mA    711.1mA
-1.183V   53.3mA     37.95mA    74.64mA
-1.164V   49.83mA    35.35mA    69.48mA
-1.12V    41.55mA    30.52mA    57.76mA
-1.071V   32.55mA    26.06mA    46.37mA
-1.012V   25.37mA    20.62mA    32.49mA
-952.3mV  18.16mA    15.9mA     22.88mA
-921.7mV  15.93mA    13.56mA    18.58mA
-824.5mV  8.829mA    7.863mA    11.33mA
-583.1mV  3.532mA    2.647mA    4.979mA
-292mV    218.9uA    166.6uA    335.6uA
6.6V      0A         0A         0A
[Ramp]
R_load = 300
|   typ   min   max
dV/dt_r   1.64967/4.74037e-10   1.428/6.74729e-10   1.87551/3.59633e-10
dV/dt_f   1.68961/3.54458e-10   1.46304/4.45331e-10   1.91319/3.02199e-10
[Falling Waveform]
V_fixture = 3.3V
V_fixture_min = 2.97V
V_fixture_max = 3.63V
R_fixture = 300Ohm
C_fixture = 0F
|   Time   V(typ)   V(min)   V(max)
0s        3.283V     2.954V     3.611V
338.2ps   3.308V     2.97V      3.644V
543ps     3.09V      2.976V     2.617V
691.2ps   2.494V     2.89V      1.514V
768.6ps   2.124V     2.791V     1.134V
931.5ps   1.243V     2.389V     725.4mV
1.099ns   812.5mV    1.858V     529.5mV
1.36ns    563.1mV    987.1mV    446.6mV
1.682ns   489.2mV    626.6mV    428mV
5ns       466.7mV    515.4mV    422.6mV
[Rising Waveform]
V_fixture = 0V
V_fixture_min = 0V
V_fixture_max = 0V
R_fixture = 300Ohm
C_fixture = 0F
|   Time   V(typ)   V(min)   V(max)
0s        239uV      359.3uV    247.7uV
226.7ps   -48.67mV   -8.442mV   -77.23mV
355.2ps   -45.66mV   -77.11mV   89.12mV
585.9ps   407.5mV    69.44mV    888.8mV
923.3ps   1.498V     563.8mV    2.667V
1.123ns   2.206V     940.3mV    3.035V
1.395ns   2.644V     1.6V       3.095V
1.643ns   2.708V     2.075V     3.108V
1.862ns   2.723V     2.257V     3.112V
5ns       2.75V      2.38V      3.126V
[Rising Waveform]
V_fixture = 3.3V
V_fixture_min = 2.97V
V_fixture_max = 3.63V
R_fixture = 300Ohm
C_fixture = 0F
|   Time   V(typ)   V(min)   V(max)
0s        466.7mV    515.4mV    422.6mV
187.1ps   457.1mV    513.8mV    405.7mV
275.2ps   510.5mV    515.1mV    576.8mV
410.1ps   943.1mV    668.4mV    1.311V
740ps     2.321V     1.783V     3.09V
826.9ps   2.65V      2.02V      3.401V
934ps     2.989V     2.268V     3.538V
1.201ns   3.241V     2.764V     3.591V
1.442ns   3.263V     2.906V     3.601V
5ns       3.282V     2.954V     3.611V
[Falling Waveform]
|Gnd
V_fixture = 0V
V_fixture_min = 0V
V_fixture_max = 0V
R_fixture = 300Ohm
C_fixture = 0F
|   Time   V(typ)   V(min)   V(max)
0s        2.759V     2.393V     3.132V
324ps     2.779V     2.406V     3.178V
446.4ps   2.766V     2.406V     2.705V
559.5ps   2.481V     2.403V     1.899V
702.3ps   1.784V     2.277V     939.2mV
849.1ps   957.4mV    1.978V     498mV
1.123ns   320mV      915.7mV    95.95mV
1.442ns   59.47mV    294.2mV    20.21mV
1.91ns    7.784mV    37.92mV    5.644mV
5ns       233.1uV    341.1uV    242uV
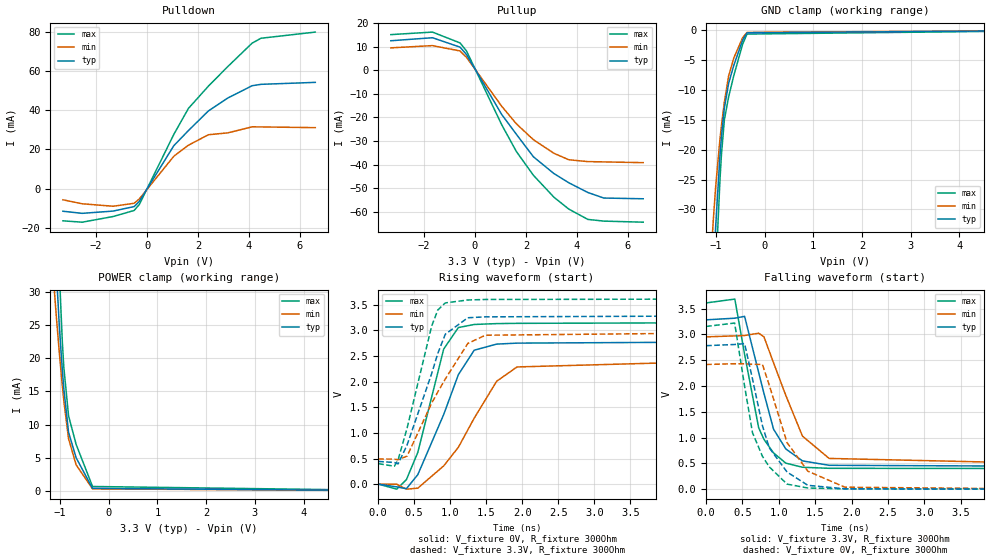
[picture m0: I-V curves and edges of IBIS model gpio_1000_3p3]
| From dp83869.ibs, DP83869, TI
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|   gpio_1000_3p3 Model
[Model]   gpio_1000_3p3
Model_type   I/O
Polarity   Non-Inverting
Enable   Active-Low
Vinl = 0.7
Vinh = 1.7
Vmeas = 1.65
Vref = 0
Cref = 2pF
Rref = 100000
|   typ   min   max
C_comp   1.10585pF   1.10585pF   1.45739pF
| Where Nom  PVT is Nominal Process, 3.3V,  27C
|   Fast PVT is Strong Process,  3.63V, -40C
|   Slow PVT is Weak Process,   2.97V, 125C
[Voltage Range]   3.3   2.97   3.63
|Junction Temperature
[Temperature Range]   27   125   -40
[Pullup Reference]   3.3   2.97   3.63
[Pulldown Reference]   0   0   0
[Power Clamp Reference]   3.3   2.97   3.63
[GND Clamp Reference]   0   0   0
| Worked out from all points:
|   slope of the pulldown table from 0 to 0.495 V, typ, clamps not added: 46.5 ohm
|   slope of the pullup table from 0 to 0.495 V, typ, clamps not added: 53.4 ohm
|   GND clamp passes 1 mA (typ) near -0.41 V on its own axis
|   POWER clamp passes 1 mA (typ) near -0.41 V on its own axis
|   falling waveform, V_fixture 3.3V, R_fixture 300Ohm: 20-80 % time 332ps typ, 423ps min, 278ps max; typ from 3.28 V to 0.443 V
|   rising waveform, V_fixture 0V, R_fixture 300Ohm: 20-80 % time 436ps typ, 608ps min, 331ps max; typ from 0 V to 2.77 V
|   rising waveform, V_fixture 3.3V, R_fixture 300Ohm: 20-80 % time 408ps typ, 562ps min, 328ps max; typ from 0.443 V to 3.28 V
|   falling waveform, V_fixture 0V, R_fixture 300Ohm: 20-80 % time 352ps typ, 420ps min, 300ps max; typ from 2.78 V to 0 V
[Pulldown]
|   Voltage   I(typ)   I(min)   I(max)
-3.3V     -11.57mA   -5.72mA    -16.47mA
-2.542V   -12.65mA   -7.768mA   -17.17mA
-1.33V    -11.49mA   -9.016mA   -14.27mA
-505.9mV  -9.192mA   -7.519mA   -11.18mA
-301.9mV  -6.55mA    -5.257mA   -8.117mA
1.051V    21.93mA    16.53mA    27.7mA
1.625V    29.66mA    22.17mA    40.99mA
2.408V    39.69mA    27.52mA    52.36mA
3.168V    46.28mA    28.48mA    62.35mA
4.122V    52.56mA    31.56mA    74.33mA
4.468V    53.27mA    31.51mA    76.82mA
6.6V      54.28mA    31.14mA    79.97mA
[GND Clamp]
|   Voltage   I(typ)   I(min)   I(max)
-3.3V     -489.2mA   -422.2mA   -556.8mA
-1.128V   -53.94mA   -41.75mA   -66.49mA
-1.053V   -40.94mA   -31.89mA   -50.85mA
-1.004V   -32.91mA   -26.23mA   -40.88mA
-914.8mV  -20.88mA   -18.15mA   -24.96mA
-886mV    -17.91mA   -16.01mA   -20.9mA
-824.7mV  -12.98mA   -11.96mA   -14.96mA
-737.5mV  -8.884mA   -7.637mA   -11.14mA
-632.6mV  -5.898mA   -4.664mA   -7.616mA
-450.4mV  -1.653mA   -1.242mA   -2.33mA
-360.4mV  -415.6uA   -340.7uA   -627.7uA
6.6V      0A         0A         0A
[Pullup]
|   Voltage   I(typ)   I(min)   I(max)
-3.3V     12.44mA    9.432mA    15.04mA
-1.668V   13.72mA    10.38mA    16.11mA
-586.1mV  9.746mA    8.126mA    11.53mA
-330.7mV  6.605mA    5.399mA    8.101mA
1.051V    -18.82mA   -15.33mA   -23.17mA
1.625V    -27.18mA   -22.75mA   -34.48mA
2.293V    -36.71mA   -29.48mA   -44.55mA
3.096V    -43.8mA    -35.22mA   -53.81mA
3.682V    -47.73mA   -37.98mA   -58.87mA
4.428V    -51.84mA   -38.75mA   -63.24mA
5.054V    -54.19mA   -38.88mA   -63.96mA
6.6V      -54.5mA    -39.2mA    -64.42mA
[POWER Clamp]
|   Voltage   I(typ)   I(min)   I(max)
-3.3V     592.7mA    473.7mA    711.1mA
-1.183V   53.33mA    37.6mA     74.54mA
-1.164V   49.45mA    35.35mA    69.48mA
-1.121V   40.99mA    30.62mA    58.01mA
-1.071V   32.56mA    25.84mA    45.66mA
-1.013V   24.62mA    20.7mA     32.69mA
-952.4mV  18.17mA    15.83mA    22.43mA
-922.7mV  15.44mA    13.63mA    18.69mA
-824.7mV  8.834mA    7.855mA    11.3mA
-669.2mV  4.995mA    3.928mA    7.01mA
-332.6mV  387.6uA    312.9uA    668.4uA
6.6V      0A         0A         0A
[Ramp]
R_load = 300
|   typ   min   max
dV/dt_r   1.66513/4.33047e-10   1.44362/6.02205e-10   1.89033/3.30322e-10
dV/dt_f   1.70456/3.30317e-10   1.47855/4.20786e-10   1.92738/2.76893e-10
[Falling Waveform]
V_fixture = 3.3V
V_fixture_min = 2.97V
V_fixture_max = 3.63V
R_fixture = 300Ohm
C_fixture = 0F
|   Time   V(typ)   V(min)   V(max)
0s        3.284V     2.954V     3.612V
395.1ps   3.316V     2.973V     3.687V
529.2ps   3.352V     2.98V      2.614V
722.8ps   2.262V     3.025V     1.191V
794.8ps   1.861V     2.956V     967.7mV
927.2ps   1.164V     2.452V     703mV
1.096ns   780.2mV    1.819V     504.4mV
1.325ns   548.7mV    1.029V     425.4mV
1.692ns   463.1mV    596.3mV    404.7mV
5ns       442.6mV    490.2mV    399.9mV
[Rising Waveform]
V_fixture = 0V
V_fixture_min = 0V
V_fixture_max = 0V
R_fixture = 300Ohm
C_fixture = 0F
|   Time   V(typ)   V(min)   V(max)
0s        227.3uV    340uV      233.3uV
257.8ps   -54.52mV   -3.012mV   -97.84mV
392.1ps   -89.02mV   -98.54mV   88.66mV
549.7ps   184.3mV    -79.1mV    618.1mV
909.4ps   1.359V     355.8mV    2.637V
1.113ns   2.137V     719.5mV    3.056V
1.333ns   2.614V     1.288V     3.116V
1.644ns   2.733V     2.007V     3.133V
1.927ns   2.752V     2.287V     3.138V
5ns       2.775V     2.406V     3.151V
[Rising Waveform]
V_fixture = 3.3V
V_fixture_min = 2.97V
V_fixture_max = 3.63V
R_fixture = 300Ohm
C_fixture = 0F
|   Time   V(typ)   V(min)   V(max)
0s        442.6mV    490.2mV    399.9mV
223.9ps   422.7mV    487.9mV    348.9mV
276.5ps   394.7mV    474.7mV    473.9mV
401.4ps   764.6mV    548mV      1.095V
741.6ps   2.155V     1.578V     3.082V
827.4ps   2.552V     1.8V       3.399V
931.8ps   2.926V     2.052V     3.537V
1.244ns   3.247V     2.746V     3.594V
1.489ns   3.265V     2.906V     3.604V
5ns       3.283V     2.954V     3.612V
[Falling Waveform]
|Gnd
V_fixture = 0V
V_fixture_min = 0V
V_fixture_max = 0V
R_fixture = 300Ohm
C_fixture = 0F
|   Time   V(typ)   V(min)   V(max)
0s        2.783V     2.418V     3.156V
392.1ps   2.806V     2.433V     3.222V
529.2ps   2.823V     2.431V     2.001V
637.8ps   2.138V     2.421V     1.095V
774ps     1.235V     2.421V     639.1mV
868.3ps   802.1mV    2.018V     432.8mV
1.113ns   332.6mV    903.4mV    98.32mV
1.399ns   74.54mV    349.1mV    22.58mV
1.909ns   7.355mV    37.99mV    5.667mV
5ns       220.6uV    324uV      229.5uV
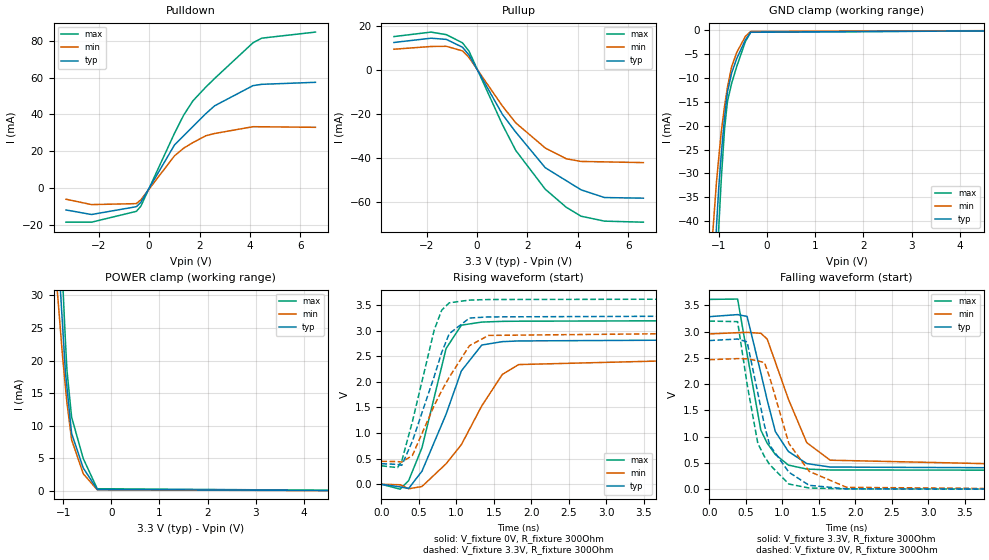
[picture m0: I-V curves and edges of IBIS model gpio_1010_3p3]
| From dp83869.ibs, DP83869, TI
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|   gpio_1010_3p3 Model
[Model]   gpio_1010_3p3
Model_type   I/O
Polarity   Non-Inverting
Enable   Active-Low
Vinl = 0.7
Vinh = 1.7
Vmeas = 1.65
Vref = 0
Cref = 2pF
Rref = 100000
|   typ   min   max
C_comp   1.10585pF   1.10585pF   1.45739pF
| Where Nom  PVT is Nominal Process, 3.3V,  27C
|   Fast PVT is Strong Process,  3.63V, -40C
|   Slow PVT is Weak Process,   2.97V, 125C
[Voltage Range]   3.3   2.97   3.63
|Junction Temperature
[Temperature Range]   27   125   -40
[Pullup Reference]   3.3   2.97   3.63
[Pulldown Reference]   -0   0   0
[Power Clamp Reference]   3.3   2.97   3.63
[GND Clamp Reference]   0   0   0
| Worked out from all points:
|   slope of the pulldown table from 0 to 0.495 V, typ, clamps not added: 42 ohm
|   slope of the pullup table from 0 to 0.495 V, typ, clamps not added: 48.4 ohm
|   GND clamp passes 1 mA (typ) near -0.40 V on its own axis
|   POWER clamp passes 1 mA (typ) near -0.40 V on its own axis
|   falling waveform, V_fixture 3.3V, R_fixture 300Ohm: 20-80 % time 316ps typ, 409ps min, 264ps max; typ from 3.29 V to 0.402 V
|   rising waveform, V_fixture 0V, R_fixture 300Ohm: 20-80 % time 420ps typ, 593ps min, 318ps max; typ from 0 V to 2.82 V
|   rising waveform, V_fixture 3.3V, R_fixture 300Ohm: 20-80 % time 394ps typ, 532ps min, 319ps max; typ from 0.402 V to 3.29 V
|   falling waveform, V_fixture 0V, R_fixture 300Ohm: 20-80 % time 332ps typ, 401ps min, 283ps max; typ from 2.83 V to 0 V
[Pulldown]
|   Voltage   I(typ)   I(min)   I(max)
-3.3V     -11.86mA   -6.022mA   -18.49mA
-2.287V   -14.32mA   -8.934mA   -18.49mA
-507.9mV  -10.07mA   -8.41mA    -12.6mA
-330.7mV  -7.73mA    -6.361mA   -9.855mA
1.008V    23.48mA    17.57mA    29.85mA
1.37V     28.42mA    21.7mA     39.64mA
1.736V    33.43mA    24.72mA    47.38mA
2.246V    40.4mA     28.43mA    54.81mA
2.598V    44.7mA     29.66mA    59.54mA
4.121V    55.66mA    33.36mA    78.92mA
4.467V    56.37mA    33.32mA    81.43mA
6.6V      57.46mA    33.03mA    84.73mA
[GND Clamp]
|   Voltage   I(typ)   I(min)   I(max)
-3.3V     -489.2mA   -422.2mA   -556.8mA
-1.127V   -53.89mA   -42.15mA   -66.62mA
-1.052V   -41.16mA   -31.77mA   -50.65mA
-1.004V   -32.87mA   -26.63mA   -41.16mA
-952.4mV  -25.95mA   -21.26mA   -31.23mA
-885.1mV  -18.27mA   -15.94mA   -20.77mA
-823.7mV  -12.92mA   -11.9mA    -14.89mA
-736.6mV  -8.929mA   -7.6mA     -11.1mA
-630.6mV  -5.904mA   -4.619mA   -7.552mA
-450.4mV  -1.988mA   -1.242mA   -2.33mA
-340.6mV  -374.8uA   -237.3uA   -408.4uA
6.6V      0A         0A         0A
[Pullup]
|   Voltage   I(typ)   I(min)   I(max)
-3.3V     12.57mA    9.508mA    15.25mA
-1.829V   14.51mA    10.75mA    17.29mA
-1.22V    13.98mA    10.84mA    16.13mA
-578.2mV  10.42mA    8.741mA    12.41mA
-320.8mV  6.893mA    5.761mA    8.655mA
1.008V    -20.11mA   -16.33mA   -24.77mA
1.537V    -28.14mA   -23.94mA   -36.48mA
2.706V    -44.3mA    -35.35mA   -54.06mA
3.54V     -50.19mA   -40.23mA   -62.27mA
4.127V    -54.34mA   -41.45mA   -66.32mA
5.058V    -57.85mA   -41.65mA   -68.56mA
6.6V      -58.13mA   -41.98mA   -69.04mA
[POWER Clamp]
|   Voltage   I(typ)   I(min)   I(max)
-3.3V     592.7mA    473.7mA    711.1mA
-1.183V   53.27mA    37.92mA    74.59mA
-1.164V   49.83mA    35.35mA    69.48mA
-1.12V    41.55mA    30.52mA    57.76mA
-1.071V   32.52mA    26.05mA    46.34mA
-1.012V   25.37mA    20.62mA    32.49mA
-952.1mV  18.15mA    15.88mA    22.85mA
-921.7mV  15.93mA    13.56mA    18.58mA
-824.4mV  8.823mA    7.854mA    11.32mA
-583.1mV  3.531mA    2.647mA    4.979mA
-292mV    218.8uA    166.6uA    335.6uA
6.6V      0A         0A         0A
[Ramp]
R_load = 300
|   typ   min   max
dV/dt_r   1.6927/4.16817e-10   1.47145/5.91021e-10   1.91685/3.15784e-10
dV/dt_f   1.73005/3.15869e-10   1.50448/4.06728e-10   1.95175/2.62841e-10
[Falling Waveform]
V_fixture = 3.3V
V_fixture_min = 2.97V
V_fixture_max = 3.63V
R_fixture = 300Ohm
C_fixture = 0F
|   Time   V(typ)   V(min)   V(max)
0s        3.285V     2.956V     3.614V
387.3ps   3.324V     2.98V      3.62V
517.1ps   3.289V     2.986V     2.578V
704.8ps   2.216V     2.969V     1.126V
792.1ps   1.699V     2.859V     876.2mV
904.2ps   1.097V     2.419V     660.9mV
1.082ns   719mV      1.717V     459mV
1.335ns   487.4mV    885.1mV    382.7mV
1.655ns   421.4mV    551.9mV    365.7mV
5ns       401.5mV    448.3mV    360.9mV
[Rising Waveform]
V_fixture = 0V
V_fixture_min = 0V
V_fixture_max = 0V
R_fixture = 300Ohm
C_fixture = 0F
|   Time   V(typ)   V(min)   V(max)
0s        202.2uV    305.7uV    207.2uV
250.5ps   -51.37mV   -8.924mV   -94.86mV
363.6ps   -80.24mV   -86.99mV   73.3mV
541.1ps   256.5mV    -42.51mV   714.4mV
862.7ps   1.367V     400.8mV    2.65V
1.067ns   2.213V     774.8mV    3.105V
1.339ns   2.717V     1.53V      3.165V
1.613ns   2.783V     2.143V     3.179V
1.831ns   2.797V     2.336V     3.182V
5ns       2.821V     2.453V     3.195V
[Rising Waveform]
V_fixture = 3.3V
V_fixture_min = 2.97V
V_fixture_max = 3.63V
R_fixture = 300Ohm
C_fixture = 0F
|   Time   V(typ)   V(min)   V(max)
0s        401.5mV    448.3mV    360.9mV
215.4ps   389.1mV    443mV      325.5mV
271.7ps   370.1mV    434.5mV    456.8mV
413.3ps   841.9mV    563.1mV    1.225V
704.8ps   2.107V     1.538V     3.013V
804.5ps   2.574V     1.826V     3.398V
905.2ps   2.939V     2.09V      3.541V
1.175ns   3.244V     2.705V     3.594V
1.43ns    3.266V     2.905V     3.605V
5ns       3.285V     2.955V     3.614V
[Falling Waveform]
|Gnd
V_fixture = 0V
V_fixture_min = 0V
V_fixture_max = 0V
R_fixture = 300Ohm
C_fixture = 0F
|   Time   V(typ)   V(min)   V(max)
0s        2.83V      2.465V     3.201V
387.3ps   2.859V     2.486V     3.19V
517.1ps   2.805V     2.483V     1.998V
664.4ps   1.829V     2.442V     869.5mV
755.2ps   1.214V     2.411V     621.6mV
827.1ps   837.7mV    2.127V     466.8mV
1.089ns   323.4mV    873.2mV    97.76mV
1.367ns   73.33mV    340mV      22.2mV
1.88ns    6.592mV    35.27mV    5.164mV
5ns       195.8uV    290uV      204.2uV
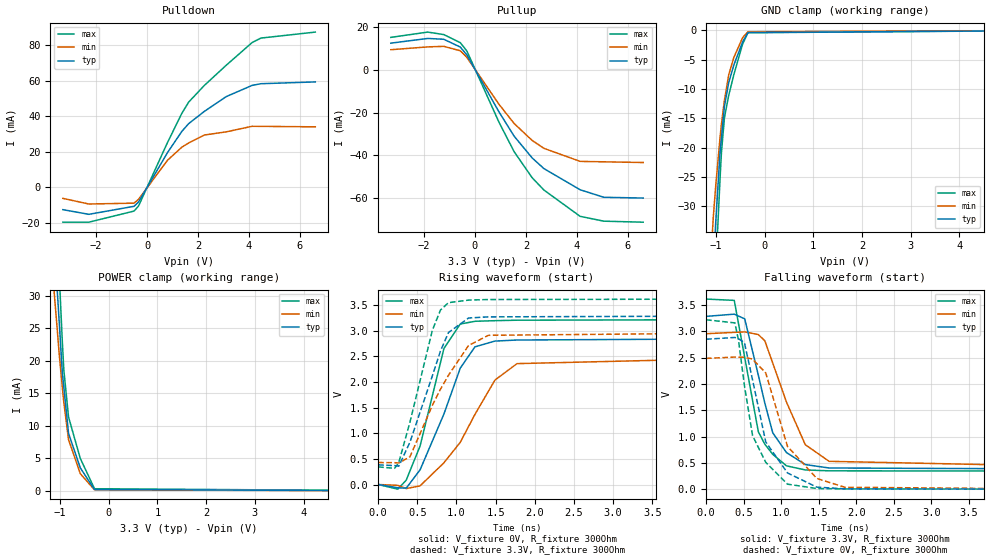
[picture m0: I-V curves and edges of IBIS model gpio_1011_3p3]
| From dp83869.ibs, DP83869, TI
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|   gpio_1011_3p3 Model
[Model]   gpio_1011_3p3
Model_type   I/O
Polarity   Non-Inverting
Enable   Active-Low
Vinl = 0.7
Vinh = 1.7
Vmeas = 1.65
Vref = 0
Cref = 2pF
Rref = 100000
|   typ   min   max
C_comp   1.10585pF   1.10585pF   1.45739pF
| Where Nom  PVT is Nominal Process, 3.3V,  27C
|   Fast PVT is Strong Process,  3.63V, -40C
|   Slow PVT is Weak Process,   2.97V, 125C
[Voltage Range]   3.3   2.97   3.63
|Junction Temperature
[Temperature Range]   27   125   -40
[Pullup Reference]   3.3   2.97   3.63
[Pulldown Reference]   -0   -0   -0
[Power Clamp Reference]   3.3   2.97   3.63
[GND Clamp Reference]   0   0   0
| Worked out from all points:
|   slope of the pulldown table from 0 to 0.495 V, typ, clamps not added: 41.1 ohm
|   slope of the pullup table from 0 to 0.495 V, typ, clamps not added: 47.2 ohm
|   GND clamp passes 1 mA (typ) near -0.40 V on its own axis
|   POWER clamp passes 1 mA (typ) near -0.40 V on its own axis
|   falling waveform, V_fixture 3.3V, R_fixture 300Ohm: 20-80 % time 312ps typ, 402ps min, 258ps max; typ from 3.29 V to 0.383 V
|   rising waveform, V_fixture 0V, R_fixture 300Ohm: 20-80 % time 407ps typ, 581ps min, 310ps max; typ from 0 V to 2.84 V
|   rising waveform, V_fixture 3.3V, R_fixture 300Ohm: 20-80 % time 386ps typ, 514ps min, 314ps max; typ from 0.383 V to 3.29 V
|   falling waveform, V_fixture 0V, R_fixture 300Ohm: 20-80 % time 324ps typ, 395ps min, 276ps max; typ from 2.85 V to 0 V
[Pulldown]
|   Voltage   I(typ)   I(min)   I(max)
-3.3V     -12.52mA   -6.182mA   -19.56mA
-2.282V   -15.15mA   -9.354mA   -19.57mA
-508.9mV  -10.64mA   -8.868mA   -13.32mA
-331.6mV  -8.175mA   -6.711mA   -10.43mA
801.3mV   19.5mA     15.21mA    25.15mA
1.367V    31.5mA     22.6mA     41.67mA
1.635V    35.85mA    24.96mA    47.94mA
2.244V    42.65mA    29.41mA    57.24mA
3.101V    50.97mA    31.18mA    68.56mA
4.125V    57.34mA    34.33mA    81.43mA
4.467V    58.25mA    34.29mA    83.91mA
6.6V      59.27mA    34.02mA    87.27mA
[GND Clamp]
|   Voltage   I(typ)   I(min)   I(max)
-3.3V     -489.2mA   -422.2mA   -556.8mA
-1.127V   -53.92mA   -42.18mA   -66.66mA
-1.052V   -41.16mA   -31.77mA   -50.65mA
-1.004V   -32.9mA    -26.64mA   -41.19mA
-914.6mV  -20.87mA   -18.28mA   -25.37mA
-885.1mV  -18.27mA   -15.94mA   -20.77mA
-823.7mV  -12.92mA   -11.9mA    -14.89mA
-736.6mV  -8.93mA    -7.6mA     -11.1mA
-630.6mV  -5.904mA   -4.619mA   -7.552mA
-450.4mV  -1.987mA   -1.242mA   -2.33mA
-340.6mV  -374.8uA   -237.3uA   -408.4uA
6.6V      0A         0A         0A
[Pullup]
|   Voltage   I(typ)   I(min)   I(max)
-3.3V     12.62mA    9.54mA     15.33mA
-1.852V   14.83mA    10.87mA    17.81mA
-1.222V   14.44mA    11.12mA    16.64mA
-576.2mV  10.79mA    9.06mA     12.86mA
-317.8mV  7.129mA    5.964mA    8.964mA
941mV     -19.59mA   -16.01mA   -24.41mA
1.537V    -31mA      -25.06mA   -38.27mA
2.244V    -41.2mA    -33mA      -50.49mA
2.706V    -46.21mA   -36.7mA    -56.26mA
4.127V    -56.13mA   -42.82mA   -68.59mA
5.054V    -59.65mA   -43.02mA   -70.85mA
6.6V      -60.01mA   -43.35mA   -71.33mA
[POWER Clamp]
|   Voltage   I(typ)   I(min)   I(max)
-3.3V     592.7mA    473.7mA    711.1mA
-1.183V   53.31mA    37.95mA    74.64mA
-1.164V   49.83mA    35.35mA    69.48mA
-1.12V    41.55mA    30.52mA    57.76mA
-1.071V   32.55mA    26.06mA    46.37mA
-1.012V   25.37mA    20.62mA    32.49mA
-952.3mV  18.16mA    15.9mA     22.88mA
-921.7mV  15.93mA    13.56mA    18.58mA
-824.5mV  8.83mA     7.863mA    11.33mA
-583.1mV  3.532mA    2.647mA    4.979mA
-292mV    218.9uA    166.6uA    335.6uA
6.6V      0A         0A         0A
[Ramp]
R_load = 300
|   typ   min   max
dV/dt_r   1.70484/4.05839e-10   1.48376/5.78893e-10   1.9285/3.08309e-10
dV/dt_f   1.74139/3.09623e-10   1.51625/4.00682e-10   1.96246/2.57347e-10
[Falling Waveform]
V_fixture = 3.3V
V_fixture_min = 2.97V
V_fixture_max = 3.63V
R_fixture = 300Ohm
C_fixture = 0F
|   Time   V(typ)   V(min)   V(max)
0s        3.286V     2.956V     3.615V
374.8ps   3.328V     2.982V     3.59V
514.3ps   3.239V     2.991V     2.503V
695.5ps   2.167V     2.94V      1.092V
781.8ps   1.639V     2.822V     855.7mV
887.7ps   1.072V     2.397V     662.6mV
1.07ns    696.3mV    1.657V     443.9mV
1.321ns   468.2mV    845.8mV    366.1mV
1.638ns   402.9mV    529.4mV    348.7mV
5ns       383.3mV    429.3mV    343.8mV
[Rising Waveform]
V_fixture = 0V
V_fixture_min = 0V
V_fixture_max = 0V
R_fixture = 300Ohm
C_fixture = 0F
|   Time   V(typ)   V(min)   V(max)
0s        191uV      290.2uV    195.1uV
250.1ps   -63.22mV   -16.19mV   -90.49mV
358.1ps   -70.47mV   -78.94mV   85.16mV
535.1ps   286.2mV    -25.49mV   751.4mV
839.7ps   1.375V     423.8mV    2.652V
1.048ns   2.268V     822.7mV    3.127V
1.236ns   2.683V     1.367V     3.181V
1.49ns    2.795V     2.033V     3.193V
1.773ns   2.816V     2.356V     3.202V
5ns       2.842V     2.473V     3.214V
[Rising Waveform]
V_fixture = 3.3V
V_fixture_min = 2.97V
V_fixture_max = 3.63V
R_fixture = 300Ohm
C_fixture = 0F
|   Time   V(typ)   V(min)   V(max)
0s        383.3mV    429.3mV    343.8mV
209.7ps   368.8mV    425.5mV    315.3mV
263.6ps   357.7mV    419.7mV    431.6mV
405.5ps   825.8mV    541.3mV    1.215V
692.2ps   2.119V     1.543V     3.008V
795.5ps   2.602V     1.857V     3.4V
897.3ps   2.961V     2.128V     3.544V
1.154ns   3.245V     2.71V      3.594V
1.409ns   3.267V     2.908V     3.605V
5ns       3.285V     2.956V     3.614V
[Falling Waveform]
|Gnd
V_fixture = 0V
V_fixture_min = 0V
V_fixture_max = 0V
R_fixture = 300Ohm
C_fixture = 0F
|   Time   V(typ)   V(min)   V(max)
0s        2.851V     2.487V     3.221V
383.4ps   2.885V     2.512V     3.162V
432.2ps   2.861V     2.51V      2.826V
511ps     2.782V     2.508V     1.964V
618.9ps   2.077V     2.473V     1.017V
794.3ps   898.3mV    2.21V      510.7mV
1.084ns   308.5mV    814mV      95.35mV
1.474ns   38.86mV    204mV      12.78mV
1.849ns   6.523mV    36.13mV    4.942mV
5ns       184.2uV    274uV      192.1uV
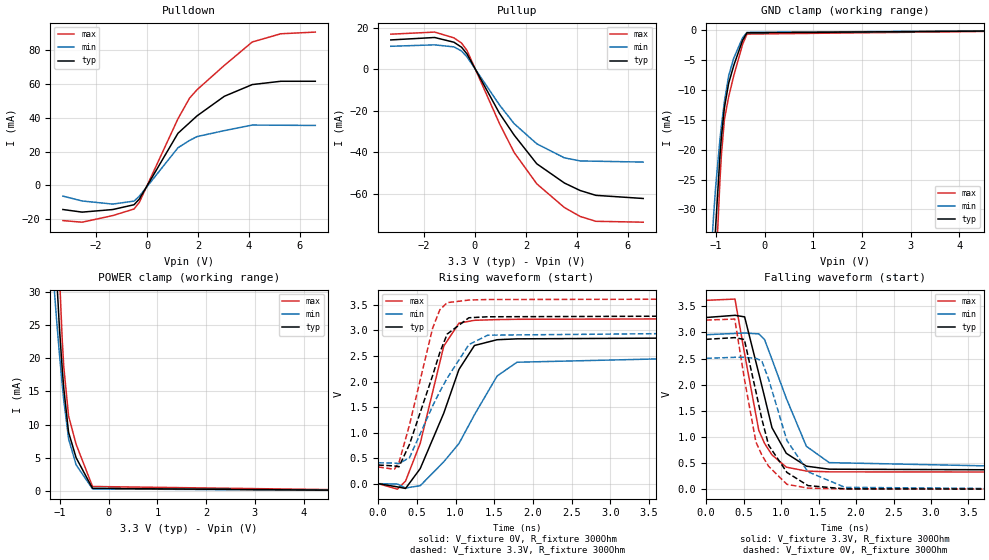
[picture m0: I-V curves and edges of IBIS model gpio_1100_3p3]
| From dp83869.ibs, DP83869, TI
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|   gpio_1100_3p3 Model
[Model]   gpio_1100_3p3
Model_type   I/O
Polarity   Non-Inverting
Enable   Active-Low
Vinl = 0.7
Vinh = 1.7
Vmeas = 1.65
Vref = 0
Cref = 2pF
Rref = 100000
|   typ   min   max
C_comp   1.10585pF   1.10585pF   1.45739pF
| Where Nom  PVT is Nominal Process, 3.3V,  27C
|   Fast PVT is Strong Process,  3.63V, -40C
|   Slow PVT is Weak Process,   2.97V, 125C
[Voltage Range]   3.3   2.97   3.63
|Junction Temperature
[Temperature Range]   27   125   -40
[Pullup Reference]   3.3   2.97   3.63
[Pulldown Reference]   0   0   0
[Power Clamp Reference]   3.3   2.97   3.63
[GND Clamp Reference]   0   0   0
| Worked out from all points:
|   slope of the pulldown table from 0 to 0.495 V, typ, clamps not added: 38.4 ohm
|   slope of the pullup table from 0 to 0.495 V, typ, clamps not added: 44.7 ohm
|   GND clamp passes 1 mA (typ) near -0.41 V on its own axis
|   POWER clamp passes 1 mA (typ) near -0.41 V on its own axis
|   falling waveform, V_fixture 3.3V, R_fixture 300Ohm: 20-80 % time 320ps typ, 406ps min, 269ps max; typ from 3.29 V to 0.365 V
|   rising waveform, V_fixture 0V, R_fixture 300Ohm: 20-80 % time 414ps typ, 593ps min, 311ps max; typ from 0 V to 2.86 V
|   rising waveform, V_fixture 3.3V, R_fixture 300Ohm: 20-80 % time 385ps typ, 517ps min, 311ps max; typ from 0.365 V to 3.29 V
|   falling waveform, V_fixture 0V, R_fixture 300Ohm: 20-80 % time 329ps typ, 393ps min, 283ps max; typ from 2.87 V to 0 V
[Pulldown]
|   Voltage   I(typ)   I(min)   I(max)
-3.3V     -14.39mA   -6.428mA   -20.96mA
-2.545V   -15.94mA   -9.334mA   -21.91mA
-1.344V   -14.4mA    -11.17mA   -17.99mA
-509.8mV  -11.55mA   -9.389mA   -14.09mA
-302.9mV  -8.189mA   -6.533mA   -10.18mA
1.214V    30.85mA    22.24mA    39.47mA
1.668V    37.11mA    26.6mA     51.68mA
1.961V    41.16mA    28.87mA    56.66mA
3.031V    52.78mA    32.41mA    71.1mA
4.128V    59.73mA    35.72mA    85mA
5.245V    61.69mA    35.61mA    89.87mA
6.6V      61.7mA     35.49mA    90.87mA
[GND Clamp]
|   Voltage   I(typ)   I(min)   I(max)
-3.3V     -489.2mA   -422.2mA   -556.8mA
-1.128V   -53.94mA   -41.75mA   -66.49mA
-1.053V   -40.94mA   -31.89mA   -50.85mA
-1.004V   -32.91mA   -26.23mA   -40.88mA
-914.8mV  -20.88mA   -18.15mA   -24.96mA
-886mV    -17.91mA   -16.01mA   -20.9mA
-824.7mV  -12.98mA   -11.96mA   -14.96mA
-737.5mV  -8.884mA   -7.637mA   -11.14mA
-632.6mV  -5.898mA   -4.664mA   -7.616mA
-450.4mV  -1.653mA   -1.242mA   -2.33mA
-360.4mV  -415.6uA   -340.7uA   -627.7uA
6.6V      0A         0A         0A
[Pullup]
|   Voltage   I(typ)   I(min)   I(max)
-3.3V     14.29mA    11.22mA    17.07mA
-1.581V   15.47mA    11.91mA    18.08mA
-824.7mV  13.18mA    10.92mA    15.29mA
-525.7mV  10.76mA    8.939mA    12.78mA
-311.8mV  7.509mA    6.117mA    9.2mA
964.1mV   -21.23mA   -17.17mA   -26.21mA
1.537V    -31.71mA   -26.18mA   -40.09mA
2.425V    -45.59mA   -35.93mA   -55.29mA
3.508V    -54.88mA   -42.72mA   -66.74mA
4.127V    -58.52mA   -44.22mA   -71.05mA
4.743V    -60.85mA   -44.35mA   -73.4mA
6.6V      -62.37mA   -44.77mA   -73.83mA
[POWER Clamp]
|   Voltage   I(typ)   I(min)   I(max)
-3.3V     592.7mA    473.7mA    711.1mA
-1.183V   53.33mA    37.6mA     74.54mA
-1.164V   49.45mA    35.35mA    69.48mA
-1.121V   40.99mA    30.62mA    58.01mA
-1.071V   32.56mA    25.84mA    45.66mA
-1.013V   24.62mA    20.7mA     32.69mA
-952.4mV  18.17mA    15.83mA    22.43mA
-922.7mV  15.44mA    13.63mA    18.69mA
-824.7mV  8.834mA    7.855mA    11.3mA
-669.2mV  4.995mA    3.928mA    7.01mA
-332.6mV  387.6uA    312.9uA    668.4uA
6.6V      0A         0A         0A
[Ramp]
R_load = 300
|   typ   min   max
dV/dt_r   1.71567/4.12929e-10   1.49484/5.91178e-10   1.93869/3.0987e-10
dV/dt_f   1.7529/3.19385e-10   1.529/4.04563e-10   1.97296/2.68288e-10
[Falling Waveform]
V_fixture = 3.3V
V_fixture_min = 2.97V
V_fixture_max = 3.63V
R_fixture = 300Ohm
C_fixture = 0F
|   Time   V(typ)   V(min)   V(max)
0s        3.286V     2.957V     3.615V
385.1ps   3.328V     2.981V     3.639V
513.8ps   3.298V     2.989V     2.587V
702.2ps   2.218V     2.973V     1.129V
779.1ps   1.771V     2.865V     877.7mV
878.7ps   1.177V     2.485V     656.6mV
1.07ns    685.9mV    1.738V     422mV
1.338ns   440.4mV    820.8mV    346.6mV
1.642ns   382.8mV    508.2mV    331.6mV
5ns       364.7mV    408.5mV    326.9mV
[Rising Waveform]
V_fixture = 0V
V_fixture_min = 0V
V_fixture_max = 0V
R_fixture = 300Ohm
C_fixture = 0F
|   Time   V(typ)   V(min)   V(max)
0s        183.6uV    277.6uV    187.5uV
248.4ps   -63.07mV   -7.739mV   -107.8mV
353.9ps   -93.79mV   -84.03mV   52.28mV
542.9ps   294.5mV    -40.35mV   789.2mV
847.8ps   1.382V     429.5mV    2.696V
1.044ns   2.238V     787mV      3.144V
1.244ns   2.706V     1.349V     3.199V
1.537ns   2.819V     2.109V     3.213V
1.794ns   2.836V     2.378V     3.219V
5ns       2.86V      2.492V     3.231V
[Rising Waveform]
V_fixture = 3.3V
V_fixture_min = 2.97V
V_fixture_max = 3.63V
R_fixture = 300Ohm
C_fixture = 0F
|   Time   V(typ)   V(min)   V(max)
0s        364.7mV    408.5mV    326.9mV
208.8ps   347.5mV    403.5mV    281.9mV
268.1ps   330.3mV    392.4mV    411.1mV
404.6ps   770.1mV    509.8mV    1.152V
702.2ps   2.112V     1.517V     3.04V
795.9ps   2.566V     1.803V     3.404V
891.8ps   2.93V      2.067V     3.545V
1.172ns   3.249V     2.723V     3.596V
1.416ns   3.268V     2.908V     3.606V
5ns       3.286V     2.956V     3.615V
[Falling Waveform]
|Gnd
V_fixture = 0V
V_fixture_min = 0V
V_fixture_max = 0V
R_fixture = 300Ohm
C_fixture = 0F
|   Time   V(typ)   V(min)   V(max)
0s        2.868V     2.504V     3.237V
382.2ps   2.901V     2.524V     3.256V
510.2ps   2.865V     2.524V     2.113V
664.1ps   1.87V      2.504V     903.9mV
743.4ps   1.343V     2.455V     653.5mV
834.1ps   841.7mV    2.104V     437.6mV
1.078ns   320.8mV    933.3mV    92.77mV
1.359ns   68.27mV    332.9mV    20.3mV
1.852ns   6.245mV    34.96mV    4.688mV
5ns       177.7uV    262.9uV    184.5uV
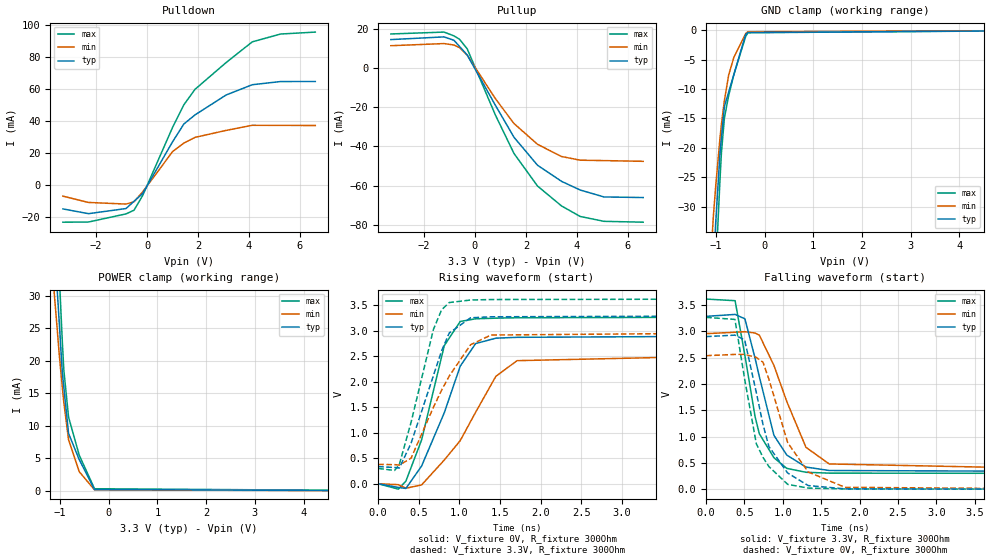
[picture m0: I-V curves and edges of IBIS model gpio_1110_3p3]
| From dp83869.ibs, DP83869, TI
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|   gpio_1110_3p3 Model
[Model]   gpio_1110_3p3
Model_type   I/O
Polarity   Non-Inverting
Enable   Active-Low
Vinl = 0.7
Vinh = 1.7
Vmeas = 1.65
Vref = 0
Cref = 2pF
Rref = 100000
|   typ   min   max
C_comp   1.10585pF   1.10585pF   1.45739pF
| Where Nom  PVT is Nominal Process, 3.3V,  27C
|   Fast PVT is Strong Process,  3.63V, -40C
|   Slow PVT is Weak Process,   2.97V, 125C
[Voltage Range]   3.3   2.97   3.63
|Junction Temperature
[Temperature Range]   27   125   -40
[Pullup Reference]   3.3   2.97   3.63
[Pulldown Reference]   -0   -0   -0
[Power Clamp Reference]   3.3   2.97   3.63
[GND Clamp Reference]   0   0   0
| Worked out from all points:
|   slope of the pulldown table from 0 to 0.495 V, typ, clamps not added: 34.3 ohm
|   slope of the pullup table from 0 to 0.495 V, typ, clamps not added: 40 ohm
|   GND clamp passes 1 mA (typ) near -0.40 V on its own axis
|   POWER clamp passes 1 mA (typ) near -0.40 V on its own axis
|   falling waveform, V_fixture 3.3V, R_fixture 300Ohm: 20-80 % time 308ps typ, 393ps min, 258ps max; typ from 3.29 V to 0.336 V
|   rising waveform, V_fixture 0V, R_fixture 300Ohm: 20-80 % time 402ps typ, 577ps min, 302ps max; typ from 0 V to 2.89 V
|   rising waveform, V_fixture 3.3V, R_fixture 300Ohm: 20-80 % time 371ps typ, 489ps min, 301ps max; typ from 0.336 V to 3.29 V
|   falling waveform, V_fixture 0V, R_fixture 300Ohm: 20-80 % time 313ps typ, 378ps min, 269ps max; typ from 2.9 V to 0 V
[Pulldown]
|   Voltage   I(typ)   I(min)   I(max)
-3.3V     -14.68mA   -6.73mA    -22.98mA
-2.297V   -17.66mA   -10.65mA   -22.87mA
-824.5mV  -14.47mA   -11.66mA   -17.8mA
-510.8mV  -9.948mA   -10.28mA   -15.51mA
-168.2mV  -5.012mA   -3.977mA   -6.258mA
1.006V    27.32mA    21.15mA    36.35mA
1.445V    38.32mA    26.43mA    50.32mA
1.882V    44.01mA    29.97mA    59.97mA
3.106V    56.47mA    34.34mA    76.73mA
4.127V    62.83mA    37.52mA    89.6mA
5.235V    64.83mA    37.46mA    94.48mA
6.6V      64.86mA    37.38mA    95.7mA
[GND Clamp]
|   Voltage   I(typ)   I(min)   I(max)
-3.3V     -489.2mA   -422.2mA   -556.8mA
-1.127V   -53.92mA   -42.17mA   -66.66mA
-1.052V   -41.16mA   -31.77mA   -50.65mA
-1.004V   -32.9mA    -26.64mA   -41.19mA
-914.6mV  -20.86mA   -18.28mA   -25.36mA
-885.1mV  -18.27mA   -15.94mA   -20.77mA
-823.7mV  -12.95mA   -11.9mA    -14.89mA
-736.6mV  -10.5mA    -7.6mA     -11.1mA
-630.6mV  -7.526mA   -4.619mA   -7.552mA
-387mV    -682.6uA   -531.3uA   -1.02mA
-340.6mV  -372.6uA   -237.3uA   -408.4uA
6.6V      0A         0A         0A
[Pullup]
|   Voltage   I(typ)   I(min)   I(max)
-3.3V     14.42mA    11.3mA     17.28mA
-1.211V   15.8mA     12.4mA     18.24mA
-824.5mV  14.07mA    11.65mA    16.32mA
-605.9mV  10.93mA    10.34mA    14.59mA
-304.9mV  6.615mA    6.484mA    9.764mA
801.3mV   -19.01mA   -15.64mA   -23.97mA
1.532V    -35.32mA   -28.33mA   -43.57mA
2.455V    -49.56mA   -38.91mA   -60.15mA
3.397V    -57.76mA   -45.11mA   -70.28mA
4.126V    -62.16mA   -46.98mA   -75.63mA
5.062V    -65.7mA    -47.19mA   -78.11mA
6.6V      -66mA      -47.56mA   -78.55mA
[POWER Clamp]
|   Voltage   I(typ)   I(min)   I(max)
-3.3V     592.7mA    473.7mA    711.1mA
-1.183V   53.3mA     37.95mA    74.63mA
-1.164V   49.83mA    35.35mA    69.48mA
-1.12V    41.55mA    30.52mA    57.76mA
-1.071V   32.55mA    26.06mA    46.37mA
-1.012V   25.37mA    20.62mA    32.49mA
-952.3mV  18.16mA    15.9mA     22.88mA
-921.7mV  15.93mA    13.56mA    18.58mA
-824.5mV  8.829mA    7.863mA    11.33mA
-605.9mV  4.821mA    2.962mA    5.498mA
-292mV    217.7uA    166.6uA    335.6uA
6.6V      0A         0A         0A
[Ramp]
R_load = 300
|   typ   min   max
dV/dt_r   1.73548/4.00447e-10   1.51523/5.76219e-10   1.95744/3.00723e-10
dV/dt_f   1.77057/3.07476e-10   1.54743/3.91949e-10   1.98959/2.57393e-10
[Falling Waveform]
V_fixture = 3.3V
V_fixture_min = 2.97V
V_fixture_max = 3.63V
R_fixture = 300Ohm
C_fixture = 0F
|   Time   V(typ)   V(min)   V(max)
0s        3.287V     2.958V     3.616V
377.7ps   3.324V     2.985V     3.585V
505.8ps   3.24V      2.995V     2.54V
638ps     2.49V      2.97V      1.38V
693.6ps   2.14V      2.93V      1.054V
883.6ps   1.024V     2.354V     598.6mV
1.052ns   647.9mV    1.665V     395.3mV
1.301ns   420.7mV    796.4mV    321.4mV
1.604ns   355.2mV    479.8mV    305mV
5ns       336.3mV    378.7mV    300.4mV
[Rising Waveform]
V_fixture = 0V
V_fixture_min = 0V
V_fixture_max = 0V
R_fixture = 300Ohm
C_fixture = 0F
|   Time   V(typ)   V(min)   V(max)
0s        166.4uV    253.4uV    169.3uV
248ps     -72.07mV   -17.73mV   -105.8mV
341ps     -91.41mV   -87.92mV   52.29mV
534.4ps   347.3mV    -22.47mV   858.1mV
813.8ps   1.391V     465.1mV    2.705V
1.01ns    2.303V     844.9mV    3.178V
1.2ns     2.745V     1.402V     3.23V
1.448ns   2.85V      2.102V     3.242V
1.709ns   2.867V     2.41V      3.25V
5ns       2.893V     2.526V     3.263V
[Rising Waveform]
V_fixture = 3.3V
V_fixture_min = 2.97V
V_fixture_max = 3.63V
R_fixture = 300Ohm
C_fixture = 0F
|   Time   V(typ)   V(min)   V(max)
0s        336.3mV    378.7mV    300.4mV
202.3ps   318.2mV    374.8mV    260.3mV
260.7ps   309.4mV    365.5mV    381.8mV
405.3ps   795.8mV    502mV      1.206V
679.4ps   2.115V     1.496V     3.019V
780.7ps   2.604V     1.833V     3.406V
874.8ps   2.952V     2.109V     3.548V
1.137ns   3.249V     2.721V     3.597V
1.388ns   3.269V     2.912V     3.607V
5ns       3.287V     2.957V     3.616V
[Falling Waveform]
|Gnd
V_fixture = 0V
V_fixture_min = 0V
V_fixture_max = 0V
R_fixture = 300Ohm
C_fixture = 0F
|   Time   V(typ)   V(min)   V(max)
0s        2.902V     2.539V     3.268V
375.9ps   2.93V      2.563V     3.229V
502.6ps   2.839V     2.564V     2.09V
654.6ps   1.835V     2.506V     862mV
741.2ps   1.232V     2.414V     605.4mV
818.4ps   810.2mV    2.092V     429.5mV
1.063ns   306.7mV    883.4mV    91.53mV
1.331ns   68.33mV    326.5mV    20.47mV
1.809ns   6.356mV    35.76mV    4.281mV
5ns       160.5uV    239.7uV    166.8uV
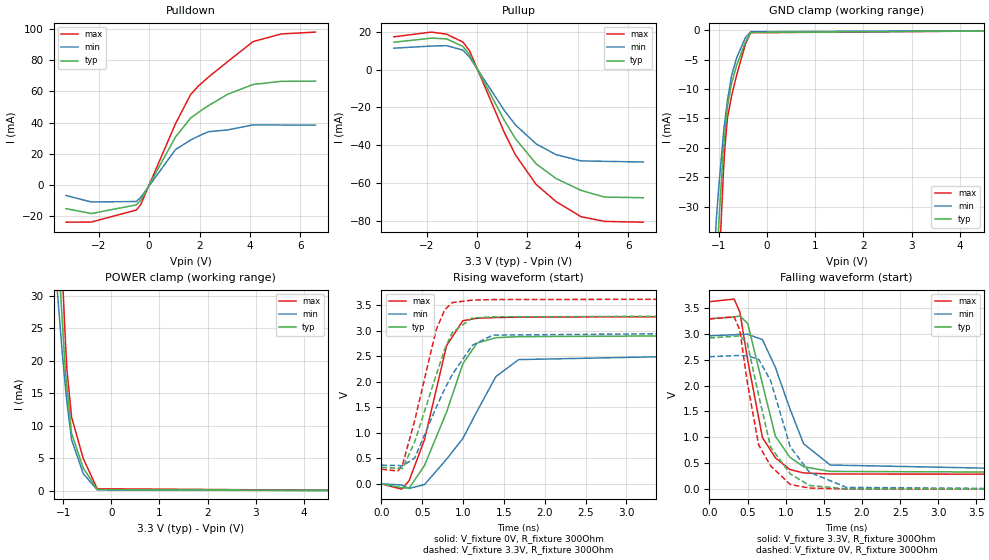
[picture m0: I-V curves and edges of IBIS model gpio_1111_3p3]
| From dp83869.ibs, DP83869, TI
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|   gpio_1111_3p3 Model
[Model]   gpio_1111_3p3
Model_type   I/O
Polarity   Non-Inverting
Enable   Active-Low
Vinl = 0.7
Vinh = 1.7
Vmeas = 1.65
Vref = 0
Cref = 2pF
Rref = 100000
|   typ   min   max
C_comp   1.10585pF   1.10585pF   1.45739pF
| Where Nom  PVT is Nominal Process, 3.3V,  27C
|   Fast PVT is Strong Process,  3.63V, -40C
|   Slow PVT is Weak Process,   2.97V, 125C
[Voltage Range]   3.3   2.97   3.63
|Junction Temperature
[Temperature Range]   27   125   -40
[Pullup Reference]   3.3   2.97   3.63
[Pulldown Reference]   0   0   0
[Power Clamp Reference]   3.3   2.97   3.63
[GND Clamp Reference]   0   0   0
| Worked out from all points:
|   slope of the pulldown table from 0 to 0.495 V, typ, clamps not added: 33.7 ohm
|   slope of the pullup table from 0 to 0.495 V, typ, clamps not added: 39.3 ohm
|   GND clamp passes 1 mA (typ) near -0.40 V on its own axis
|   POWER clamp passes 1 mA (typ) near -0.40 V on its own axis
|   falling waveform, V_fixture 3.3V, R_fixture 300Ohm: 20-80 % time 305ps typ, 387ps min, 255ps max; typ from 3.29 V to 0.323 V
|   rising waveform, V_fixture 0V, R_fixture 300Ohm: 20-80 % time 391ps typ, 562ps min, 295ps max; typ from 0 V to 2.91 V
|   rising waveform, V_fixture 3.3V, R_fixture 300Ohm: 20-80 % time 362ps typ, 472ps min, 296ps max; typ from 0.323 V to 3.29 V
|   falling waveform, V_fixture 0V, R_fixture 300Ohm: 20-80 % time 308ps typ, 373ps min, 265ps max; typ from 2.92 V to 0 V
[Pulldown]
|   Voltage   I(typ)   I(min)   I(max)
-3.3V     -15.34mA   -6.889mA   -24.05mA
-2.294V   -18.48mA   -11.06mA   -23.95mA
-511.8mV  -12.93mA   -10.74mA   -16.24mA
-334.6mV  -9.981mA   -8.148mA   -12.73mA
1.046V    30.74mA    22.65mA    39.28mA
1.644V    42.85mA    28.77mA    57.96mA
1.954V    46.55mA    31.26mA    63.52mA
2.352V    50.89mA    34.15mA    69.2mA
3.105V    58.12mA    35.26mA    79.06mA
4.128V    64.5mA     38.49mA    92.08mA
5.241V    66.51mA    38.44mA    96.99mA
6.6V      66.64mA    38.39mA    98.18mA
[GND Clamp]
|   Voltage   I(typ)   I(min)   I(max)
-3.3V     -489.2mA   -422.2mA   -556.8mA
-1.127V   -53.91mA   -42.17mA   -66.65mA
-1.052V   -41.16mA   -31.77mA   -50.65mA
-1.004V   -32.89mA   -26.64mA   -41.18mA
-914.6mV  -20.86mA   -18.27mA   -25.36mA
-885.1mV  -18.27mA   -15.94mA   -20.77mA
-823.7mV  -12.92mA   -11.9mA    -14.89mA
-736.6mV  -8.93mA    -7.6mA     -11.1mA
-630.6mV  -5.904mA   -4.619mA   -7.552mA
-450.4mV  -1.988mA   -1.242mA   -2.33mA
-340.6mV  -374.8uA   -237.3uA   -408.4uA
6.6V      0A         0A         0A
[Pullup]
|   Voltage   I(typ)   I(min)   I(max)
-3.3V     14.47mA    11.33mA    17.35mA
-1.811V   16.64mA    12.45mA    19.85mA
-1.21V    16.26mA    12.68mA    18.74mA
-565.3mV  12.27mA    10.31mA    14.63mA
-301.9mV  7.941mA    6.67mA     10.05mA
1.084V    -26.96mA   -21.7mA    -33.36mA
1.524V    -36.59mA   -29.31mA   -45.18mA
2.342V    -49.89mA   -39.33mA   -60.78mA
3.132V    -57.67mA   -45.05mA   -69.87mA
4.127V    -63.96mA   -48.35mA   -77.92mA
5.059V    -67.51mA   -48.58mA   -80.39mA
6.6V      -67.86mA   -48.95mA   -80.81mA
[POWER Clamp]
|   Voltage   I(typ)   I(min)   I(max)
-3.3V     592.7mA    473.7mA    711.1mA
-1.183V   53.3mA     37.94mA    74.63mA
-1.164V   49.83mA    35.35mA    69.48mA
-1.12V    41.55mA    30.52mA    57.76mA
-1.071V   32.54mA    26.06mA    46.37mA
-1.012V   25.37mA    20.62mA    32.49mA
-952.2mV  18.16mA    15.89mA    22.87mA
-921.7mV  15.93mA    13.56mA    18.58mA
-824.5mV  8.828mA    7.862mA    11.33mA
-583.1mV  3.531mA    2.647mA    4.979mA
-292mV    218.9uA    166.6uA    335.6uA
6.6V      0A         0A         0A
[Ramp]
R_load = 300
|   typ   min   max
dV/dt_r   1.74437/3.90282e-10   1.52439/5.61559e-10   1.96586/2.94097e-10
dV/dt_f   1.77861/3.02612e-10   1.55594/3.86885e-10   1.99709/2.53644e-10
[Falling Waveform]
V_fixture = 3.3V
V_fixture_min = 2.97V
V_fixture_max = 3.63V
R_fixture = 300Ohm
C_fixture = 0F
|   Time   V(typ)   V(min)   V(max)
0s        3.288V     2.958V     3.617V
324.4ps   3.323V     2.98V      3.668V
400.1ps   3.34V      2.986V     3.416V
502.3ps   3.198V     2.989V     2.488V
695.5ps   2.033V     2.886V     995.7mV
865.5ps   1.021V     2.349V     605.6mV
1.054ns   617.1mV    1.558V     378.9mV
1.235ns   433.2mV    875.5mV    313.8mV
1.585ns   342.6mV    465.9mV    292.9mV
5ns       323.3mV    365mV      288.4mV
[Rising Waveform]
V_fixture = 0V
V_fixture_min = 0V
V_fixture_max = 0V
R_fixture = 300Ohm
C_fixture = 0F
|   Time   V(typ)   V(min)   V(max)
0s        158.5uV    242.9uV    161.2uV
246.2ps   -74.1mV    -20.72mV   -103.3mV
338.6ps   -85.16mV   -89.05mV   60.65mV
526.9ps   359.4mV    -14.77mV   864.3mV
798.6ps   1.409V     485mV      2.71V
997.2ps   2.353V     889.5mV    3.193V
1.171ns   2.756V     1.423V     3.242V
1.401ns   2.861V     2.099V     3.255V
1.68ns    2.882V     2.432V     3.264V
5ns       2.907V     2.541V     3.277V
[Rising Waveform]
V_fixture = 3.3V
V_fixture_min = 2.97V
V_fixture_max = 3.63V
R_fixture = 300Ohm
C_fixture = 0F
|   Time   V(typ)   V(min)   V(max)
0s        323.4mV    365mV      288.4mV
200ps     306.8mV    361.4mV    251.8mV
258.4ps   300.9mV    352.9mV    375.1mV
407.1ps   821.6mV    505.3mV    1.239V
669.3ps   2.127V     1.493V     3.013V
775.9ps   2.643V     1.862V     3.41V
868.2ps   2.965V     2.143V     3.548V
1.113ns   3.248V     2.713V     3.597V
1.365ns   3.269V     2.912V     3.607V
5ns       3.287V     2.958V     3.617V
[Falling Waveform]
|Gnd
V_fixture = 0V
V_fixture_min = 0V
V_fixture_max = 0V
R_fixture = 300Ohm
C_fixture = 0F
|   Time   V(typ)   V(min)   V(max)
0s        2.917V     2.555V     3.283V
324.4ps   2.949V     2.576V     3.326V
398.7ps   2.958V     2.579V     3.072V
497.7ps   2.815V     2.575V     2.056V
645.8ps   1.813V     2.505V     854.1mV
802.7ps   813.6mV    2.096V     449.8mV
1.06ns    294.8mV    818.8mV    90.6mV
1.31ns    72.15mV    328.4mV    21.97mV
1.798ns   6.431mV    34.5mV     4.461mV
5ns       152.5uV    228.5uV    158.6uV
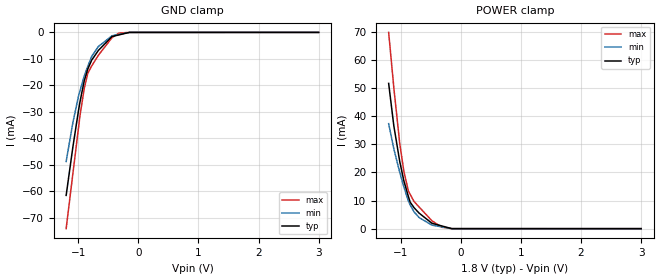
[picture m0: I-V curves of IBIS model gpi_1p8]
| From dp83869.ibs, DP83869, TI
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|   gpi_1p8 Model
[Model]   gpi_1p8
Model_type   Input
Vinl = 0.344
Vinh = 1.204
|   typ   min   max
C_comp   1.311pF   1.163pF   1.491pF
| Where Nom  PVT is Nominal Process, 1.8V,  27C
|   Fast PVT is Strong Process,  1.98V, -40C
|   Slow PVT is Weak Process,   1.62V, 125C
[Voltage Range]   1.8   1.62   1.98
|Junction Temperature
[Temperature Range]   27   125   -40
[Power Clamp Reference]   1.8   1.62   1.98
[GND Clamp Reference]   0   0   0
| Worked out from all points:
|   GND clamp passes 1 mA (typ) near -0.33 V on its own axis
|   POWER clamp passes 1 mA (typ) near -0.32 V on its own axis
[GND Clamp]
|   Voltage   I(typ)   I(min)   I(max)
-1.2V     -61.54mA   -48.75mA   -74.1mA
-1.088V   -43.25mA   -34.07mA   -53.32mA
-995mV    -29.57mA   -24.1mA    -36.14mA
-968.3mV  -26.01mA   -21.97mA   -31.21mA
-899.9mV  -18.36mA   -16.51mA   -21.24mA
-840.2mV  -13.84mA   -12.82mA   -15.44mA
-775.7mV  -10.5mA    -9.062mA   -12.69mA
-664.4mV  -6.816mA   -5.346mA   -8.657mA
-437.4mV  -1.576mA   -1.275mA   -1.997mA
-324.5mV  -958uA     -775.8uA   -272.4uA
-149.3mV  -2.203uA   -2.968uA   -2.255uA
3V        0A         0A         0A
[POWER Clamp]
|   Voltage   I(typ)   I(min)   I(max)
-1.2V     51.63mA    37.31mA    69.75mA
-1.114V   36.55mA    28.4mA     50.11mA
-1.015V   23.8mA     19.97mA    30.16mA
-946.5mV  16.95mA    14.77mA    20.3mA
-871.3mV  11.4mA     9.834mA    13.35mA
-843.1mV  9.453mA    8.467mA    12.24mA
-777.2mV  7.435mA    5.952mA    9.635mA
-692.6mV  5.505mA    3.931mA    7.686mA
-479.9mV  1.916mA    1.253mA    2.792mA
-316.1mV  967.2uA    633.4uA    502.9uA
-149.3mV  3.216uA    3.672uA    3.629uA
3V        0A         0A         0A
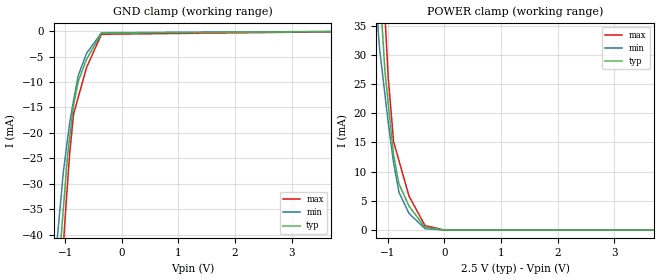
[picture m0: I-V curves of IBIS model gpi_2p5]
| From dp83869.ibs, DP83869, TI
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|   gpi_2p5 Model
[Model]   gpi_2p5
Model_type   Input
Vinl = 0.7
Vinh = 1.7
|   typ   min   max
C_comp   1.246pF   1.092pF   1.323pF
| Where Nom  PVT is Nominal Process, 2.5V,  27C
|   Fast PVT is Strong Process,  2.75V, -40C
|   Slow PVT is Weak Process,   2.25V, 125C
[Voltage Range]   2.5   2.25   2.75
|Junction Temperature
[Temperature Range]   27   125   -40
[Power Clamp Reference]   2.5   2.25   2.75
[GND Clamp Reference]   0   0   0
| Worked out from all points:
|   GND clamp passes 1 mA (typ) near -0.41 V on its own axis
|   POWER clamp passes 1 mA (typ) near -0.41 V on its own axis
[GND Clamp]
|   Voltage   I(typ)   I(min)   I(max)
-2.5V     -295.5mA   -255.2mA   -336.8mA
-1.157V   -55.31mA   -42.93mA   -66.74mA
-1.067V   -39.92mA   -32.04mA   -49.35mA
-1.031V   -34.79mA   -27.63mA   -42.3mA
-1.012V   -32.13mA   -25.98mA   -38.65mA
-958.4mV  -24.66mA   -21.33mA   -30.08mA
-921.6mV  -21.01mA   -18.13mA   -24.18mA
-851.9mV  -14.59mA   -13.68mA   -16.38mA
-769.6mV  -9.909mA   -8.785mA   -13.07mA
-624.1mV  -5.6mA     -4.414mA   -7.224mA
-358.6mV  -403.7uA   -323.1uA   -619.3uA
5V        0A         0A         0A
[POWER Clamp]
|   Voltage   I(typ)   I(min)   I(max)
-2.5V     339.8mA    271.7mA    405mA
-1.167V   45.55mA    34.15mA    62.62mA
-1.139V   41.2mA     30.75mA    56.05mA
-1.09V    33.82mA    26.76mA    44.88mA
-1.048V   27.29mA    23.21mA    36.87mA
-990.6mV  21.73mA    18.48mA    26.23mA
-895.4mV  12.86mA    11.51mA    15.16mA
-800.3mV  7.881mA    6.461mA    11.9mA
-624.1mV  4.121mA    2.854mA    5.842mA
-341.3mV  450.7uA    231.8uA    759uA
-641.9uV  340.8nA    275.8nA    685.4nA
5V        0A         0A         0A
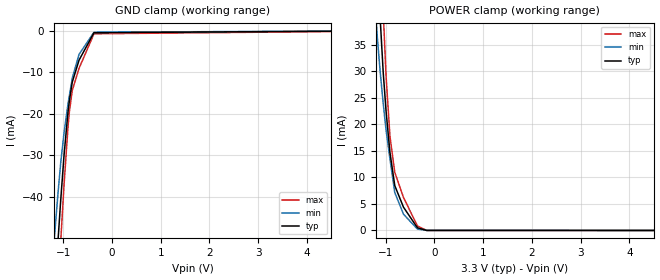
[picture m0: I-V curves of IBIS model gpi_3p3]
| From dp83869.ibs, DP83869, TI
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|   gpi_3p3 Model
[Model]   gpi_3p3
Model_type   Input
Vinl = 0.7
Vinh = 1.7
|   typ   min   max
C_comp   1.10585pF   1.10585pF   1.45739pF
| Where Nom  PVT is Nominal Process, 3.3V,  27C
|   Fast PVT is Strong Process,  3.63V, -40C
|   Slow PVT is Weak Process,   2.97V, 125C
[Voltage Range]   3.3   2.97   3.63
|Junction Temperature
[Temperature Range]   27   125   -40
[Power Clamp Reference]   3.3   2.97   3.63
[GND Clamp Reference]   0   0   0
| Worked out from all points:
|   GND clamp passes 1 mA (typ) near -0.41 V on its own axis
|   POWER clamp passes 1 mA (typ) near -0.41 V on its own axis
[GND Clamp]
|   Voltage   I(typ)   I(min)   I(max)
-3.3V     -489.2mA   -422.2mA   -556.8mA
-1.28V    -82.45mA   -65.01mA   -99.94mA
-1.181V   -63.78mA   -49.61mA   -78.13mA
-1.112V   -51.16mA   -39.58mA   -63.18mA
-1.053V   -40.83mA   -31.81mA   -50.72mA
-983.4mV  -29.82mA   -24.49mA   -36.94mA
-904.2mV  -19.73mA   -17.71mA   -23.39mA
-874.5mV  -16.85mA   -15.6mA    -19.48mA
-815.1mV  -12.37mA   -11.39mA   -14.37mA
-676.5mV  -7.109mA   -5.724mA   -9.073mA
-369.6mV  -510.5uA   -393.7uA   -767.2uA
6.6V      0A         0A         0A
[POWER Clamp]
|   Voltage   I(typ)   I(min)   I(max)
-3.3V     594mA      474.8mA    712.4mA
-1.261V   70.44mA    48.25mA    95.96mA
-1.171V   51.04mA    36.09mA    71.41mA
-1.112V   39.49mA    29.61mA    55.79mA
-1.053V   29.84mA    23.98mA    41.3mA
-993.3mV  22.39mA    18.86mA    28.96mA
-914.1mV  14.69mA    13.45mA    17.73mA
-815.1mV  8.441mA    7.138mA    10.94mA
-636.9mV  4.394mA    3.067mA    6.224mA
-349.8mV  501.8uA    266.4uA    847.9uA
-161.7mV  8.371uA    26.43uA    12.74uA
6.6V      0A         0A         0A
